VERSION 5.8 ;
BUSBITCHARS "[]" ;
DIVIDERCHAR "/" ;
UNITS
    DATABASE MICRONS 1000 ;
END UNITS

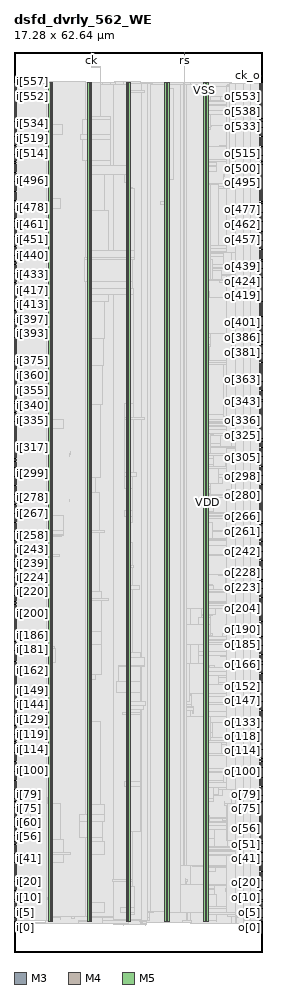
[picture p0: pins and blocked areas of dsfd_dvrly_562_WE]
MACRO dsfd_dvrly_562_WE
  FOREIGN dsfd_dvrly_562_WE 0 0 ;
  CLASS BLOCK ;
  SIZE 17.28 BY 62.64 ;
  PIN ck
    DIRECTION INPUT ;
    USE SIGNAL ;
    PORT
      LAYER M3 ;
        RECT  5.4 62.496 5.418 62.64 ;
    END
  END ck
  PIN ck_o
    DIRECTION OUTPUT ;
    USE SIGNAL ;
    PORT
      LAYER M4 ;
        RECT  17.088 60.432 17.28 60.456 ;
    END
  END ck_o
  PIN i[0]
    DIRECTION INPUT ;
    USE SIGNAL ;
    PORT
      LAYER M4 ;
        RECT  0 2.208 0.192 2.232 ;
    END
  END i[0]
  PIN i[100]
    DIRECTION INPUT ;
    USE SIGNAL ;
    PORT
      LAYER M4 ;
        RECT  0 12.624 0.192 12.648 ;
    END
  END i[100]
  PIN i[101]
    DIRECTION INPUT ;
    USE SIGNAL ;
    PORT
      LAYER M4 ;
        RECT  0 12.72 0.192 12.744 ;
    END
  END i[101]
  PIN i[102]
    DIRECTION INPUT ;
    USE SIGNAL ;
    PORT
      LAYER M4 ;
        RECT  0 12.816 0.192 12.84 ;
    END
  END i[102]
  PIN i[103]
    DIRECTION INPUT ;
    USE SIGNAL ;
    PORT
      LAYER M4 ;
        RECT  0 12.912 0.192 12.936 ;
    END
  END i[103]
  PIN i[104]
    DIRECTION INPUT ;
    USE SIGNAL ;
    PORT
      LAYER M4 ;
        RECT  0 13.008 0.192 13.032 ;
    END
  END i[104]
  PIN i[105]
    DIRECTION INPUT ;
    USE SIGNAL ;
    PORT
      LAYER M4 ;
        RECT  0 13.104 0.192 13.128 ;
    END
  END i[105]
  PIN i[106]
    DIRECTION INPUT ;
    USE SIGNAL ;
    PORT
      LAYER M4 ;
        RECT  0 13.2 0.192 13.224 ;
    END
  END i[106]
  PIN i[107]
    DIRECTION INPUT ;
    USE SIGNAL ;
    PORT
      LAYER M4 ;
        RECT  0 13.344 0.192 13.368 ;
    END
  END i[107]
  PIN i[108]
    DIRECTION INPUT ;
    USE SIGNAL ;
    PORT
      LAYER M4 ;
        RECT  0 13.44 0.192 13.464 ;
    END
  END i[108]
  PIN i[109]
    DIRECTION INPUT ;
    USE SIGNAL ;
    PORT
      LAYER M4 ;
        RECT  0 13.536 0.192 13.56 ;
    END
  END i[109]
  PIN i[10]
    DIRECTION INPUT ;
    USE SIGNAL ;
    PORT
      LAYER M4 ;
        RECT  0 3.264 0.192 3.288 ;
    END
  END i[10]
  PIN i[110]
    DIRECTION INPUT ;
    USE SIGNAL ;
    PORT
      LAYER M4 ;
        RECT  0 13.632 0.192 13.656 ;
    END
  END i[110]
  PIN i[111]
    DIRECTION INPUT ;
    USE SIGNAL ;
    PORT
      LAYER M4 ;
        RECT  0 13.728 0.192 13.752 ;
    END
  END i[111]
  PIN i[112]
    DIRECTION INPUT ;
    USE SIGNAL ;
    PORT
      LAYER M4 ;
        RECT  0 13.824 0.192 13.848 ;
    END
  END i[112]
  PIN i[113]
    DIRECTION INPUT ;
    USE SIGNAL ;
    PORT
      LAYER M4 ;
        RECT  0 13.968 0.192 13.992 ;
    END
  END i[113]
  PIN i[114]
    DIRECTION INPUT ;
    USE SIGNAL ;
    PORT
      LAYER M4 ;
        RECT  0 14.064 0.192 14.088 ;
    END
  END i[114]
  PIN i[115]
    DIRECTION INPUT ;
    USE SIGNAL ;
    PORT
      LAYER M4 ;
        RECT  0 14.16 0.192 14.184 ;
    END
  END i[115]
  PIN i[116]
    DIRECTION INPUT ;
    USE SIGNAL ;
    PORT
      LAYER M4 ;
        RECT  0 14.256 0.192 14.28 ;
    END
  END i[116]
  PIN i[117]
    DIRECTION INPUT ;
    USE SIGNAL ;
    PORT
      LAYER M4 ;
        RECT  0 14.352 0.192 14.376 ;
    END
  END i[117]
  PIN i[118]
    DIRECTION INPUT ;
    USE SIGNAL ;
    PORT
      LAYER M4 ;
        RECT  0 14.448 0.192 14.472 ;
    END
  END i[118]
  PIN i[119]
    DIRECTION INPUT ;
    USE SIGNAL ;
    PORT
      LAYER M4 ;
        RECT  0 14.592 0.192 14.616 ;
    END
  END i[119]
  PIN i[11]
    DIRECTION INPUT ;
    USE SIGNAL ;
    PORT
      LAYER M4 ;
        RECT  0 3.36 0.192 3.384 ;
    END
  END i[11]
  PIN i[120]
    DIRECTION INPUT ;
    USE SIGNAL ;
    PORT
      LAYER M4 ;
        RECT  0 14.688 0.192 14.712 ;
    END
  END i[120]
  PIN i[121]
    DIRECTION INPUT ;
    USE SIGNAL ;
    PORT
      LAYER M4 ;
        RECT  0 14.784 0.192 14.808 ;
    END
  END i[121]
  PIN i[122]
    DIRECTION INPUT ;
    USE SIGNAL ;
    PORT
      LAYER M4 ;
        RECT  0 14.88 0.192 14.904 ;
    END
  END i[122]
  PIN i[123]
    DIRECTION INPUT ;
    USE SIGNAL ;
    PORT
      LAYER M4 ;
        RECT  0 14.976 0.192 15 ;
    END
  END i[123]
  PIN i[124]
    DIRECTION INPUT ;
    USE SIGNAL ;
    PORT
      LAYER M4 ;
        RECT  0 15.072 0.192 15.096 ;
    END
  END i[124]
  PIN i[125]
    DIRECTION INPUT ;
    USE SIGNAL ;
    PORT
      LAYER M4 ;
        RECT  0 15.216 0.192 15.24 ;
    END
  END i[125]
  PIN i[126]
    DIRECTION INPUT ;
    USE SIGNAL ;
    PORT
      LAYER M4 ;
        RECT  0 15.312 0.192 15.336 ;
    END
  END i[126]
  PIN i[127]
    DIRECTION INPUT ;
    USE SIGNAL ;
    PORT
      LAYER M4 ;
        RECT  0 15.408 0.192 15.432 ;
    END
  END i[127]
  PIN i[128]
    DIRECTION INPUT ;
    USE SIGNAL ;
    PORT
      LAYER M4 ;
        RECT  0 15.504 0.192 15.528 ;
    END
  END i[128]
  PIN i[129]
    DIRECTION INPUT ;
    USE SIGNAL ;
    PORT
      LAYER M4 ;
        RECT  0 15.6 0.192 15.624 ;
    END
  END i[129]
  PIN i[12]
    DIRECTION INPUT ;
    USE SIGNAL ;
    PORT
      LAYER M4 ;
        RECT  0 3.456 0.192 3.48 ;
    END
  END i[12]
  PIN i[130]
    DIRECTION INPUT ;
    USE SIGNAL ;
    PORT
      LAYER M4 ;
        RECT  0 15.696 0.192 15.72 ;
    END
  END i[130]
  PIN i[131]
    DIRECTION INPUT ;
    USE SIGNAL ;
    PORT
      LAYER M4 ;
        RECT  0 15.84 0.192 15.864 ;
    END
  END i[131]
  PIN i[132]
    DIRECTION INPUT ;
    USE SIGNAL ;
    PORT
      LAYER M4 ;
        RECT  0 15.936 0.192 15.96 ;
    END
  END i[132]
  PIN i[133]
    DIRECTION INPUT ;
    USE SIGNAL ;
    PORT
      LAYER M4 ;
        RECT  0 16.032 0.192 16.056 ;
    END
  END i[133]
  PIN i[134]
    DIRECTION INPUT ;
    USE SIGNAL ;
    PORT
      LAYER M4 ;
        RECT  0 16.128 0.192 16.152 ;
    END
  END i[134]
  PIN i[135]
    DIRECTION INPUT ;
    USE SIGNAL ;
    PORT
      LAYER M4 ;
        RECT  0 16.224 0.192 16.248 ;
    END
  END i[135]
  PIN i[136]
    DIRECTION INPUT ;
    USE SIGNAL ;
    PORT
      LAYER M4 ;
        RECT  0 16.32 0.192 16.344 ;
    END
  END i[136]
  PIN i[137]
    DIRECTION INPUT ;
    USE SIGNAL ;
    PORT
      LAYER M4 ;
        RECT  0 16.464 0.192 16.488 ;
    END
  END i[137]
  PIN i[138]
    DIRECTION INPUT ;
    USE SIGNAL ;
    PORT
      LAYER M4 ;
        RECT  0 16.56 0.192 16.584 ;
    END
  END i[138]
  PIN i[139]
    DIRECTION INPUT ;
    USE SIGNAL ;
    PORT
      LAYER M4 ;
        RECT  0 16.656 0.192 16.68 ;
    END
  END i[139]
  PIN i[13]
    DIRECTION INPUT ;
    USE SIGNAL ;
    PORT
      LAYER M4 ;
        RECT  0 3.552 0.192 3.576 ;
    END
  END i[13]
  PIN i[140]
    DIRECTION INPUT ;
    USE SIGNAL ;
    PORT
      LAYER M4 ;
        RECT  0 16.752 0.192 16.776 ;
    END
  END i[140]
  PIN i[141]
    DIRECTION INPUT ;
    USE SIGNAL ;
    PORT
      LAYER M4 ;
        RECT  0 16.848 0.192 16.872 ;
    END
  END i[141]
  PIN i[142]
    DIRECTION INPUT ;
    USE SIGNAL ;
    PORT
      LAYER M4 ;
        RECT  0 16.944 0.192 16.968 ;
    END
  END i[142]
  PIN i[143]
    DIRECTION INPUT ;
    USE SIGNAL ;
    PORT
      LAYER M4 ;
        RECT  0 17.04 0.192 17.064 ;
    END
  END i[143]
  PIN i[144]
    DIRECTION INPUT ;
    USE SIGNAL ;
    PORT
      LAYER M4 ;
        RECT  0 17.184 0.192 17.208 ;
    END
  END i[144]
  PIN i[145]
    DIRECTION INPUT ;
    USE SIGNAL ;
    PORT
      LAYER M4 ;
        RECT  0 17.28 0.192 17.304 ;
    END
  END i[145]
  PIN i[146]
    DIRECTION INPUT ;
    USE SIGNAL ;
    PORT
      LAYER M4 ;
        RECT  0 17.376 0.192 17.4 ;
    END
  END i[146]
  PIN i[147]
    DIRECTION INPUT ;
    USE SIGNAL ;
    PORT
      LAYER M4 ;
        RECT  0 17.472 0.192 17.496 ;
    END
  END i[147]
  PIN i[148]
    DIRECTION INPUT ;
    USE SIGNAL ;
    PORT
      LAYER M4 ;
        RECT  0 17.568 0.192 17.592 ;
    END
  END i[148]
  PIN i[149]
    DIRECTION INPUT ;
    USE SIGNAL ;
    PORT
      LAYER M4 ;
        RECT  0 17.664 0.192 17.688 ;
    END
  END i[149]
  PIN i[14]
    DIRECTION INPUT ;
    USE SIGNAL ;
    PORT
      LAYER M4 ;
        RECT  0 3.696 0.192 3.72 ;
    END
  END i[14]
  PIN i[150]
    DIRECTION INPUT ;
    USE SIGNAL ;
    PORT
      LAYER M4 ;
        RECT  0 17.808 0.192 17.832 ;
    END
  END i[150]
  PIN i[151]
    DIRECTION INPUT ;
    USE SIGNAL ;
    PORT
      LAYER M4 ;
        RECT  0 17.904 0.192 17.928 ;
    END
  END i[151]
  PIN i[152]
    DIRECTION INPUT ;
    USE SIGNAL ;
    PORT
      LAYER M4 ;
        RECT  0 18 0.192 18.024 ;
    END
  END i[152]
  PIN i[153]
    DIRECTION INPUT ;
    USE SIGNAL ;
    PORT
      LAYER M4 ;
        RECT  0 18.096 0.192 18.12 ;
    END
  END i[153]
  PIN i[154]
    DIRECTION INPUT ;
    USE SIGNAL ;
    PORT
      LAYER M4 ;
        RECT  0 18.192 0.192 18.216 ;
    END
  END i[154]
  PIN i[155]
    DIRECTION INPUT ;
    USE SIGNAL ;
    PORT
      LAYER M4 ;
        RECT  0 18.288 0.192 18.312 ;
    END
  END i[155]
  PIN i[156]
    DIRECTION INPUT ;
    USE SIGNAL ;
    PORT
      LAYER M4 ;
        RECT  0 18.432 0.192 18.456 ;
    END
  END i[156]
  PIN i[157]
    DIRECTION INPUT ;
    USE SIGNAL ;
    PORT
      LAYER M4 ;
        RECT  0 18.528 0.192 18.552 ;
    END
  END i[157]
  PIN i[158]
    DIRECTION INPUT ;
    USE SIGNAL ;
    PORT
      LAYER M4 ;
        RECT  0 18.624 0.192 18.648 ;
    END
  END i[158]
  PIN i[159]
    DIRECTION INPUT ;
    USE SIGNAL ;
    PORT
      LAYER M4 ;
        RECT  0 18.72 0.192 18.744 ;
    END
  END i[159]
  PIN i[15]
    DIRECTION INPUT ;
    USE SIGNAL ;
    PORT
      LAYER M4 ;
        RECT  0 3.792 0.192 3.816 ;
    END
  END i[15]
  PIN i[160]
    DIRECTION INPUT ;
    USE SIGNAL ;
    PORT
      LAYER M4 ;
        RECT  0 18.816 0.192 18.84 ;
    END
  END i[160]
  PIN i[161]
    DIRECTION INPUT ;
    USE SIGNAL ;
    PORT
      LAYER M4 ;
        RECT  0 18.912 0.192 18.936 ;
    END
  END i[161]
  PIN i[162]
    DIRECTION INPUT ;
    USE SIGNAL ;
    PORT
      LAYER M4 ;
        RECT  0 19.056 0.192 19.08 ;
    END
  END i[162]
  PIN i[163]
    DIRECTION INPUT ;
    USE SIGNAL ;
    PORT
      LAYER M4 ;
        RECT  0 19.152 0.192 19.176 ;
    END
  END i[163]
  PIN i[164]
    DIRECTION INPUT ;
    USE SIGNAL ;
    PORT
      LAYER M4 ;
        RECT  0 19.248 0.192 19.272 ;
    END
  END i[164]
  PIN i[165]
    DIRECTION INPUT ;
    USE SIGNAL ;
    PORT
      LAYER M4 ;
        RECT  0 19.344 0.192 19.368 ;
    END
  END i[165]
  PIN i[166]
    DIRECTION INPUT ;
    USE SIGNAL ;
    PORT
      LAYER M4 ;
        RECT  0 19.44 0.192 19.464 ;
    END
  END i[166]
  PIN i[167]
    DIRECTION INPUT ;
    USE SIGNAL ;
    PORT
      LAYER M4 ;
        RECT  0 19.536 0.192 19.56 ;
    END
  END i[167]
  PIN i[168]
    DIRECTION INPUT ;
    USE SIGNAL ;
    PORT
      LAYER M4 ;
        RECT  0 19.68 0.192 19.704 ;
    END
  END i[168]
  PIN i[169]
    DIRECTION INPUT ;
    USE SIGNAL ;
    PORT
      LAYER M4 ;
        RECT  0 19.776 0.192 19.8 ;
    END
  END i[169]
  PIN i[16]
    DIRECTION INPUT ;
    USE SIGNAL ;
    PORT
      LAYER M4 ;
        RECT  0 3.888 0.192 3.912 ;
    END
  END i[16]
  PIN i[170]
    DIRECTION INPUT ;
    USE SIGNAL ;
    PORT
      LAYER M4 ;
        RECT  0 19.872 0.192 19.896 ;
    END
  END i[170]
  PIN i[171]
    DIRECTION INPUT ;
    USE SIGNAL ;
    PORT
      LAYER M4 ;
        RECT  0 19.968 0.192 19.992 ;
    END
  END i[171]
  PIN i[172]
    DIRECTION INPUT ;
    USE SIGNAL ;
    PORT
      LAYER M4 ;
        RECT  0 20.064 0.192 20.088 ;
    END
  END i[172]
  PIN i[173]
    DIRECTION INPUT ;
    USE SIGNAL ;
    PORT
      LAYER M4 ;
        RECT  0 20.16 0.192 20.184 ;
    END
  END i[173]
  PIN i[174]
    DIRECTION INPUT ;
    USE SIGNAL ;
    PORT
      LAYER M4 ;
        RECT  0 20.304 0.192 20.328 ;
    END
  END i[174]
  PIN i[175]
    DIRECTION INPUT ;
    USE SIGNAL ;
    PORT
      LAYER M4 ;
        RECT  0 20.4 0.192 20.424 ;
    END
  END i[175]
  PIN i[176]
    DIRECTION INPUT ;
    USE SIGNAL ;
    PORT
      LAYER M4 ;
        RECT  0 20.496 0.192 20.52 ;
    END
  END i[176]
  PIN i[177]
    DIRECTION INPUT ;
    USE SIGNAL ;
    PORT
      LAYER M4 ;
        RECT  0 20.592 0.192 20.616 ;
    END
  END i[177]
  PIN i[178]
    DIRECTION INPUT ;
    USE SIGNAL ;
    PORT
      LAYER M4 ;
        RECT  0 20.688 0.192 20.712 ;
    END
  END i[178]
  PIN i[179]
    DIRECTION INPUT ;
    USE SIGNAL ;
    PORT
      LAYER M4 ;
        RECT  0 20.784 0.192 20.808 ;
    END
  END i[179]
  PIN i[17]
    DIRECTION INPUT ;
    USE SIGNAL ;
    PORT
      LAYER M4 ;
        RECT  0 3.984 0.192 4.008 ;
    END
  END i[17]
  PIN i[180]
    DIRECTION INPUT ;
    USE SIGNAL ;
    PORT
      LAYER M4 ;
        RECT  0 20.88 0.192 20.904 ;
    END
  END i[180]
  PIN i[181]
    DIRECTION INPUT ;
    USE SIGNAL ;
    PORT
      LAYER M4 ;
        RECT  0 21.024 0.192 21.048 ;
    END
  END i[181]
  PIN i[182]
    DIRECTION INPUT ;
    USE SIGNAL ;
    PORT
      LAYER M4 ;
        RECT  0 21.12 0.192 21.144 ;
    END
  END i[182]
  PIN i[183]
    DIRECTION INPUT ;
    USE SIGNAL ;
    PORT
      LAYER M4 ;
        RECT  0 21.216 0.192 21.24 ;
    END
  END i[183]
  PIN i[184]
    DIRECTION INPUT ;
    USE SIGNAL ;
    PORT
      LAYER M4 ;
        RECT  0 21.312 0.192 21.336 ;
    END
  END i[184]
  PIN i[185]
    DIRECTION INPUT ;
    USE SIGNAL ;
    PORT
      LAYER M4 ;
        RECT  0 21.408 0.192 21.432 ;
    END
  END i[185]
  PIN i[186]
    DIRECTION INPUT ;
    USE SIGNAL ;
    PORT
      LAYER M4 ;
        RECT  0 21.504 0.192 21.528 ;
    END
  END i[186]
  PIN i[187]
    DIRECTION INPUT ;
    USE SIGNAL ;
    PORT
      LAYER M4 ;
        RECT  0 21.648 0.192 21.672 ;
    END
  END i[187]
  PIN i[188]
    DIRECTION INPUT ;
    USE SIGNAL ;
    PORT
      LAYER M4 ;
        RECT  0 21.744 0.192 21.768 ;
    END
  END i[188]
  PIN i[189]
    DIRECTION INPUT ;
    USE SIGNAL ;
    PORT
      LAYER M4 ;
        RECT  0 21.84 0.192 21.864 ;
    END
  END i[189]
  PIN i[18]
    DIRECTION INPUT ;
    USE SIGNAL ;
    PORT
      LAYER M4 ;
        RECT  0 4.08 0.192 4.104 ;
    END
  END i[18]
  PIN i[190]
    DIRECTION INPUT ;
    USE SIGNAL ;
    PORT
      LAYER M4 ;
        RECT  0 21.936 0.192 21.96 ;
    END
  END i[190]
  PIN i[191]
    DIRECTION INPUT ;
    USE SIGNAL ;
    PORT
      LAYER M4 ;
        RECT  0 22.032 0.192 22.056 ;
    END
  END i[191]
  PIN i[192]
    DIRECTION INPUT ;
    USE SIGNAL ;
    PORT
      LAYER M4 ;
        RECT  0 22.128 0.192 22.152 ;
    END
  END i[192]
  PIN i[193]
    DIRECTION INPUT ;
    USE SIGNAL ;
    PORT
      LAYER M4 ;
        RECT  0 22.272 0.192 22.296 ;
    END
  END i[193]
  PIN i[194]
    DIRECTION INPUT ;
    USE SIGNAL ;
    PORT
      LAYER M4 ;
        RECT  0 22.368 0.192 22.392 ;
    END
  END i[194]
  PIN i[195]
    DIRECTION INPUT ;
    USE SIGNAL ;
    PORT
      LAYER M4 ;
        RECT  0 22.464 0.192 22.488 ;
    END
  END i[195]
  PIN i[196]
    DIRECTION INPUT ;
    USE SIGNAL ;
    PORT
      LAYER M4 ;
        RECT  0 22.56 0.192 22.584 ;
    END
  END i[196]
  PIN i[197]
    DIRECTION INPUT ;
    USE SIGNAL ;
    PORT
      LAYER M4 ;
        RECT  0 22.656 0.192 22.68 ;
    END
  END i[197]
  PIN i[198]
    DIRECTION INPUT ;
    USE SIGNAL ;
    PORT
      LAYER M4 ;
        RECT  0 22.752 0.192 22.776 ;
    END
  END i[198]
  PIN i[199]
    DIRECTION INPUT ;
    USE SIGNAL ;
    PORT
      LAYER M4 ;
        RECT  0 22.896 0.192 22.92 ;
    END
  END i[199]
  PIN i[19]
    DIRECTION INPUT ;
    USE SIGNAL ;
    PORT
      LAYER M4 ;
        RECT  0 4.176 0.192 4.2 ;
    END
  END i[19]
  PIN i[1]
    DIRECTION INPUT ;
    USE SIGNAL ;
    PORT
      LAYER M4 ;
        RECT  0 2.304 0.192 2.328 ;
    END
  END i[1]
  PIN i[200]
    DIRECTION INPUT ;
    USE SIGNAL ;
    PORT
      LAYER M4 ;
        RECT  0 22.992 0.192 23.016 ;
    END
  END i[200]
  PIN i[201]
    DIRECTION INPUT ;
    USE SIGNAL ;
    PORT
      LAYER M4 ;
        RECT  0 23.088 0.192 23.112 ;
    END
  END i[201]
  PIN i[202]
    DIRECTION INPUT ;
    USE SIGNAL ;
    PORT
      LAYER M4 ;
        RECT  0 23.184 0.192 23.208 ;
    END
  END i[202]
  PIN i[203]
    DIRECTION INPUT ;
    USE SIGNAL ;
    PORT
      LAYER M4 ;
        RECT  0 23.28 0.192 23.304 ;
    END
  END i[203]
  PIN i[204]
    DIRECTION INPUT ;
    USE SIGNAL ;
    PORT
      LAYER M4 ;
        RECT  0 23.376 0.192 23.4 ;
    END
  END i[204]
  PIN i[205]
    DIRECTION INPUT ;
    USE SIGNAL ;
    PORT
      LAYER M4 ;
        RECT  0 23.52 0.192 23.544 ;
    END
  END i[205]
  PIN i[206]
    DIRECTION INPUT ;
    USE SIGNAL ;
    PORT
      LAYER M4 ;
        RECT  0 23.616 0.192 23.64 ;
    END
  END i[206]
  PIN i[207]
    DIRECTION INPUT ;
    USE SIGNAL ;
    PORT
      LAYER M4 ;
        RECT  0 23.712 0.192 23.736 ;
    END
  END i[207]
  PIN i[208]
    DIRECTION INPUT ;
    USE SIGNAL ;
    PORT
      LAYER M4 ;
        RECT  0 23.808 0.192 23.832 ;
    END
  END i[208]
  PIN i[209]
    DIRECTION INPUT ;
    USE SIGNAL ;
    PORT
      LAYER M4 ;
        RECT  0 23.904 0.192 23.928 ;
    END
  END i[209]
  PIN i[20]
    DIRECTION INPUT ;
    USE SIGNAL ;
    PORT
      LAYER M4 ;
        RECT  0 4.32 0.192 4.344 ;
    END
  END i[20]
  PIN i[210]
    DIRECTION INPUT ;
    USE SIGNAL ;
    PORT
      LAYER M4 ;
        RECT  0 24 0.192 24.024 ;
    END
  END i[210]
  PIN i[211]
    DIRECTION INPUT ;
    USE SIGNAL ;
    PORT
      LAYER M4 ;
        RECT  0 24.096 0.192 24.12 ;
    END
  END i[211]
  PIN i[212]
    DIRECTION INPUT ;
    USE SIGNAL ;
    PORT
      LAYER M4 ;
        RECT  0 24.24 0.192 24.264 ;
    END
  END i[212]
  PIN i[213]
    DIRECTION INPUT ;
    USE SIGNAL ;
    PORT
      LAYER M4 ;
        RECT  0 24.336 0.192 24.36 ;
    END
  END i[213]
  PIN i[214]
    DIRECTION INPUT ;
    USE SIGNAL ;
    PORT
      LAYER M4 ;
        RECT  0 24.432 0.192 24.456 ;
    END
  END i[214]
  PIN i[215]
    DIRECTION INPUT ;
    USE SIGNAL ;
    PORT
      LAYER M4 ;
        RECT  0 24.528 0.192 24.552 ;
    END
  END i[215]
  PIN i[216]
    DIRECTION INPUT ;
    USE SIGNAL ;
    PORT
      LAYER M4 ;
        RECT  0 24.624 0.192 24.648 ;
    END
  END i[216]
  PIN i[217]
    DIRECTION INPUT ;
    USE SIGNAL ;
    PORT
      LAYER M4 ;
        RECT  0 24.72 0.192 24.744 ;
    END
  END i[217]
  PIN i[218]
    DIRECTION INPUT ;
    USE SIGNAL ;
    PORT
      LAYER M4 ;
        RECT  0 24.864 0.192 24.888 ;
    END
  END i[218]
  PIN i[219]
    DIRECTION INPUT ;
    USE SIGNAL ;
    PORT
      LAYER M4 ;
        RECT  0 24.96 0.192 24.984 ;
    END
  END i[219]
  PIN i[21]
    DIRECTION INPUT ;
    USE SIGNAL ;
    PORT
      LAYER M4 ;
        RECT  0 4.416 0.192 4.44 ;
    END
  END i[21]
  PIN i[220]
    DIRECTION INPUT ;
    USE SIGNAL ;
    PORT
      LAYER M4 ;
        RECT  0 25.056 0.192 25.08 ;
    END
  END i[220]
  PIN i[221]
    DIRECTION INPUT ;
    USE SIGNAL ;
    PORT
      LAYER M4 ;
        RECT  0 25.152 0.192 25.176 ;
    END
  END i[221]
  PIN i[222]
    DIRECTION INPUT ;
    USE SIGNAL ;
    PORT
      LAYER M4 ;
        RECT  0 25.248 0.192 25.272 ;
    END
  END i[222]
  PIN i[223]
    DIRECTION INPUT ;
    USE SIGNAL ;
    PORT
      LAYER M4 ;
        RECT  0 25.344 0.192 25.368 ;
    END
  END i[223]
  PIN i[224]
    DIRECTION INPUT ;
    USE SIGNAL ;
    PORT
      LAYER M4 ;
        RECT  0 25.488 0.192 25.512 ;
    END
  END i[224]
  PIN i[225]
    DIRECTION INPUT ;
    USE SIGNAL ;
    PORT
      LAYER M4 ;
        RECT  0 25.584 0.192 25.608 ;
    END
  END i[225]
  PIN i[226]
    DIRECTION INPUT ;
    USE SIGNAL ;
    PORT
      LAYER M4 ;
        RECT  0 25.68 0.192 25.704 ;
    END
  END i[226]
  PIN i[227]
    DIRECTION INPUT ;
    USE SIGNAL ;
    PORT
      LAYER M4 ;
        RECT  0 25.776 0.192 25.8 ;
    END
  END i[227]
  PIN i[228]
    DIRECTION INPUT ;
    USE SIGNAL ;
    PORT
      LAYER M4 ;
        RECT  0 25.872 0.192 25.896 ;
    END
  END i[228]
  PIN i[229]
    DIRECTION INPUT ;
    USE SIGNAL ;
    PORT
      LAYER M4 ;
        RECT  0 25.968 0.192 25.992 ;
    END
  END i[229]
  PIN i[22]
    DIRECTION INPUT ;
    USE SIGNAL ;
    PORT
      LAYER M4 ;
        RECT  0 4.512 0.192 4.536 ;
    END
  END i[22]
  PIN i[230]
    DIRECTION INPUT ;
    USE SIGNAL ;
    PORT
      LAYER M4 ;
        RECT  0 26.112 0.192 26.136 ;
    END
  END i[230]
  PIN i[231]
    DIRECTION INPUT ;
    USE SIGNAL ;
    PORT
      LAYER M4 ;
        RECT  0 26.208 0.192 26.232 ;
    END
  END i[231]
  PIN i[232]
    DIRECTION INPUT ;
    USE SIGNAL ;
    PORT
      LAYER M4 ;
        RECT  0 26.304 0.192 26.328 ;
    END
  END i[232]
  PIN i[233]
    DIRECTION INPUT ;
    USE SIGNAL ;
    PORT
      LAYER M4 ;
        RECT  0 26.4 0.192 26.424 ;
    END
  END i[233]
  PIN i[234]
    DIRECTION INPUT ;
    USE SIGNAL ;
    PORT
      LAYER M4 ;
        RECT  0 26.496 0.192 26.52 ;
    END
  END i[234]
  PIN i[235]
    DIRECTION INPUT ;
    USE SIGNAL ;
    PORT
      LAYER M4 ;
        RECT  0 26.592 0.192 26.616 ;
    END
  END i[235]
  PIN i[236]
    DIRECTION INPUT ;
    USE SIGNAL ;
    PORT
      LAYER M4 ;
        RECT  0 26.736 0.192 26.76 ;
    END
  END i[236]
  PIN i[237]
    DIRECTION INPUT ;
    USE SIGNAL ;
    PORT
      LAYER M4 ;
        RECT  0 26.832 0.192 26.856 ;
    END
  END i[237]
  PIN i[238]
    DIRECTION INPUT ;
    USE SIGNAL ;
    PORT
      LAYER M4 ;
        RECT  0 26.928 0.192 26.952 ;
    END
  END i[238]
  PIN i[239]
    DIRECTION INPUT ;
    USE SIGNAL ;
    PORT
      LAYER M4 ;
        RECT  0 27.024 0.192 27.048 ;
    END
  END i[239]
  PIN i[23]
    DIRECTION INPUT ;
    USE SIGNAL ;
    PORT
      LAYER M4 ;
        RECT  0 4.608 0.192 4.632 ;
    END
  END i[23]
  PIN i[240]
    DIRECTION INPUT ;
    USE SIGNAL ;
    PORT
      LAYER M4 ;
        RECT  0 27.12 0.192 27.144 ;
    END
  END i[240]
  PIN i[241]
    DIRECTION INPUT ;
    USE SIGNAL ;
    PORT
      LAYER M4 ;
        RECT  0 27.216 0.192 27.24 ;
    END
  END i[241]
  PIN i[242]
    DIRECTION INPUT ;
    USE SIGNAL ;
    PORT
      LAYER M4 ;
        RECT  0 27.36 0.192 27.384 ;
    END
  END i[242]
  PIN i[243]
    DIRECTION INPUT ;
    USE SIGNAL ;
    PORT
      LAYER M4 ;
        RECT  0 27.456 0.192 27.48 ;
    END
  END i[243]
  PIN i[244]
    DIRECTION INPUT ;
    USE SIGNAL ;
    PORT
      LAYER M4 ;
        RECT  0 27.552 0.192 27.576 ;
    END
  END i[244]
  PIN i[245]
    DIRECTION INPUT ;
    USE SIGNAL ;
    PORT
      LAYER M4 ;
        RECT  0 27.648 0.192 27.672 ;
    END
  END i[245]
  PIN i[246]
    DIRECTION INPUT ;
    USE SIGNAL ;
    PORT
      LAYER M4 ;
        RECT  0 27.744 0.192 27.768 ;
    END
  END i[246]
  PIN i[247]
    DIRECTION INPUT ;
    USE SIGNAL ;
    PORT
      LAYER M4 ;
        RECT  0 27.84 0.192 27.864 ;
    END
  END i[247]
  PIN i[248]
    DIRECTION INPUT ;
    USE SIGNAL ;
    PORT
      LAYER M4 ;
        RECT  0 27.936 0.192 27.96 ;
    END
  END i[248]
  PIN i[249]
    DIRECTION INPUT ;
    USE SIGNAL ;
    PORT
      LAYER M4 ;
        RECT  0 28.08 0.192 28.104 ;
    END
  END i[249]
  PIN i[24]
    DIRECTION INPUT ;
    USE SIGNAL ;
    PORT
      LAYER M4 ;
        RECT  0 4.704 0.192 4.728 ;
    END
  END i[24]
  PIN i[250]
    DIRECTION INPUT ;
    USE SIGNAL ;
    PORT
      LAYER M4 ;
        RECT  0 28.176 0.192 28.2 ;
    END
  END i[250]
  PIN i[251]
    DIRECTION INPUT ;
    USE SIGNAL ;
    PORT
      LAYER M4 ;
        RECT  0 28.272 0.192 28.296 ;
    END
  END i[251]
  PIN i[252]
    DIRECTION INPUT ;
    USE SIGNAL ;
    PORT
      LAYER M4 ;
        RECT  0 28.368 0.192 28.392 ;
    END
  END i[252]
  PIN i[253]
    DIRECTION INPUT ;
    USE SIGNAL ;
    PORT
      LAYER M4 ;
        RECT  0 28.464 0.192 28.488 ;
    END
  END i[253]
  PIN i[254]
    DIRECTION INPUT ;
    USE SIGNAL ;
    PORT
      LAYER M4 ;
        RECT  0 28.56 0.192 28.584 ;
    END
  END i[254]
  PIN i[255]
    DIRECTION INPUT ;
    USE SIGNAL ;
    PORT
      LAYER M4 ;
        RECT  0 28.704 0.192 28.728 ;
    END
  END i[255]
  PIN i[256]
    DIRECTION INPUT ;
    USE SIGNAL ;
    PORT
      LAYER M4 ;
        RECT  0 28.8 0.192 28.824 ;
    END
  END i[256]
  PIN i[257]
    DIRECTION INPUT ;
    USE SIGNAL ;
    PORT
      LAYER M4 ;
        RECT  0 28.896 0.192 28.92 ;
    END
  END i[257]
  PIN i[258]
    DIRECTION INPUT ;
    USE SIGNAL ;
    PORT
      LAYER M4 ;
        RECT  0 28.992 0.192 29.016 ;
    END
  END i[258]
  PIN i[259]
    DIRECTION INPUT ;
    USE SIGNAL ;
    PORT
      LAYER M4 ;
        RECT  0 29.088 0.192 29.112 ;
    END
  END i[259]
  PIN i[25]
    DIRECTION INPUT ;
    USE SIGNAL ;
    PORT
      LAYER M4 ;
        RECT  0 4.8 0.192 4.824 ;
    END
  END i[25]
  PIN i[260]
    DIRECTION INPUT ;
    USE SIGNAL ;
    PORT
      LAYER M4 ;
        RECT  0 29.184 0.192 29.208 ;
    END
  END i[260]
  PIN i[261]
    DIRECTION INPUT ;
    USE SIGNAL ;
    PORT
      LAYER M4 ;
        RECT  0 29.328 0.192 29.352 ;
    END
  END i[261]
  PIN i[262]
    DIRECTION INPUT ;
    USE SIGNAL ;
    PORT
      LAYER M4 ;
        RECT  0 29.424 0.192 29.448 ;
    END
  END i[262]
  PIN i[263]
    DIRECTION INPUT ;
    USE SIGNAL ;
    PORT
      LAYER M4 ;
        RECT  0 29.52 0.192 29.544 ;
    END
  END i[263]
  PIN i[264]
    DIRECTION INPUT ;
    USE SIGNAL ;
    PORT
      LAYER M4 ;
        RECT  0 29.616 0.192 29.64 ;
    END
  END i[264]
  PIN i[265]
    DIRECTION INPUT ;
    USE SIGNAL ;
    PORT
      LAYER M4 ;
        RECT  0 29.712 0.192 29.736 ;
    END
  END i[265]
  PIN i[266]
    DIRECTION INPUT ;
    USE SIGNAL ;
    PORT
      LAYER M4 ;
        RECT  0 29.808 0.192 29.832 ;
    END
  END i[266]
  PIN i[267]
    DIRECTION INPUT ;
    USE SIGNAL ;
    PORT
      LAYER M4 ;
        RECT  0 29.952 0.192 29.976 ;
    END
  END i[267]
  PIN i[268]
    DIRECTION INPUT ;
    USE SIGNAL ;
    PORT
      LAYER M4 ;
        RECT  0 30.048 0.192 30.072 ;
    END
  END i[268]
  PIN i[269]
    DIRECTION INPUT ;
    USE SIGNAL ;
    PORT
      LAYER M4 ;
        RECT  0 30.144 0.192 30.168 ;
    END
  END i[269]
  PIN i[26]
    DIRECTION INPUT ;
    USE SIGNAL ;
    PORT
      LAYER M4 ;
        RECT  0 4.944 0.192 4.968 ;
    END
  END i[26]
  PIN i[270]
    DIRECTION INPUT ;
    USE SIGNAL ;
    PORT
      LAYER M4 ;
        RECT  0 30.24 0.192 30.264 ;
    END
  END i[270]
  PIN i[271]
    DIRECTION INPUT ;
    USE SIGNAL ;
    PORT
      LAYER M4 ;
        RECT  0 30.336 0.192 30.36 ;
    END
  END i[271]
  PIN i[272]
    DIRECTION INPUT ;
    USE SIGNAL ;
    PORT
      LAYER M4 ;
        RECT  0 30.432 0.192 30.456 ;
    END
  END i[272]
  PIN i[273]
    DIRECTION INPUT ;
    USE SIGNAL ;
    PORT
      LAYER M4 ;
        RECT  0 30.576 0.192 30.6 ;
    END
  END i[273]
  PIN i[274]
    DIRECTION INPUT ;
    USE SIGNAL ;
    PORT
      LAYER M4 ;
        RECT  0 30.672 0.192 30.696 ;
    END
  END i[274]
  PIN i[275]
    DIRECTION INPUT ;
    USE SIGNAL ;
    PORT
      LAYER M4 ;
        RECT  0 30.768 0.192 30.792 ;
    END
  END i[275]
  PIN i[276]
    DIRECTION INPUT ;
    USE SIGNAL ;
    PORT
      LAYER M4 ;
        RECT  0 30.864 0.192 30.888 ;
    END
  END i[276]
  PIN i[277]
    DIRECTION INPUT ;
    USE SIGNAL ;
    PORT
      LAYER M4 ;
        RECT  0 30.96 0.192 30.984 ;
    END
  END i[277]
  PIN i[278]
    DIRECTION INPUT ;
    USE SIGNAL ;
    PORT
      LAYER M4 ;
        RECT  0 31.056 0.192 31.08 ;
    END
  END i[278]
  PIN i[279]
    DIRECTION INPUT ;
    USE SIGNAL ;
    PORT
      LAYER M4 ;
        RECT  0 31.2 0.192 31.224 ;
    END
  END i[279]
  PIN i[27]
    DIRECTION INPUT ;
    USE SIGNAL ;
    PORT
      LAYER M4 ;
        RECT  0 5.04 0.192 5.064 ;
    END
  END i[27]
  PIN i[280]
    DIRECTION INPUT ;
    USE SIGNAL ;
    PORT
      LAYER M4 ;
        RECT  0 31.296 0.192 31.32 ;
    END
  END i[280]
  PIN i[281]
    DIRECTION INPUT ;
    USE SIGNAL ;
    PORT
      LAYER M4 ;
        RECT  0 31.392 0.192 31.416 ;
    END
  END i[281]
  PIN i[282]
    DIRECTION INPUT ;
    USE SIGNAL ;
    PORT
      LAYER M4 ;
        RECT  0 31.488 0.192 31.512 ;
    END
  END i[282]
  PIN i[283]
    DIRECTION INPUT ;
    USE SIGNAL ;
    PORT
      LAYER M4 ;
        RECT  0 31.584 0.192 31.608 ;
    END
  END i[283]
  PIN i[284]
    DIRECTION INPUT ;
    USE SIGNAL ;
    PORT
      LAYER M4 ;
        RECT  0 31.68 0.192 31.704 ;
    END
  END i[284]
  PIN i[285]
    DIRECTION INPUT ;
    USE SIGNAL ;
    PORT
      LAYER M4 ;
        RECT  0 31.776 0.192 31.8 ;
    END
  END i[285]
  PIN i[286]
    DIRECTION INPUT ;
    USE SIGNAL ;
    PORT
      LAYER M4 ;
        RECT  0 31.92 0.192 31.944 ;
    END
  END i[286]
  PIN i[287]
    DIRECTION INPUT ;
    USE SIGNAL ;
    PORT
      LAYER M4 ;
        RECT  0 32.016 0.192 32.04 ;
    END
  END i[287]
  PIN i[288]
    DIRECTION INPUT ;
    USE SIGNAL ;
    PORT
      LAYER M4 ;
        RECT  0 32.112 0.192 32.136 ;
    END
  END i[288]
  PIN i[289]
    DIRECTION INPUT ;
    USE SIGNAL ;
    PORT
      LAYER M4 ;
        RECT  0 32.208 0.192 32.232 ;
    END
  END i[289]
  PIN i[28]
    DIRECTION INPUT ;
    USE SIGNAL ;
    PORT
      LAYER M4 ;
        RECT  0 5.136 0.192 5.16 ;
    END
  END i[28]
  PIN i[290]
    DIRECTION INPUT ;
    USE SIGNAL ;
    PORT
      LAYER M4 ;
        RECT  0 32.304 0.192 32.328 ;
    END
  END i[290]
  PIN i[291]
    DIRECTION INPUT ;
    USE SIGNAL ;
    PORT
      LAYER M4 ;
        RECT  0 32.4 0.192 32.424 ;
    END
  END i[291]
  PIN i[292]
    DIRECTION INPUT ;
    USE SIGNAL ;
    PORT
      LAYER M4 ;
        RECT  0 32.544 0.192 32.568 ;
    END
  END i[292]
  PIN i[293]
    DIRECTION INPUT ;
    USE SIGNAL ;
    PORT
      LAYER M4 ;
        RECT  0 32.64 0.192 32.664 ;
    END
  END i[293]
  PIN i[294]
    DIRECTION INPUT ;
    USE SIGNAL ;
    PORT
      LAYER M4 ;
        RECT  0 32.736 0.192 32.76 ;
    END
  END i[294]
  PIN i[295]
    DIRECTION INPUT ;
    USE SIGNAL ;
    PORT
      LAYER M4 ;
        RECT  0 32.832 0.192 32.856 ;
    END
  END i[295]
  PIN i[296]
    DIRECTION INPUT ;
    USE SIGNAL ;
    PORT
      LAYER M4 ;
        RECT  0 32.928 0.192 32.952 ;
    END
  END i[296]
  PIN i[297]
    DIRECTION INPUT ;
    USE SIGNAL ;
    PORT
      LAYER M4 ;
        RECT  0 33.024 0.192 33.048 ;
    END
  END i[297]
  PIN i[298]
    DIRECTION INPUT ;
    USE SIGNAL ;
    PORT
      LAYER M4 ;
        RECT  0 33.168 0.192 33.192 ;
    END
  END i[298]
  PIN i[299]
    DIRECTION INPUT ;
    USE SIGNAL ;
    PORT
      LAYER M4 ;
        RECT  0 33.264 0.192 33.288 ;
    END
  END i[299]
  PIN i[29]
    DIRECTION INPUT ;
    USE SIGNAL ;
    PORT
      LAYER M4 ;
        RECT  0 5.232 0.192 5.256 ;
    END
  END i[29]
  PIN i[2]
    DIRECTION INPUT ;
    USE SIGNAL ;
    PORT
      LAYER M4 ;
        RECT  0 2.448 0.192 2.472 ;
    END
  END i[2]
  PIN i[300]
    DIRECTION INPUT ;
    USE SIGNAL ;
    PORT
      LAYER M4 ;
        RECT  0 33.36 0.192 33.384 ;
    END
  END i[300]
  PIN i[301]
    DIRECTION INPUT ;
    USE SIGNAL ;
    PORT
      LAYER M4 ;
        RECT  0 33.456 0.192 33.48 ;
    END
  END i[301]
  PIN i[302]
    DIRECTION INPUT ;
    USE SIGNAL ;
    PORT
      LAYER M4 ;
        RECT  0 33.552 0.192 33.576 ;
    END
  END i[302]
  PIN i[303]
    DIRECTION INPUT ;
    USE SIGNAL ;
    PORT
      LAYER M4 ;
        RECT  0 33.648 0.192 33.672 ;
    END
  END i[303]
  PIN i[304]
    DIRECTION INPUT ;
    USE SIGNAL ;
    PORT
      LAYER M4 ;
        RECT  0 33.792 0.192 33.816 ;
    END
  END i[304]
  PIN i[305]
    DIRECTION INPUT ;
    USE SIGNAL ;
    PORT
      LAYER M4 ;
        RECT  0 33.888 0.192 33.912 ;
    END
  END i[305]
  PIN i[306]
    DIRECTION INPUT ;
    USE SIGNAL ;
    PORT
      LAYER M4 ;
        RECT  0 33.984 0.192 34.008 ;
    END
  END i[306]
  PIN i[307]
    DIRECTION INPUT ;
    USE SIGNAL ;
    PORT
      LAYER M4 ;
        RECT  0 34.08 0.192 34.104 ;
    END
  END i[307]
  PIN i[308]
    DIRECTION INPUT ;
    USE SIGNAL ;
    PORT
      LAYER M4 ;
        RECT  0 34.176 0.192 34.2 ;
    END
  END i[308]
  PIN i[309]
    DIRECTION INPUT ;
    USE SIGNAL ;
    PORT
      LAYER M4 ;
        RECT  0 34.272 0.192 34.296 ;
    END
  END i[309]
  PIN i[30]
    DIRECTION INPUT ;
    USE SIGNAL ;
    PORT
      LAYER M4 ;
        RECT  0 5.328 0.192 5.352 ;
    END
  END i[30]
  PIN i[310]
    DIRECTION INPUT ;
    USE SIGNAL ;
    PORT
      LAYER M4 ;
        RECT  0 34.416 0.192 34.44 ;
    END
  END i[310]
  PIN i[311]
    DIRECTION INPUT ;
    USE SIGNAL ;
    PORT
      LAYER M4 ;
        RECT  0 34.512 0.192 34.536 ;
    END
  END i[311]
  PIN i[312]
    DIRECTION INPUT ;
    USE SIGNAL ;
    PORT
      LAYER M4 ;
        RECT  0 34.608 0.192 34.632 ;
    END
  END i[312]
  PIN i[313]
    DIRECTION INPUT ;
    USE SIGNAL ;
    PORT
      LAYER M4 ;
        RECT  0 34.704 0.192 34.728 ;
    END
  END i[313]
  PIN i[314]
    DIRECTION INPUT ;
    USE SIGNAL ;
    PORT
      LAYER M4 ;
        RECT  0 34.8 0.192 34.824 ;
    END
  END i[314]
  PIN i[315]
    DIRECTION INPUT ;
    USE SIGNAL ;
    PORT
      LAYER M4 ;
        RECT  0 34.896 0.192 34.92 ;
    END
  END i[315]
  PIN i[316]
    DIRECTION INPUT ;
    USE SIGNAL ;
    PORT
      LAYER M4 ;
        RECT  0 34.992 0.192 35.016 ;
    END
  END i[316]
  PIN i[317]
    DIRECTION INPUT ;
    USE SIGNAL ;
    PORT
      LAYER M4 ;
        RECT  0 35.136 0.192 35.16 ;
    END
  END i[317]
  PIN i[318]
    DIRECTION INPUT ;
    USE SIGNAL ;
    PORT
      LAYER M4 ;
        RECT  0 35.232 0.192 35.256 ;
    END
  END i[318]
  PIN i[319]
    DIRECTION INPUT ;
    USE SIGNAL ;
    PORT
      LAYER M4 ;
        RECT  0 35.328 0.192 35.352 ;
    END
  END i[319]
  PIN i[31]
    DIRECTION INPUT ;
    USE SIGNAL ;
    PORT
      LAYER M4 ;
        RECT  0 5.424 0.192 5.448 ;
    END
  END i[31]
  PIN i[320]
    DIRECTION INPUT ;
    USE SIGNAL ;
    PORT
      LAYER M4 ;
        RECT  0 35.424 0.192 35.448 ;
    END
  END i[320]
  PIN i[321]
    DIRECTION INPUT ;
    USE SIGNAL ;
    PORT
      LAYER M4 ;
        RECT  0 35.52 0.192 35.544 ;
    END
  END i[321]
  PIN i[322]
    DIRECTION INPUT ;
    USE SIGNAL ;
    PORT
      LAYER M4 ;
        RECT  0 35.616 0.192 35.64 ;
    END
  END i[322]
  PIN i[323]
    DIRECTION INPUT ;
    USE SIGNAL ;
    PORT
      LAYER M4 ;
        RECT  0 35.76 0.192 35.784 ;
    END
  END i[323]
  PIN i[324]
    DIRECTION INPUT ;
    USE SIGNAL ;
    PORT
      LAYER M4 ;
        RECT  0 35.856 0.192 35.88 ;
    END
  END i[324]
  PIN i[325]
    DIRECTION INPUT ;
    USE SIGNAL ;
    PORT
      LAYER M4 ;
        RECT  0 35.952 0.192 35.976 ;
    END
  END i[325]
  PIN i[326]
    DIRECTION INPUT ;
    USE SIGNAL ;
    PORT
      LAYER M4 ;
        RECT  0 36.048 0.192 36.072 ;
    END
  END i[326]
  PIN i[327]
    DIRECTION INPUT ;
    USE SIGNAL ;
    PORT
      LAYER M4 ;
        RECT  0 36.144 0.192 36.168 ;
    END
  END i[327]
  PIN i[328]
    DIRECTION INPUT ;
    USE SIGNAL ;
    PORT
      LAYER M4 ;
        RECT  0 36.24 0.192 36.264 ;
    END
  END i[328]
  PIN i[329]
    DIRECTION INPUT ;
    USE SIGNAL ;
    PORT
      LAYER M4 ;
        RECT  0 36.384 0.192 36.408 ;
    END
  END i[329]
  PIN i[32]
    DIRECTION INPUT ;
    USE SIGNAL ;
    PORT
      LAYER M4 ;
        RECT  0 5.568 0.192 5.592 ;
    END
  END i[32]
  PIN i[330]
    DIRECTION INPUT ;
    USE SIGNAL ;
    PORT
      LAYER M4 ;
        RECT  0 36.48 0.192 36.504 ;
    END
  END i[330]
  PIN i[331]
    DIRECTION INPUT ;
    USE SIGNAL ;
    PORT
      LAYER M4 ;
        RECT  0 36.576 0.192 36.6 ;
    END
  END i[331]
  PIN i[332]
    DIRECTION INPUT ;
    USE SIGNAL ;
    PORT
      LAYER M4 ;
        RECT  0 36.672 0.192 36.696 ;
    END
  END i[332]
  PIN i[333]
    DIRECTION INPUT ;
    USE SIGNAL ;
    PORT
      LAYER M4 ;
        RECT  0 36.768 0.192 36.792 ;
    END
  END i[333]
  PIN i[334]
    DIRECTION INPUT ;
    USE SIGNAL ;
    PORT
      LAYER M4 ;
        RECT  0 36.864 0.192 36.888 ;
    END
  END i[334]
  PIN i[335]
    DIRECTION INPUT ;
    USE SIGNAL ;
    PORT
      LAYER M4 ;
        RECT  0 37.008 0.192 37.032 ;
    END
  END i[335]
  PIN i[336]
    DIRECTION INPUT ;
    USE SIGNAL ;
    PORT
      LAYER M4 ;
        RECT  0 37.104 0.192 37.128 ;
    END
  END i[336]
  PIN i[337]
    DIRECTION INPUT ;
    USE SIGNAL ;
    PORT
      LAYER M4 ;
        RECT  0 37.2 0.192 37.224 ;
    END
  END i[337]
  PIN i[338]
    DIRECTION INPUT ;
    USE SIGNAL ;
    PORT
      LAYER M4 ;
        RECT  0 37.296 0.192 37.32 ;
    END
  END i[338]
  PIN i[339]
    DIRECTION INPUT ;
    USE SIGNAL ;
    PORT
      LAYER M4 ;
        RECT  0 37.392 0.192 37.416 ;
    END
  END i[339]
  PIN i[33]
    DIRECTION INPUT ;
    USE SIGNAL ;
    PORT
      LAYER M4 ;
        RECT  0 5.664 0.192 5.688 ;
    END
  END i[33]
  PIN i[340]
    DIRECTION INPUT ;
    USE SIGNAL ;
    PORT
      LAYER M4 ;
        RECT  0 37.488 0.192 37.512 ;
    END
  END i[340]
  PIN i[341]
    DIRECTION INPUT ;
    USE SIGNAL ;
    PORT
      LAYER M4 ;
        RECT  0 37.632 0.192 37.656 ;
    END
  END i[341]
  PIN i[342]
    DIRECTION INPUT ;
    USE SIGNAL ;
    PORT
      LAYER M4 ;
        RECT  0 37.728 0.192 37.752 ;
    END
  END i[342]
  PIN i[343]
    DIRECTION INPUT ;
    USE SIGNAL ;
    PORT
      LAYER M4 ;
        RECT  0 37.824 0.192 37.848 ;
    END
  END i[343]
  PIN i[344]
    DIRECTION INPUT ;
    USE SIGNAL ;
    PORT
      LAYER M4 ;
        RECT  0 37.92 0.192 37.944 ;
    END
  END i[344]
  PIN i[345]
    DIRECTION INPUT ;
    USE SIGNAL ;
    PORT
      LAYER M4 ;
        RECT  0 38.016 0.192 38.04 ;
    END
  END i[345]
  PIN i[346]
    DIRECTION INPUT ;
    USE SIGNAL ;
    PORT
      LAYER M4 ;
        RECT  0 38.112 0.192 38.136 ;
    END
  END i[346]
  PIN i[347]
    DIRECTION INPUT ;
    USE SIGNAL ;
    PORT
      LAYER M4 ;
        RECT  0 38.256 0.192 38.28 ;
    END
  END i[347]
  PIN i[348]
    DIRECTION INPUT ;
    USE SIGNAL ;
    PORT
      LAYER M4 ;
        RECT  0 38.352 0.192 38.376 ;
    END
  END i[348]
  PIN i[349]
    DIRECTION INPUT ;
    USE SIGNAL ;
    PORT
      LAYER M4 ;
        RECT  0 38.448 0.192 38.472 ;
    END
  END i[349]
  PIN i[34]
    DIRECTION INPUT ;
    USE SIGNAL ;
    PORT
      LAYER M4 ;
        RECT  0 5.76 0.192 5.784 ;
    END
  END i[34]
  PIN i[350]
    DIRECTION INPUT ;
    USE SIGNAL ;
    PORT
      LAYER M4 ;
        RECT  0 38.544 0.192 38.568 ;
    END
  END i[350]
  PIN i[351]
    DIRECTION INPUT ;
    USE SIGNAL ;
    PORT
      LAYER M4 ;
        RECT  0 38.64 0.192 38.664 ;
    END
  END i[351]
  PIN i[352]
    DIRECTION INPUT ;
    USE SIGNAL ;
    PORT
      LAYER M4 ;
        RECT  0 38.736 0.192 38.76 ;
    END
  END i[352]
  PIN i[353]
    DIRECTION INPUT ;
    USE SIGNAL ;
    PORT
      LAYER M4 ;
        RECT  0 38.832 0.192 38.856 ;
    END
  END i[353]
  PIN i[354]
    DIRECTION INPUT ;
    USE SIGNAL ;
    PORT
      LAYER M4 ;
        RECT  0 38.976 0.192 39 ;
    END
  END i[354]
  PIN i[355]
    DIRECTION INPUT ;
    USE SIGNAL ;
    PORT
      LAYER M4 ;
        RECT  0 39.072 0.192 39.096 ;
    END
  END i[355]
  PIN i[356]
    DIRECTION INPUT ;
    USE SIGNAL ;
    PORT
      LAYER M4 ;
        RECT  0 39.168 0.192 39.192 ;
    END
  END i[356]
  PIN i[357]
    DIRECTION INPUT ;
    USE SIGNAL ;
    PORT
      LAYER M4 ;
        RECT  0 39.264 0.192 39.288 ;
    END
  END i[357]
  PIN i[358]
    DIRECTION INPUT ;
    USE SIGNAL ;
    PORT
      LAYER M4 ;
        RECT  0 39.36 0.192 39.384 ;
    END
  END i[358]
  PIN i[359]
    DIRECTION INPUT ;
    USE SIGNAL ;
    PORT
      LAYER M4 ;
        RECT  0 39.456 0.192 39.48 ;
    END
  END i[359]
  PIN i[35]
    DIRECTION INPUT ;
    USE SIGNAL ;
    PORT
      LAYER M4 ;
        RECT  0 5.856 0.192 5.88 ;
    END
  END i[35]
  PIN i[360]
    DIRECTION INPUT ;
    USE SIGNAL ;
    PORT
      LAYER M4 ;
        RECT  0 39.6 0.192 39.624 ;
    END
  END i[360]
  PIN i[361]
    DIRECTION INPUT ;
    USE SIGNAL ;
    PORT
      LAYER M4 ;
        RECT  0 39.696 0.192 39.72 ;
    END
  END i[361]
  PIN i[362]
    DIRECTION INPUT ;
    USE SIGNAL ;
    PORT
      LAYER M4 ;
        RECT  0 39.792 0.192 39.816 ;
    END
  END i[362]
  PIN i[363]
    DIRECTION INPUT ;
    USE SIGNAL ;
    PORT
      LAYER M4 ;
        RECT  0 39.888 0.192 39.912 ;
    END
  END i[363]
  PIN i[364]
    DIRECTION INPUT ;
    USE SIGNAL ;
    PORT
      LAYER M4 ;
        RECT  0 39.984 0.192 40.008 ;
    END
  END i[364]
  PIN i[365]
    DIRECTION INPUT ;
    USE SIGNAL ;
    PORT
      LAYER M4 ;
        RECT  0 40.08 0.192 40.104 ;
    END
  END i[365]
  PIN i[366]
    DIRECTION INPUT ;
    USE SIGNAL ;
    PORT
      LAYER M4 ;
        RECT  0 40.224 0.192 40.248 ;
    END
  END i[366]
  PIN i[367]
    DIRECTION INPUT ;
    USE SIGNAL ;
    PORT
      LAYER M4 ;
        RECT  0 40.32 0.192 40.344 ;
    END
  END i[367]
  PIN i[368]
    DIRECTION INPUT ;
    USE SIGNAL ;
    PORT
      LAYER M4 ;
        RECT  0 40.416 0.192 40.44 ;
    END
  END i[368]
  PIN i[369]
    DIRECTION INPUT ;
    USE SIGNAL ;
    PORT
      LAYER M4 ;
        RECT  0 40.512 0.192 40.536 ;
    END
  END i[369]
  PIN i[36]
    DIRECTION INPUT ;
    USE SIGNAL ;
    PORT
      LAYER M4 ;
        RECT  0 5.952 0.192 5.976 ;
    END
  END i[36]
  PIN i[370]
    DIRECTION INPUT ;
    USE SIGNAL ;
    PORT
      LAYER M4 ;
        RECT  0 40.608 0.192 40.632 ;
    END
  END i[370]
  PIN i[371]
    DIRECTION INPUT ;
    USE SIGNAL ;
    PORT
      LAYER M4 ;
        RECT  0 40.704 0.192 40.728 ;
    END
  END i[371]
  PIN i[372]
    DIRECTION INPUT ;
    USE SIGNAL ;
    PORT
      LAYER M4 ;
        RECT  0 40.848 0.192 40.872 ;
    END
  END i[372]
  PIN i[373]
    DIRECTION INPUT ;
    USE SIGNAL ;
    PORT
      LAYER M4 ;
        RECT  0 40.944 0.192 40.968 ;
    END
  END i[373]
  PIN i[374]
    DIRECTION INPUT ;
    USE SIGNAL ;
    PORT
      LAYER M4 ;
        RECT  0 41.04 0.192 41.064 ;
    END
  END i[374]
  PIN i[375]
    DIRECTION INPUT ;
    USE SIGNAL ;
    PORT
      LAYER M4 ;
        RECT  0 41.136 0.192 41.16 ;
    END
  END i[375]
  PIN i[376]
    DIRECTION INPUT ;
    USE SIGNAL ;
    PORT
      LAYER M4 ;
        RECT  0 41.232 0.192 41.256 ;
    END
  END i[376]
  PIN i[377]
    DIRECTION INPUT ;
    USE SIGNAL ;
    PORT
      LAYER M4 ;
        RECT  0 41.328 0.192 41.352 ;
    END
  END i[377]
  PIN i[378]
    DIRECTION INPUT ;
    USE SIGNAL ;
    PORT
      LAYER M4 ;
        RECT  0 41.472 0.192 41.496 ;
    END
  END i[378]
  PIN i[379]
    DIRECTION INPUT ;
    USE SIGNAL ;
    PORT
      LAYER M4 ;
        RECT  0 41.568 0.192 41.592 ;
    END
  END i[379]
  PIN i[37]
    DIRECTION INPUT ;
    USE SIGNAL ;
    PORT
      LAYER M4 ;
        RECT  0 6.048 0.192 6.072 ;
    END
  END i[37]
  PIN i[380]
    DIRECTION INPUT ;
    USE SIGNAL ;
    PORT
      LAYER M4 ;
        RECT  0 41.664 0.192 41.688 ;
    END
  END i[380]
  PIN i[381]
    DIRECTION INPUT ;
    USE SIGNAL ;
    PORT
      LAYER M4 ;
        RECT  0 41.76 0.192 41.784 ;
    END
  END i[381]
  PIN i[382]
    DIRECTION INPUT ;
    USE SIGNAL ;
    PORT
      LAYER M4 ;
        RECT  0 41.856 0.192 41.88 ;
    END
  END i[382]
  PIN i[383]
    DIRECTION INPUT ;
    USE SIGNAL ;
    PORT
      LAYER M4 ;
        RECT  0 41.952 0.192 41.976 ;
    END
  END i[383]
  PIN i[384]
    DIRECTION INPUT ;
    USE SIGNAL ;
    PORT
      LAYER M4 ;
        RECT  0 42.096 0.192 42.12 ;
    END
  END i[384]
  PIN i[385]
    DIRECTION INPUT ;
    USE SIGNAL ;
    PORT
      LAYER M4 ;
        RECT  0 42.192 0.192 42.216 ;
    END
  END i[385]
  PIN i[386]
    DIRECTION INPUT ;
    USE SIGNAL ;
    PORT
      LAYER M4 ;
        RECT  0 42.288 0.192 42.312 ;
    END
  END i[386]
  PIN i[387]
    DIRECTION INPUT ;
    USE SIGNAL ;
    PORT
      LAYER M4 ;
        RECT  0 42.384 0.192 42.408 ;
    END
  END i[387]
  PIN i[388]
    DIRECTION INPUT ;
    USE SIGNAL ;
    PORT
      LAYER M4 ;
        RECT  0 42.48 0.192 42.504 ;
    END
  END i[388]
  PIN i[389]
    DIRECTION INPUT ;
    USE SIGNAL ;
    PORT
      LAYER M4 ;
        RECT  0 42.576 0.192 42.6 ;
    END
  END i[389]
  PIN i[38]
    DIRECTION INPUT ;
    USE SIGNAL ;
    PORT
      LAYER M4 ;
        RECT  0 6.144 0.192 6.168 ;
    END
  END i[38]
  PIN i[390]
    DIRECTION INPUT ;
    USE SIGNAL ;
    PORT
      LAYER M4 ;
        RECT  0 42.672 0.192 42.696 ;
    END
  END i[390]
  PIN i[391]
    DIRECTION INPUT ;
    USE SIGNAL ;
    PORT
      LAYER M4 ;
        RECT  0 42.816 0.192 42.84 ;
    END
  END i[391]
  PIN i[392]
    DIRECTION INPUT ;
    USE SIGNAL ;
    PORT
      LAYER M4 ;
        RECT  0 42.912 0.192 42.936 ;
    END
  END i[392]
  PIN i[393]
    DIRECTION INPUT ;
    USE SIGNAL ;
    PORT
      LAYER M4 ;
        RECT  0 43.008 0.192 43.032 ;
    END
  END i[393]
  PIN i[394]
    DIRECTION INPUT ;
    USE SIGNAL ;
    PORT
      LAYER M4 ;
        RECT  0 43.104 0.192 43.128 ;
    END
  END i[394]
  PIN i[395]
    DIRECTION INPUT ;
    USE SIGNAL ;
    PORT
      LAYER M4 ;
        RECT  0 43.2 0.192 43.224 ;
    END
  END i[395]
  PIN i[396]
    DIRECTION INPUT ;
    USE SIGNAL ;
    PORT
      LAYER M4 ;
        RECT  0 43.296 0.192 43.32 ;
    END
  END i[396]
  PIN i[397]
    DIRECTION INPUT ;
    USE SIGNAL ;
    PORT
      LAYER M4 ;
        RECT  0 43.44 0.192 43.464 ;
    END
  END i[397]
  PIN i[398]
    DIRECTION INPUT ;
    USE SIGNAL ;
    PORT
      LAYER M4 ;
        RECT  0 43.536 0.192 43.56 ;
    END
  END i[398]
  PIN i[399]
    DIRECTION INPUT ;
    USE SIGNAL ;
    PORT
      LAYER M4 ;
        RECT  0 43.632 0.192 43.656 ;
    END
  END i[399]
  PIN i[39]
    DIRECTION INPUT ;
    USE SIGNAL ;
    PORT
      LAYER M4 ;
        RECT  0 6.288 0.192 6.312 ;
    END
  END i[39]
  PIN i[3]
    DIRECTION INPUT ;
    USE SIGNAL ;
    PORT
      LAYER M4 ;
        RECT  0 2.544 0.192 2.568 ;
    END
  END i[3]
  PIN i[400]
    DIRECTION INPUT ;
    USE SIGNAL ;
    PORT
      LAYER M4 ;
        RECT  0 43.728 0.192 43.752 ;
    END
  END i[400]
  PIN i[401]
    DIRECTION INPUT ;
    USE SIGNAL ;
    PORT
      LAYER M4 ;
        RECT  0 43.824 0.192 43.848 ;
    END
  END i[401]
  PIN i[402]
    DIRECTION INPUT ;
    USE SIGNAL ;
    PORT
      LAYER M4 ;
        RECT  0 43.92 0.192 43.944 ;
    END
  END i[402]
  PIN i[403]
    DIRECTION INPUT ;
    USE SIGNAL ;
    PORT
      LAYER M4 ;
        RECT  0 44.064 0.192 44.088 ;
    END
  END i[403]
  PIN i[404]
    DIRECTION INPUT ;
    USE SIGNAL ;
    PORT
      LAYER M4 ;
        RECT  0 44.16 0.192 44.184 ;
    END
  END i[404]
  PIN i[405]
    DIRECTION INPUT ;
    USE SIGNAL ;
    PORT
      LAYER M4 ;
        RECT  0 44.256 0.192 44.28 ;
    END
  END i[405]
  PIN i[406]
    DIRECTION INPUT ;
    USE SIGNAL ;
    PORT
      LAYER M4 ;
        RECT  0 44.352 0.192 44.376 ;
    END
  END i[406]
  PIN i[407]
    DIRECTION INPUT ;
    USE SIGNAL ;
    PORT
      LAYER M4 ;
        RECT  0 44.448 0.192 44.472 ;
    END
  END i[407]
  PIN i[408]
    DIRECTION INPUT ;
    USE SIGNAL ;
    PORT
      LAYER M4 ;
        RECT  0 44.544 0.192 44.568 ;
    END
  END i[408]
  PIN i[409]
    DIRECTION INPUT ;
    USE SIGNAL ;
    PORT
      LAYER M4 ;
        RECT  0 44.688 0.192 44.712 ;
    END
  END i[409]
  PIN i[40]
    DIRECTION INPUT ;
    USE SIGNAL ;
    PORT
      LAYER M4 ;
        RECT  0 6.384 0.192 6.408 ;
    END
  END i[40]
  PIN i[410]
    DIRECTION INPUT ;
    USE SIGNAL ;
    PORT
      LAYER M4 ;
        RECT  0 44.784 0.192 44.808 ;
    END
  END i[410]
  PIN i[411]
    DIRECTION INPUT ;
    USE SIGNAL ;
    PORT
      LAYER M4 ;
        RECT  0 44.88 0.192 44.904 ;
    END
  END i[411]
  PIN i[412]
    DIRECTION INPUT ;
    USE SIGNAL ;
    PORT
      LAYER M4 ;
        RECT  0 44.976 0.192 45 ;
    END
  END i[412]
  PIN i[413]
    DIRECTION INPUT ;
    USE SIGNAL ;
    PORT
      LAYER M4 ;
        RECT  0 45.072 0.192 45.096 ;
    END
  END i[413]
  PIN i[414]
    DIRECTION INPUT ;
    USE SIGNAL ;
    PORT
      LAYER M4 ;
        RECT  0 45.168 0.192 45.192 ;
    END
  END i[414]
  PIN i[415]
    DIRECTION INPUT ;
    USE SIGNAL ;
    PORT
      LAYER M4 ;
        RECT  0 45.312 0.192 45.336 ;
    END
  END i[415]
  PIN i[416]
    DIRECTION INPUT ;
    USE SIGNAL ;
    PORT
      LAYER M4 ;
        RECT  0 45.408 0.192 45.432 ;
    END
  END i[416]
  PIN i[417]
    DIRECTION INPUT ;
    USE SIGNAL ;
    PORT
      LAYER M4 ;
        RECT  0 45.504 0.192 45.528 ;
    END
  END i[417]
  PIN i[418]
    DIRECTION INPUT ;
    USE SIGNAL ;
    PORT
      LAYER M4 ;
        RECT  0 45.6 0.192 45.624 ;
    END
  END i[418]
  PIN i[419]
    DIRECTION INPUT ;
    USE SIGNAL ;
    PORT
      LAYER M4 ;
        RECT  0 45.696 0.192 45.72 ;
    END
  END i[419]
  PIN i[41]
    DIRECTION INPUT ;
    USE SIGNAL ;
    PORT
      LAYER M4 ;
        RECT  0 6.48 0.192 6.504 ;
    END
  END i[41]
  PIN i[420]
    DIRECTION INPUT ;
    USE SIGNAL ;
    PORT
      LAYER M4 ;
        RECT  0 45.792 0.192 45.816 ;
    END
  END i[420]
  PIN i[421]
    DIRECTION INPUT ;
    USE SIGNAL ;
    PORT
      LAYER M4 ;
        RECT  0 45.936 0.192 45.96 ;
    END
  END i[421]
  PIN i[422]
    DIRECTION INPUT ;
    USE SIGNAL ;
    PORT
      LAYER M4 ;
        RECT  0 46.032 0.192 46.056 ;
    END
  END i[422]
  PIN i[423]
    DIRECTION INPUT ;
    USE SIGNAL ;
    PORT
      LAYER M4 ;
        RECT  0 46.128 0.192 46.152 ;
    END
  END i[423]
  PIN i[424]
    DIRECTION INPUT ;
    USE SIGNAL ;
    PORT
      LAYER M4 ;
        RECT  0 46.224 0.192 46.248 ;
    END
  END i[424]
  PIN i[425]
    DIRECTION INPUT ;
    USE SIGNAL ;
    PORT
      LAYER M4 ;
        RECT  0 46.32 0.192 46.344 ;
    END
  END i[425]
  PIN i[426]
    DIRECTION INPUT ;
    USE SIGNAL ;
    PORT
      LAYER M4 ;
        RECT  0 46.416 0.192 46.44 ;
    END
  END i[426]
  PIN i[427]
    DIRECTION INPUT ;
    USE SIGNAL ;
    PORT
      LAYER M4 ;
        RECT  0 46.512 0.192 46.536 ;
    END
  END i[427]
  PIN i[428]
    DIRECTION INPUT ;
    USE SIGNAL ;
    PORT
      LAYER M4 ;
        RECT  0 46.656 0.192 46.68 ;
    END
  END i[428]
  PIN i[429]
    DIRECTION INPUT ;
    USE SIGNAL ;
    PORT
      LAYER M4 ;
        RECT  0 46.752 0.192 46.776 ;
    END
  END i[429]
  PIN i[42]
    DIRECTION INPUT ;
    USE SIGNAL ;
    PORT
      LAYER M4 ;
        RECT  0 6.576 0.192 6.6 ;
    END
  END i[42]
  PIN i[430]
    DIRECTION INPUT ;
    USE SIGNAL ;
    PORT
      LAYER M4 ;
        RECT  0 46.848 0.192 46.872 ;
    END
  END i[430]
  PIN i[431]
    DIRECTION INPUT ;
    USE SIGNAL ;
    PORT
      LAYER M4 ;
        RECT  0 46.944 0.192 46.968 ;
    END
  END i[431]
  PIN i[432]
    DIRECTION INPUT ;
    USE SIGNAL ;
    PORT
      LAYER M4 ;
        RECT  0 47.04 0.192 47.064 ;
    END
  END i[432]
  PIN i[433]
    DIRECTION INPUT ;
    USE SIGNAL ;
    PORT
      LAYER M4 ;
        RECT  0 47.136 0.192 47.16 ;
    END
  END i[433]
  PIN i[434]
    DIRECTION INPUT ;
    USE SIGNAL ;
    PORT
      LAYER M4 ;
        RECT  0 47.28 0.192 47.304 ;
    END
  END i[434]
  PIN i[435]
    DIRECTION INPUT ;
    USE SIGNAL ;
    PORT
      LAYER M4 ;
        RECT  0 47.376 0.192 47.4 ;
    END
  END i[435]
  PIN i[436]
    DIRECTION INPUT ;
    USE SIGNAL ;
    PORT
      LAYER M4 ;
        RECT  0 47.472 0.192 47.496 ;
    END
  END i[436]
  PIN i[437]
    DIRECTION INPUT ;
    USE SIGNAL ;
    PORT
      LAYER M4 ;
        RECT  0 47.568 0.192 47.592 ;
    END
  END i[437]
  PIN i[438]
    DIRECTION INPUT ;
    USE SIGNAL ;
    PORT
      LAYER M4 ;
        RECT  0 47.664 0.192 47.688 ;
    END
  END i[438]
  PIN i[439]
    DIRECTION INPUT ;
    USE SIGNAL ;
    PORT
      LAYER M4 ;
        RECT  0 47.76 0.192 47.784 ;
    END
  END i[439]
  PIN i[43]
    DIRECTION INPUT ;
    USE SIGNAL ;
    PORT
      LAYER M4 ;
        RECT  0 6.672 0.192 6.696 ;
    END
  END i[43]
  PIN i[440]
    DIRECTION INPUT ;
    USE SIGNAL ;
    PORT
      LAYER M4 ;
        RECT  0 47.904 0.192 47.928 ;
    END
  END i[440]
  PIN i[441]
    DIRECTION INPUT ;
    USE SIGNAL ;
    PORT
      LAYER M4 ;
        RECT  0 48 0.192 48.024 ;
    END
  END i[441]
  PIN i[442]
    DIRECTION INPUT ;
    USE SIGNAL ;
    PORT
      LAYER M4 ;
        RECT  0 48.096 0.192 48.12 ;
    END
  END i[442]
  PIN i[443]
    DIRECTION INPUT ;
    USE SIGNAL ;
    PORT
      LAYER M4 ;
        RECT  0 48.192 0.192 48.216 ;
    END
  END i[443]
  PIN i[444]
    DIRECTION INPUT ;
    USE SIGNAL ;
    PORT
      LAYER M4 ;
        RECT  0 48.288 0.192 48.312 ;
    END
  END i[444]
  PIN i[445]
    DIRECTION INPUT ;
    USE SIGNAL ;
    PORT
      LAYER M4 ;
        RECT  0 48.384 0.192 48.408 ;
    END
  END i[445]
  PIN i[446]
    DIRECTION INPUT ;
    USE SIGNAL ;
    PORT
      LAYER M4 ;
        RECT  0 48.528 0.192 48.552 ;
    END
  END i[446]
  PIN i[447]
    DIRECTION INPUT ;
    USE SIGNAL ;
    PORT
      LAYER M4 ;
        RECT  0 48.624 0.192 48.648 ;
    END
  END i[447]
  PIN i[448]
    DIRECTION INPUT ;
    USE SIGNAL ;
    PORT
      LAYER M4 ;
        RECT  0 48.72 0.192 48.744 ;
    END
  END i[448]
  PIN i[449]
    DIRECTION INPUT ;
    USE SIGNAL ;
    PORT
      LAYER M4 ;
        RECT  0 48.816 0.192 48.84 ;
    END
  END i[449]
  PIN i[44]
    DIRECTION INPUT ;
    USE SIGNAL ;
    PORT
      LAYER M4 ;
        RECT  0 6.768 0.192 6.792 ;
    END
  END i[44]
  PIN i[450]
    DIRECTION INPUT ;
    USE SIGNAL ;
    PORT
      LAYER M4 ;
        RECT  0 48.912 0.192 48.936 ;
    END
  END i[450]
  PIN i[451]
    DIRECTION INPUT ;
    USE SIGNAL ;
    PORT
      LAYER M4 ;
        RECT  0 49.008 0.192 49.032 ;
    END
  END i[451]
  PIN i[452]
    DIRECTION INPUT ;
    USE SIGNAL ;
    PORT
      LAYER M4 ;
        RECT  0 49.152 0.192 49.176 ;
    END
  END i[452]
  PIN i[453]
    DIRECTION INPUT ;
    USE SIGNAL ;
    PORT
      LAYER M4 ;
        RECT  0 49.248 0.192 49.272 ;
    END
  END i[453]
  PIN i[454]
    DIRECTION INPUT ;
    USE SIGNAL ;
    PORT
      LAYER M4 ;
        RECT  0 49.344 0.192 49.368 ;
    END
  END i[454]
  PIN i[455]
    DIRECTION INPUT ;
    USE SIGNAL ;
    PORT
      LAYER M4 ;
        RECT  0 49.44 0.192 49.464 ;
    END
  END i[455]
  PIN i[456]
    DIRECTION INPUT ;
    USE SIGNAL ;
    PORT
      LAYER M4 ;
        RECT  0 49.536 0.192 49.56 ;
    END
  END i[456]
  PIN i[457]
    DIRECTION INPUT ;
    USE SIGNAL ;
    PORT
      LAYER M4 ;
        RECT  0 49.632 0.192 49.656 ;
    END
  END i[457]
  PIN i[458]
    DIRECTION INPUT ;
    USE SIGNAL ;
    PORT
      LAYER M4 ;
        RECT  0 49.728 0.192 49.752 ;
    END
  END i[458]
  PIN i[459]
    DIRECTION INPUT ;
    USE SIGNAL ;
    PORT
      LAYER M4 ;
        RECT  0 49.872 0.192 49.896 ;
    END
  END i[459]
  PIN i[45]
    DIRECTION INPUT ;
    USE SIGNAL ;
    PORT
      LAYER M4 ;
        RECT  0 6.912 0.192 6.936 ;
    END
  END i[45]
  PIN i[460]
    DIRECTION INPUT ;
    USE SIGNAL ;
    PORT
      LAYER M4 ;
        RECT  0 49.968 0.192 49.992 ;
    END
  END i[460]
  PIN i[461]
    DIRECTION INPUT ;
    USE SIGNAL ;
    PORT
      LAYER M4 ;
        RECT  0 50.064 0.192 50.088 ;
    END
  END i[461]
  PIN i[462]
    DIRECTION INPUT ;
    USE SIGNAL ;
    PORT
      LAYER M4 ;
        RECT  0 50.16 0.192 50.184 ;
    END
  END i[462]
  PIN i[463]
    DIRECTION INPUT ;
    USE SIGNAL ;
    PORT
      LAYER M4 ;
        RECT  0 50.256 0.192 50.28 ;
    END
  END i[463]
  PIN i[464]
    DIRECTION INPUT ;
    USE SIGNAL ;
    PORT
      LAYER M4 ;
        RECT  0 50.352 0.192 50.376 ;
    END
  END i[464]
  PIN i[465]
    DIRECTION INPUT ;
    USE SIGNAL ;
    PORT
      LAYER M4 ;
        RECT  0 50.496 0.192 50.52 ;
    END
  END i[465]
  PIN i[466]
    DIRECTION INPUT ;
    USE SIGNAL ;
    PORT
      LAYER M4 ;
        RECT  0 50.592 0.192 50.616 ;
    END
  END i[466]
  PIN i[467]
    DIRECTION INPUT ;
    USE SIGNAL ;
    PORT
      LAYER M4 ;
        RECT  0 50.688 0.192 50.712 ;
    END
  END i[467]
  PIN i[468]
    DIRECTION INPUT ;
    USE SIGNAL ;
    PORT
      LAYER M4 ;
        RECT  0 50.784 0.192 50.808 ;
    END
  END i[468]
  PIN i[469]
    DIRECTION INPUT ;
    USE SIGNAL ;
    PORT
      LAYER M4 ;
        RECT  0 50.88 0.192 50.904 ;
    END
  END i[469]
  PIN i[46]
    DIRECTION INPUT ;
    USE SIGNAL ;
    PORT
      LAYER M4 ;
        RECT  0 7.008 0.192 7.032 ;
    END
  END i[46]
  PIN i[470]
    DIRECTION INPUT ;
    USE SIGNAL ;
    PORT
      LAYER M4 ;
        RECT  0 50.976 0.192 51 ;
    END
  END i[470]
  PIN i[471]
    DIRECTION INPUT ;
    USE SIGNAL ;
    PORT
      LAYER M4 ;
        RECT  0 51.12 0.192 51.144 ;
    END
  END i[471]
  PIN i[472]
    DIRECTION INPUT ;
    USE SIGNAL ;
    PORT
      LAYER M4 ;
        RECT  0 51.216 0.192 51.24 ;
    END
  END i[472]
  PIN i[473]
    DIRECTION INPUT ;
    USE SIGNAL ;
    PORT
      LAYER M4 ;
        RECT  0 51.312 0.192 51.336 ;
    END
  END i[473]
  PIN i[474]
    DIRECTION INPUT ;
    USE SIGNAL ;
    PORT
      LAYER M4 ;
        RECT  0 51.408 0.192 51.432 ;
    END
  END i[474]
  PIN i[475]
    DIRECTION INPUT ;
    USE SIGNAL ;
    PORT
      LAYER M4 ;
        RECT  0 51.504 0.192 51.528 ;
    END
  END i[475]
  PIN i[476]
    DIRECTION INPUT ;
    USE SIGNAL ;
    PORT
      LAYER M4 ;
        RECT  0 51.6 0.192 51.624 ;
    END
  END i[476]
  PIN i[477]
    DIRECTION INPUT ;
    USE SIGNAL ;
    PORT
      LAYER M4 ;
        RECT  0 51.744 0.192 51.768 ;
    END
  END i[477]
  PIN i[478]
    DIRECTION INPUT ;
    USE SIGNAL ;
    PORT
      LAYER M4 ;
        RECT  0 51.84 0.192 51.864 ;
    END
  END i[478]
  PIN i[479]
    DIRECTION INPUT ;
    USE SIGNAL ;
    PORT
      LAYER M4 ;
        RECT  0 51.936 0.192 51.96 ;
    END
  END i[479]
  PIN i[47]
    DIRECTION INPUT ;
    USE SIGNAL ;
    PORT
      LAYER M4 ;
        RECT  0 7.104 0.192 7.128 ;
    END
  END i[47]
  PIN i[480]
    DIRECTION INPUT ;
    USE SIGNAL ;
    PORT
      LAYER M4 ;
        RECT  0 52.032 0.192 52.056 ;
    END
  END i[480]
  PIN i[481]
    DIRECTION INPUT ;
    USE SIGNAL ;
    PORT
      LAYER M4 ;
        RECT  0 52.128 0.192 52.152 ;
    END
  END i[481]
  PIN i[482]
    DIRECTION INPUT ;
    USE SIGNAL ;
    PORT
      LAYER M4 ;
        RECT  0 52.224 0.192 52.248 ;
    END
  END i[482]
  PIN i[483]
    DIRECTION INPUT ;
    USE SIGNAL ;
    PORT
      LAYER M4 ;
        RECT  0 52.368 0.192 52.392 ;
    END
  END i[483]
  PIN i[484]
    DIRECTION INPUT ;
    USE SIGNAL ;
    PORT
      LAYER M4 ;
        RECT  0 52.464 0.192 52.488 ;
    END
  END i[484]
  PIN i[485]
    DIRECTION INPUT ;
    USE SIGNAL ;
    PORT
      LAYER M4 ;
        RECT  0 52.56 0.192 52.584 ;
    END
  END i[485]
  PIN i[486]
    DIRECTION INPUT ;
    USE SIGNAL ;
    PORT
      LAYER M4 ;
        RECT  0 52.656 0.192 52.68 ;
    END
  END i[486]
  PIN i[487]
    DIRECTION INPUT ;
    USE SIGNAL ;
    PORT
      LAYER M4 ;
        RECT  0 52.752 0.192 52.776 ;
    END
  END i[487]
  PIN i[488]
    DIRECTION INPUT ;
    USE SIGNAL ;
    PORT
      LAYER M4 ;
        RECT  0 52.848 0.192 52.872 ;
    END
  END i[488]
  PIN i[489]
    DIRECTION INPUT ;
    USE SIGNAL ;
    PORT
      LAYER M4 ;
        RECT  0 52.992 0.192 53.016 ;
    END
  END i[489]
  PIN i[48]
    DIRECTION INPUT ;
    USE SIGNAL ;
    PORT
      LAYER M4 ;
        RECT  0 7.2 0.192 7.224 ;
    END
  END i[48]
  PIN i[490]
    DIRECTION INPUT ;
    USE SIGNAL ;
    PORT
      LAYER M4 ;
        RECT  0 53.088 0.192 53.112 ;
    END
  END i[490]
  PIN i[491]
    DIRECTION INPUT ;
    USE SIGNAL ;
    PORT
      LAYER M4 ;
        RECT  0 53.184 0.192 53.208 ;
    END
  END i[491]
  PIN i[492]
    DIRECTION INPUT ;
    USE SIGNAL ;
    PORT
      LAYER M4 ;
        RECT  0 53.28 0.192 53.304 ;
    END
  END i[492]
  PIN i[493]
    DIRECTION INPUT ;
    USE SIGNAL ;
    PORT
      LAYER M4 ;
        RECT  0 53.376 0.192 53.4 ;
    END
  END i[493]
  PIN i[494]
    DIRECTION INPUT ;
    USE SIGNAL ;
    PORT
      LAYER M4 ;
        RECT  0 53.472 0.192 53.496 ;
    END
  END i[494]
  PIN i[495]
    DIRECTION INPUT ;
    USE SIGNAL ;
    PORT
      LAYER M4 ;
        RECT  0 53.568 0.192 53.592 ;
    END
  END i[495]
  PIN i[496]
    DIRECTION INPUT ;
    USE SIGNAL ;
    PORT
      LAYER M4 ;
        RECT  0 53.712 0.192 53.736 ;
    END
  END i[496]
  PIN i[497]
    DIRECTION INPUT ;
    USE SIGNAL ;
    PORT
      LAYER M4 ;
        RECT  0 53.808 0.192 53.832 ;
    END
  END i[497]
  PIN i[498]
    DIRECTION INPUT ;
    USE SIGNAL ;
    PORT
      LAYER M4 ;
        RECT  0 53.904 0.192 53.928 ;
    END
  END i[498]
  PIN i[499]
    DIRECTION INPUT ;
    USE SIGNAL ;
    PORT
      LAYER M4 ;
        RECT  0 54 0.192 54.024 ;
    END
  END i[499]
  PIN i[49]
    DIRECTION INPUT ;
    USE SIGNAL ;
    PORT
      LAYER M4 ;
        RECT  0 7.296 0.192 7.32 ;
    END
  END i[49]
  PIN i[4]
    DIRECTION INPUT ;
    USE SIGNAL ;
    PORT
      LAYER M4 ;
        RECT  0 2.64 0.192 2.664 ;
    END
  END i[4]
  PIN i[500]
    DIRECTION INPUT ;
    USE SIGNAL ;
    PORT
      LAYER M4 ;
        RECT  0 54.096 0.192 54.12 ;
    END
  END i[500]
  PIN i[501]
    DIRECTION INPUT ;
    USE SIGNAL ;
    PORT
      LAYER M4 ;
        RECT  0 54.192 0.192 54.216 ;
    END
  END i[501]
  PIN i[502]
    DIRECTION INPUT ;
    USE SIGNAL ;
    PORT
      LAYER M4 ;
        RECT  0 54.336 0.192 54.36 ;
    END
  END i[502]
  PIN i[503]
    DIRECTION INPUT ;
    USE SIGNAL ;
    PORT
      LAYER M4 ;
        RECT  0 54.432 0.192 54.456 ;
    END
  END i[503]
  PIN i[504]
    DIRECTION INPUT ;
    USE SIGNAL ;
    PORT
      LAYER M4 ;
        RECT  0 54.528 0.192 54.552 ;
    END
  END i[504]
  PIN i[505]
    DIRECTION INPUT ;
    USE SIGNAL ;
    PORT
      LAYER M4 ;
        RECT  0 54.624 0.192 54.648 ;
    END
  END i[505]
  PIN i[506]
    DIRECTION INPUT ;
    USE SIGNAL ;
    PORT
      LAYER M4 ;
        RECT  0 54.72 0.192 54.744 ;
    END
  END i[506]
  PIN i[507]
    DIRECTION INPUT ;
    USE SIGNAL ;
    PORT
      LAYER M4 ;
        RECT  0 54.816 0.192 54.84 ;
    END
  END i[507]
  PIN i[508]
    DIRECTION INPUT ;
    USE SIGNAL ;
    PORT
      LAYER M4 ;
        RECT  0 54.96 0.192 54.984 ;
    END
  END i[508]
  PIN i[509]
    DIRECTION INPUT ;
    USE SIGNAL ;
    PORT
      LAYER M4 ;
        RECT  0 55.056 0.192 55.08 ;
    END
  END i[509]
  PIN i[50]
    DIRECTION INPUT ;
    USE SIGNAL ;
    PORT
      LAYER M4 ;
        RECT  0 7.392 0.192 7.416 ;
    END
  END i[50]
  PIN i[510]
    DIRECTION INPUT ;
    USE SIGNAL ;
    PORT
      LAYER M4 ;
        RECT  0 55.152 0.192 55.176 ;
    END
  END i[510]
  PIN i[511]
    DIRECTION INPUT ;
    USE SIGNAL ;
    PORT
      LAYER M4 ;
        RECT  0 55.248 0.192 55.272 ;
    END
  END i[511]
  PIN i[512]
    DIRECTION INPUT ;
    USE SIGNAL ;
    PORT
      LAYER M4 ;
        RECT  0 55.344 0.192 55.368 ;
    END
  END i[512]
  PIN i[513]
    DIRECTION INPUT ;
    USE SIGNAL ;
    PORT
      LAYER M4 ;
        RECT  0 55.44 0.192 55.464 ;
    END
  END i[513]
  PIN i[514]
    DIRECTION INPUT ;
    USE SIGNAL ;
    PORT
      LAYER M4 ;
        RECT  0 55.584 0.192 55.608 ;
    END
  END i[514]
  PIN i[515]
    DIRECTION INPUT ;
    USE SIGNAL ;
    PORT
      LAYER M4 ;
        RECT  0 55.68 0.192 55.704 ;
    END
  END i[515]
  PIN i[516]
    DIRECTION INPUT ;
    USE SIGNAL ;
    PORT
      LAYER M4 ;
        RECT  0 55.776 0.192 55.8 ;
    END
  END i[516]
  PIN i[517]
    DIRECTION INPUT ;
    USE SIGNAL ;
    PORT
      LAYER M4 ;
        RECT  0 55.872 0.192 55.896 ;
    END
  END i[517]
  PIN i[518]
    DIRECTION INPUT ;
    USE SIGNAL ;
    PORT
      LAYER M4 ;
        RECT  0 55.968 0.192 55.992 ;
    END
  END i[518]
  PIN i[519]
    DIRECTION INPUT ;
    USE SIGNAL ;
    PORT
      LAYER M4 ;
        RECT  0 56.064 0.192 56.088 ;
    END
  END i[519]
  PIN i[51]
    DIRECTION INPUT ;
    USE SIGNAL ;
    PORT
      LAYER M4 ;
        RECT  0 7.536 0.192 7.56 ;
    END
  END i[51]
  PIN i[520]
    DIRECTION INPUT ;
    USE SIGNAL ;
    PORT
      LAYER M4 ;
        RECT  0 56.208 0.192 56.232 ;
    END
  END i[520]
  PIN i[521]
    DIRECTION INPUT ;
    USE SIGNAL ;
    PORT
      LAYER M4 ;
        RECT  0 56.304 0.192 56.328 ;
    END
  END i[521]
  PIN i[522]
    DIRECTION INPUT ;
    USE SIGNAL ;
    PORT
      LAYER M4 ;
        RECT  0 56.4 0.192 56.424 ;
    END
  END i[522]
  PIN i[523]
    DIRECTION INPUT ;
    USE SIGNAL ;
    PORT
      LAYER M4 ;
        RECT  0 56.496 0.192 56.52 ;
    END
  END i[523]
  PIN i[524]
    DIRECTION INPUT ;
    USE SIGNAL ;
    PORT
      LAYER M4 ;
        RECT  0 56.592 0.192 56.616 ;
    END
  END i[524]
  PIN i[525]
    DIRECTION INPUT ;
    USE SIGNAL ;
    PORT
      LAYER M4 ;
        RECT  0 56.688 0.192 56.712 ;
    END
  END i[525]
  PIN i[526]
    DIRECTION INPUT ;
    USE SIGNAL ;
    PORT
      LAYER M4 ;
        RECT  0 56.832 0.192 56.856 ;
    END
  END i[526]
  PIN i[527]
    DIRECTION INPUT ;
    USE SIGNAL ;
    PORT
      LAYER M4 ;
        RECT  0 56.928 0.192 56.952 ;
    END
  END i[527]
  PIN i[528]
    DIRECTION INPUT ;
    USE SIGNAL ;
    PORT
      LAYER M4 ;
        RECT  0 57.024 0.192 57.048 ;
    END
  END i[528]
  PIN i[529]
    DIRECTION INPUT ;
    USE SIGNAL ;
    PORT
      LAYER M4 ;
        RECT  0 57.12 0.192 57.144 ;
    END
  END i[529]
  PIN i[52]
    DIRECTION INPUT ;
    USE SIGNAL ;
    PORT
      LAYER M4 ;
        RECT  0 7.632 0.192 7.656 ;
    END
  END i[52]
  PIN i[530]
    DIRECTION INPUT ;
    USE SIGNAL ;
    PORT
      LAYER M4 ;
        RECT  0 57.216 0.192 57.24 ;
    END
  END i[530]
  PIN i[531]
    DIRECTION INPUT ;
    USE SIGNAL ;
    PORT
      LAYER M4 ;
        RECT  0 57.312 0.192 57.336 ;
    END
  END i[531]
  PIN i[532]
    DIRECTION INPUT ;
    USE SIGNAL ;
    PORT
      LAYER M4 ;
        RECT  0 57.408 0.192 57.432 ;
    END
  END i[532]
  PIN i[533]
    DIRECTION INPUT ;
    USE SIGNAL ;
    PORT
      LAYER M4 ;
        RECT  0 57.552 0.192 57.576 ;
    END
  END i[533]
  PIN i[534]
    DIRECTION INPUT ;
    USE SIGNAL ;
    PORT
      LAYER M4 ;
        RECT  0 57.648 0.192 57.672 ;
    END
  END i[534]
  PIN i[535]
    DIRECTION INPUT ;
    USE SIGNAL ;
    PORT
      LAYER M4 ;
        RECT  0 57.744 0.192 57.768 ;
    END
  END i[535]
  PIN i[536]
    DIRECTION INPUT ;
    USE SIGNAL ;
    PORT
      LAYER M4 ;
        RECT  0 57.84 0.192 57.864 ;
    END
  END i[536]
  PIN i[537]
    DIRECTION INPUT ;
    USE SIGNAL ;
    PORT
      LAYER M4 ;
        RECT  0 57.936 0.192 57.96 ;
    END
  END i[537]
  PIN i[538]
    DIRECTION INPUT ;
    USE SIGNAL ;
    PORT
      LAYER M4 ;
        RECT  0 58.032 0.192 58.056 ;
    END
  END i[538]
  PIN i[539]
    DIRECTION INPUT ;
    USE SIGNAL ;
    PORT
      LAYER M4 ;
        RECT  0 58.176 0.192 58.2 ;
    END
  END i[539]
  PIN i[53]
    DIRECTION INPUT ;
    USE SIGNAL ;
    PORT
      LAYER M4 ;
        RECT  0 7.728 0.192 7.752 ;
    END
  END i[53]
  PIN i[540]
    DIRECTION INPUT ;
    USE SIGNAL ;
    PORT
      LAYER M4 ;
        RECT  0 58.272 0.192 58.296 ;
    END
  END i[540]
  PIN i[541]
    DIRECTION INPUT ;
    USE SIGNAL ;
    PORT
      LAYER M4 ;
        RECT  0 58.368 0.192 58.392 ;
    END
  END i[541]
  PIN i[542]
    DIRECTION INPUT ;
    USE SIGNAL ;
    PORT
      LAYER M4 ;
        RECT  0 58.464 0.192 58.488 ;
    END
  END i[542]
  PIN i[543]
    DIRECTION INPUT ;
    USE SIGNAL ;
    PORT
      LAYER M4 ;
        RECT  0 58.56 0.192 58.584 ;
    END
  END i[543]
  PIN i[544]
    DIRECTION INPUT ;
    USE SIGNAL ;
    PORT
      LAYER M4 ;
        RECT  0 58.656 0.192 58.68 ;
    END
  END i[544]
  PIN i[545]
    DIRECTION INPUT ;
    USE SIGNAL ;
    PORT
      LAYER M4 ;
        RECT  0 58.8 0.192 58.824 ;
    END
  END i[545]
  PIN i[546]
    DIRECTION INPUT ;
    USE SIGNAL ;
    PORT
      LAYER M4 ;
        RECT  0 58.896 0.192 58.92 ;
    END
  END i[546]
  PIN i[547]
    DIRECTION INPUT ;
    USE SIGNAL ;
    PORT
      LAYER M4 ;
        RECT  0 58.992 0.192 59.016 ;
    END
  END i[547]
  PIN i[548]
    DIRECTION INPUT ;
    USE SIGNAL ;
    PORT
      LAYER M4 ;
        RECT  0 59.088 0.192 59.112 ;
    END
  END i[548]
  PIN i[549]
    DIRECTION INPUT ;
    USE SIGNAL ;
    PORT
      LAYER M4 ;
        RECT  0 59.184 0.192 59.208 ;
    END
  END i[549]
  PIN i[54]
    DIRECTION INPUT ;
    USE SIGNAL ;
    PORT
      LAYER M4 ;
        RECT  0 7.824 0.192 7.848 ;
    END
  END i[54]
  PIN i[550]
    DIRECTION INPUT ;
    USE SIGNAL ;
    PORT
      LAYER M4 ;
        RECT  0 59.28 0.192 59.304 ;
    END
  END i[550]
  PIN i[551]
    DIRECTION INPUT ;
    USE SIGNAL ;
    PORT
      LAYER M4 ;
        RECT  0 59.424 0.192 59.448 ;
    END
  END i[551]
  PIN i[552]
    DIRECTION INPUT ;
    USE SIGNAL ;
    PORT
      LAYER M4 ;
        RECT  0 59.52 0.192 59.544 ;
    END
  END i[552]
  PIN i[553]
    DIRECTION INPUT ;
    USE SIGNAL ;
    PORT
      LAYER M4 ;
        RECT  0 59.616 0.192 59.64 ;
    END
  END i[553]
  PIN i[554]
    DIRECTION INPUT ;
    USE SIGNAL ;
    PORT
      LAYER M4 ;
        RECT  0 59.712 0.192 59.736 ;
    END
  END i[554]
  PIN i[555]
    DIRECTION INPUT ;
    USE SIGNAL ;
    PORT
      LAYER M4 ;
        RECT  0 59.808 0.192 59.832 ;
    END
  END i[555]
  PIN i[556]
    DIRECTION INPUT ;
    USE SIGNAL ;
    PORT
      LAYER M4 ;
        RECT  0 59.904 0.192 59.928 ;
    END
  END i[556]
  PIN i[557]
    DIRECTION INPUT ;
    USE SIGNAL ;
    PORT
      LAYER M4 ;
        RECT  0 60.048 0.192 60.072 ;
    END
  END i[557]
  PIN i[558]
    DIRECTION INPUT ;
    USE SIGNAL ;
    PORT
      LAYER M4 ;
        RECT  0 60.144 0.192 60.168 ;
    END
  END i[558]
  PIN i[559]
    DIRECTION INPUT ;
    USE SIGNAL ;
    PORT
      LAYER M4 ;
        RECT  0 60.24 0.192 60.264 ;
    END
  END i[559]
  PIN i[55]
    DIRECTION INPUT ;
    USE SIGNAL ;
    PORT
      LAYER M4 ;
        RECT  0 7.92 0.192 7.944 ;
    END
  END i[55]
  PIN i[560]
    DIRECTION INPUT ;
    USE SIGNAL ;
    PORT
      LAYER M4 ;
        RECT  0 60.336 0.192 60.36 ;
    END
  END i[560]
  PIN i[561]
    DIRECTION INPUT ;
    USE SIGNAL ;
    PORT
      LAYER M4 ;
        RECT  0 60.432 0.192 60.456 ;
    END
  END i[561]
  PIN i[56]
    DIRECTION INPUT ;
    USE SIGNAL ;
    PORT
      LAYER M4 ;
        RECT  0 8.016 0.192 8.04 ;
    END
  END i[56]
  PIN i[57]
    DIRECTION INPUT ;
    USE SIGNAL ;
    PORT
      LAYER M4 ;
        RECT  0 8.16 0.192 8.184 ;
    END
  END i[57]
  PIN i[58]
    DIRECTION INPUT ;
    USE SIGNAL ;
    PORT
      LAYER M4 ;
        RECT  0 8.256 0.192 8.28 ;
    END
  END i[58]
  PIN i[59]
    DIRECTION INPUT ;
    USE SIGNAL ;
    PORT
      LAYER M4 ;
        RECT  0 8.352 0.192 8.376 ;
    END
  END i[59]
  PIN i[5]
    DIRECTION INPUT ;
    USE SIGNAL ;
    PORT
      LAYER M4 ;
        RECT  0 2.736 0.192 2.76 ;
    END
  END i[5]
  PIN i[60]
    DIRECTION INPUT ;
    USE SIGNAL ;
    PORT
      LAYER M4 ;
        RECT  0 8.448 0.192 8.472 ;
    END
  END i[60]
  PIN i[61]
    DIRECTION INPUT ;
    USE SIGNAL ;
    PORT
      LAYER M4 ;
        RECT  0 8.544 0.192 8.568 ;
    END
  END i[61]
  PIN i[62]
    DIRECTION INPUT ;
    USE SIGNAL ;
    PORT
      LAYER M4 ;
        RECT  0 8.64 0.192 8.664 ;
    END
  END i[62]
  PIN i[63]
    DIRECTION INPUT ;
    USE SIGNAL ;
    PORT
      LAYER M4 ;
        RECT  0 8.784 0.192 8.808 ;
    END
  END i[63]
  PIN i[64]
    DIRECTION INPUT ;
    USE SIGNAL ;
    PORT
      LAYER M4 ;
        RECT  0 8.88 0.192 8.904 ;
    END
  END i[64]
  PIN i[65]
    DIRECTION INPUT ;
    USE SIGNAL ;
    PORT
      LAYER M4 ;
        RECT  0 8.976 0.192 9 ;
    END
  END i[65]
  PIN i[66]
    DIRECTION INPUT ;
    USE SIGNAL ;
    PORT
      LAYER M4 ;
        RECT  0 9.072 0.192 9.096 ;
    END
  END i[66]
  PIN i[67]
    DIRECTION INPUT ;
    USE SIGNAL ;
    PORT
      LAYER M4 ;
        RECT  0 9.168 0.192 9.192 ;
    END
  END i[67]
  PIN i[68]
    DIRECTION INPUT ;
    USE SIGNAL ;
    PORT
      LAYER M4 ;
        RECT  0 9.264 0.192 9.288 ;
    END
  END i[68]
  PIN i[69]
    DIRECTION INPUT ;
    USE SIGNAL ;
    PORT
      LAYER M4 ;
        RECT  0 9.408 0.192 9.432 ;
    END
  END i[69]
  PIN i[6]
    DIRECTION INPUT ;
    USE SIGNAL ;
    PORT
      LAYER M4 ;
        RECT  0 2.832 0.192 2.856 ;
    END
  END i[6]
  PIN i[70]
    DIRECTION INPUT ;
    USE SIGNAL ;
    PORT
      LAYER M4 ;
        RECT  0 9.504 0.192 9.528 ;
    END
  END i[70]
  PIN i[71]
    DIRECTION INPUT ;
    USE SIGNAL ;
    PORT
      LAYER M4 ;
        RECT  0 9.6 0.192 9.624 ;
    END
  END i[71]
  PIN i[72]
    DIRECTION INPUT ;
    USE SIGNAL ;
    PORT
      LAYER M4 ;
        RECT  0 9.696 0.192 9.72 ;
    END
  END i[72]
  PIN i[73]
    DIRECTION INPUT ;
    USE SIGNAL ;
    PORT
      LAYER M4 ;
        RECT  0 9.792 0.192 9.816 ;
    END
  END i[73]
  PIN i[74]
    DIRECTION INPUT ;
    USE SIGNAL ;
    PORT
      LAYER M4 ;
        RECT  0 9.888 0.192 9.912 ;
    END
  END i[74]
  PIN i[75]
    DIRECTION INPUT ;
    USE SIGNAL ;
    PORT
      LAYER M4 ;
        RECT  0 9.984 0.192 10.008 ;
    END
  END i[75]
  PIN i[76]
    DIRECTION INPUT ;
    USE SIGNAL ;
    PORT
      LAYER M4 ;
        RECT  0 10.128 0.192 10.152 ;
    END
  END i[76]
  PIN i[77]
    DIRECTION INPUT ;
    USE SIGNAL ;
    PORT
      LAYER M4 ;
        RECT  0 10.224 0.192 10.248 ;
    END
  END i[77]
  PIN i[78]
    DIRECTION INPUT ;
    USE SIGNAL ;
    PORT
      LAYER M4 ;
        RECT  0 10.32 0.192 10.344 ;
    END
  END i[78]
  PIN i[79]
    DIRECTION INPUT ;
    USE SIGNAL ;
    PORT
      LAYER M4 ;
        RECT  0 10.416 0.192 10.44 ;
    END
  END i[79]
  PIN i[7]
    DIRECTION INPUT ;
    USE SIGNAL ;
    PORT
      LAYER M4 ;
        RECT  0 2.928 0.192 2.952 ;
    END
  END i[7]
  PIN i[80]
    DIRECTION INPUT ;
    USE SIGNAL ;
    PORT
      LAYER M4 ;
        RECT  0 10.512 0.192 10.536 ;
    END
  END i[80]
  PIN i[81]
    DIRECTION INPUT ;
    USE SIGNAL ;
    PORT
      LAYER M4 ;
        RECT  0 10.608 0.192 10.632 ;
    END
  END i[81]
  PIN i[82]
    DIRECTION INPUT ;
    USE SIGNAL ;
    PORT
      LAYER M4 ;
        RECT  0 10.752 0.192 10.776 ;
    END
  END i[82]
  PIN i[83]
    DIRECTION INPUT ;
    USE SIGNAL ;
    PORT
      LAYER M4 ;
        RECT  0 10.848 0.192 10.872 ;
    END
  END i[83]
  PIN i[84]
    DIRECTION INPUT ;
    USE SIGNAL ;
    PORT
      LAYER M4 ;
        RECT  0 10.944 0.192 10.968 ;
    END
  END i[84]
  PIN i[85]
    DIRECTION INPUT ;
    USE SIGNAL ;
    PORT
      LAYER M4 ;
        RECT  0 11.04 0.192 11.064 ;
    END
  END i[85]
  PIN i[86]
    DIRECTION INPUT ;
    USE SIGNAL ;
    PORT
      LAYER M4 ;
        RECT  0 11.136 0.192 11.16 ;
    END
  END i[86]
  PIN i[87]
    DIRECTION INPUT ;
    USE SIGNAL ;
    PORT
      LAYER M4 ;
        RECT  0 11.232 0.192 11.256 ;
    END
  END i[87]
  PIN i[88]
    DIRECTION INPUT ;
    USE SIGNAL ;
    PORT
      LAYER M4 ;
        RECT  0 11.376 0.192 11.4 ;
    END
  END i[88]
  PIN i[89]
    DIRECTION INPUT ;
    USE SIGNAL ;
    PORT
      LAYER M4 ;
        RECT  0 11.472 0.192 11.496 ;
    END
  END i[89]
  PIN i[8]
    DIRECTION INPUT ;
    USE SIGNAL ;
    PORT
      LAYER M4 ;
        RECT  0 3.072 0.192 3.096 ;
    END
  END i[8]
  PIN i[90]
    DIRECTION INPUT ;
    USE SIGNAL ;
    PORT
      LAYER M4 ;
        RECT  0 11.568 0.192 11.592 ;
    END
  END i[90]
  PIN i[91]
    DIRECTION INPUT ;
    USE SIGNAL ;
    PORT
      LAYER M4 ;
        RECT  0 11.664 0.192 11.688 ;
    END
  END i[91]
  PIN i[92]
    DIRECTION INPUT ;
    USE SIGNAL ;
    PORT
      LAYER M4 ;
        RECT  0 11.76 0.192 11.784 ;
    END
  END i[92]
  PIN i[93]
    DIRECTION INPUT ;
    USE SIGNAL ;
    PORT
      LAYER M4 ;
        RECT  0 11.856 0.192 11.88 ;
    END
  END i[93]
  PIN i[94]
    DIRECTION INPUT ;
    USE SIGNAL ;
    PORT
      LAYER M4 ;
        RECT  0 12 0.192 12.024 ;
    END
  END i[94]
  PIN i[95]
    DIRECTION INPUT ;
    USE SIGNAL ;
    PORT
      LAYER M4 ;
        RECT  0 12.096 0.192 12.12 ;
    END
  END i[95]
  PIN i[96]
    DIRECTION INPUT ;
    USE SIGNAL ;
    PORT
      LAYER M4 ;
        RECT  0 12.192 0.192 12.216 ;
    END
  END i[96]
  PIN i[97]
    DIRECTION INPUT ;
    USE SIGNAL ;
    PORT
      LAYER M4 ;
        RECT  0 12.288 0.192 12.312 ;
    END
  END i[97]
  PIN i[98]
    DIRECTION INPUT ;
    USE SIGNAL ;
    PORT
      LAYER M4 ;
        RECT  0 12.384 0.192 12.408 ;
    END
  END i[98]
  PIN i[99]
    DIRECTION INPUT ;
    USE SIGNAL ;
    PORT
      LAYER M4 ;
        RECT  0 12.48 0.192 12.504 ;
    END
  END i[99]
  PIN i[9]
    DIRECTION INPUT ;
    USE SIGNAL ;
    PORT
      LAYER M4 ;
        RECT  0 3.168 0.192 3.192 ;
    END
  END i[9]
  PIN o[0]
    DIRECTION OUTPUT ;
    USE SIGNAL ;
    PORT
      LAYER M4 ;
        RECT  17.088 2.208 17.28 2.232 ;
    END
  END o[0]
  PIN o[100]
    DIRECTION OUTPUT ;
    USE SIGNAL ;
    PORT
      LAYER M4 ;
        RECT  17.088 12.576 17.28 12.6 ;
    END
  END o[100]
  PIN o[101]
    DIRECTION OUTPUT ;
    USE SIGNAL ;
    PORT
      LAYER M4 ;
        RECT  17.088 12.672 17.28 12.696 ;
    END
  END o[101]
  PIN o[102]
    DIRECTION OUTPUT ;
    USE SIGNAL ;
    PORT
      LAYER M4 ;
        RECT  17.088 12.768 17.28 12.792 ;
    END
  END o[102]
  PIN o[103]
    DIRECTION OUTPUT ;
    USE SIGNAL ;
    PORT
      LAYER M4 ;
        RECT  17.088 12.912 17.28 12.936 ;
    END
  END o[103]
  PIN o[104]
    DIRECTION OUTPUT ;
    USE SIGNAL ;
    PORT
      LAYER M4 ;
        RECT  17.088 13.008 17.28 13.032 ;
    END
  END o[104]
  PIN o[105]
    DIRECTION OUTPUT ;
    USE SIGNAL ;
    PORT
      LAYER M4 ;
        RECT  17.088 13.104 17.28 13.128 ;
    END
  END o[105]
  PIN o[106]
    DIRECTION OUTPUT ;
    USE SIGNAL ;
    PORT
      LAYER M4 ;
        RECT  17.088 13.2 17.28 13.224 ;
    END
  END o[106]
  PIN o[107]
    DIRECTION OUTPUT ;
    USE SIGNAL ;
    PORT
      LAYER M4 ;
        RECT  17.088 13.296 17.28 13.32 ;
    END
  END o[107]
  PIN o[108]
    DIRECTION OUTPUT ;
    USE SIGNAL ;
    PORT
      LAYER M4 ;
        RECT  17.088 13.392 17.28 13.416 ;
    END
  END o[108]
  PIN o[109]
    DIRECTION OUTPUT ;
    USE SIGNAL ;
    PORT
      LAYER M4 ;
        RECT  17.088 13.536 17.28 13.56 ;
    END
  END o[109]
  PIN o[10]
    DIRECTION OUTPUT ;
    USE SIGNAL ;
    PORT
      LAYER M4 ;
        RECT  17.088 3.264 17.28 3.288 ;
    END
  END o[10]
  PIN o[110]
    DIRECTION OUTPUT ;
    USE SIGNAL ;
    PORT
      LAYER M4 ;
        RECT  17.088 13.632 17.28 13.656 ;
    END
  END o[110]
  PIN o[111]
    DIRECTION OUTPUT ;
    USE SIGNAL ;
    PORT
      LAYER M4 ;
        RECT  17.088 13.728 17.28 13.752 ;
    END
  END o[111]
  PIN o[112]
    DIRECTION OUTPUT ;
    USE SIGNAL ;
    PORT
      LAYER M4 ;
        RECT  17.088 13.824 17.28 13.848 ;
    END
  END o[112]
  PIN o[113]
    DIRECTION OUTPUT ;
    USE SIGNAL ;
    PORT
      LAYER M4 ;
        RECT  17.088 13.92 17.28 13.944 ;
    END
  END o[113]
  PIN o[114]
    DIRECTION OUTPUT ;
    USE SIGNAL ;
    PORT
      LAYER M4 ;
        RECT  17.088 14.016 17.28 14.04 ;
    END
  END o[114]
  PIN o[115]
    DIRECTION OUTPUT ;
    USE SIGNAL ;
    PORT
      LAYER M4 ;
        RECT  17.088 14.16 17.28 14.184 ;
    END
  END o[115]
  PIN o[116]
    DIRECTION OUTPUT ;
    USE SIGNAL ;
    PORT
      LAYER M4 ;
        RECT  17.088 14.256 17.28 14.28 ;
    END
  END o[116]
  PIN o[117]
    DIRECTION OUTPUT ;
    USE SIGNAL ;
    PORT
      LAYER M4 ;
        RECT  17.088 14.352 17.28 14.376 ;
    END
  END o[117]
  PIN o[118]
    DIRECTION OUTPUT ;
    USE SIGNAL ;
    PORT
      LAYER M4 ;
        RECT  17.088 14.448 17.28 14.472 ;
    END
  END o[118]
  PIN o[119]
    DIRECTION OUTPUT ;
    USE SIGNAL ;
    PORT
      LAYER M4 ;
        RECT  17.088 14.544 17.28 14.568 ;
    END
  END o[119]
  PIN o[11]
    DIRECTION OUTPUT ;
    USE SIGNAL ;
    PORT
      LAYER M4 ;
        RECT  17.088 3.36 17.28 3.384 ;
    END
  END o[11]
  PIN o[120]
    DIRECTION OUTPUT ;
    USE SIGNAL ;
    PORT
      LAYER M4 ;
        RECT  17.088 14.64 17.28 14.664 ;
    END
  END o[120]
  PIN o[121]
    DIRECTION OUTPUT ;
    USE SIGNAL ;
    PORT
      LAYER M4 ;
        RECT  17.088 14.736 17.28 14.76 ;
    END
  END o[121]
  PIN o[122]
    DIRECTION OUTPUT ;
    USE SIGNAL ;
    PORT
      LAYER M4 ;
        RECT  17.088 14.88 17.28 14.904 ;
    END
  END o[122]
  PIN o[123]
    DIRECTION OUTPUT ;
    USE SIGNAL ;
    PORT
      LAYER M4 ;
        RECT  17.088 14.976 17.28 15 ;
    END
  END o[123]
  PIN o[124]
    DIRECTION OUTPUT ;
    USE SIGNAL ;
    PORT
      LAYER M4 ;
        RECT  17.088 15.072 17.28 15.096 ;
    END
  END o[124]
  PIN o[125]
    DIRECTION OUTPUT ;
    USE SIGNAL ;
    PORT
      LAYER M4 ;
        RECT  17.088 15.168 17.28 15.192 ;
    END
  END o[125]
  PIN o[126]
    DIRECTION OUTPUT ;
    USE SIGNAL ;
    PORT
      LAYER M4 ;
        RECT  17.088 15.264 17.28 15.288 ;
    END
  END o[126]
  PIN o[127]
    DIRECTION OUTPUT ;
    USE SIGNAL ;
    PORT
      LAYER M4 ;
        RECT  17.088 15.36 17.28 15.384 ;
    END
  END o[127]
  PIN o[128]
    DIRECTION OUTPUT ;
    USE SIGNAL ;
    PORT
      LAYER M4 ;
        RECT  17.088 15.504 17.28 15.528 ;
    END
  END o[128]
  PIN o[129]
    DIRECTION OUTPUT ;
    USE SIGNAL ;
    PORT
      LAYER M4 ;
        RECT  17.088 15.6 17.28 15.624 ;
    END
  END o[129]
  PIN o[12]
    DIRECTION OUTPUT ;
    USE SIGNAL ;
    PORT
      LAYER M4 ;
        RECT  17.088 3.456 17.28 3.48 ;
    END
  END o[12]
  PIN o[130]
    DIRECTION OUTPUT ;
    USE SIGNAL ;
    PORT
      LAYER M4 ;
        RECT  17.088 15.696 17.28 15.72 ;
    END
  END o[130]
  PIN o[131]
    DIRECTION OUTPUT ;
    USE SIGNAL ;
    PORT
      LAYER M4 ;
        RECT  17.088 15.792 17.28 15.816 ;
    END
  END o[131]
  PIN o[132]
    DIRECTION OUTPUT ;
    USE SIGNAL ;
    PORT
      LAYER M4 ;
        RECT  17.088 15.888 17.28 15.912 ;
    END
  END o[132]
  PIN o[133]
    DIRECTION OUTPUT ;
    USE SIGNAL ;
    PORT
      LAYER M4 ;
        RECT  17.088 15.984 17.28 16.008 ;
    END
  END o[133]
  PIN o[134]
    DIRECTION OUTPUT ;
    USE SIGNAL ;
    PORT
      LAYER M4 ;
        RECT  17.088 16.128 17.28 16.152 ;
    END
  END o[134]
  PIN o[135]
    DIRECTION OUTPUT ;
    USE SIGNAL ;
    PORT
      LAYER M4 ;
        RECT  17.088 16.224 17.28 16.248 ;
    END
  END o[135]
  PIN o[136]
    DIRECTION OUTPUT ;
    USE SIGNAL ;
    PORT
      LAYER M4 ;
        RECT  17.088 16.32 17.28 16.344 ;
    END
  END o[136]
  PIN o[137]
    DIRECTION OUTPUT ;
    USE SIGNAL ;
    PORT
      LAYER M4 ;
        RECT  17.088 16.416 17.28 16.44 ;
    END
  END o[137]
  PIN o[138]
    DIRECTION OUTPUT ;
    USE SIGNAL ;
    PORT
      LAYER M4 ;
        RECT  17.088 16.512 17.28 16.536 ;
    END
  END o[138]
  PIN o[139]
    DIRECTION OUTPUT ;
    USE SIGNAL ;
    PORT
      LAYER M4 ;
        RECT  17.088 16.608 17.28 16.632 ;
    END
  END o[139]
  PIN o[13]
    DIRECTION OUTPUT ;
    USE SIGNAL ;
    PORT
      LAYER M4 ;
        RECT  17.088 3.552 17.28 3.576 ;
    END
  END o[13]
  PIN o[140]
    DIRECTION OUTPUT ;
    USE SIGNAL ;
    PORT
      LAYER M4 ;
        RECT  17.088 16.704 17.28 16.728 ;
    END
  END o[140]
  PIN o[141]
    DIRECTION OUTPUT ;
    USE SIGNAL ;
    PORT
      LAYER M4 ;
        RECT  17.088 16.848 17.28 16.872 ;
    END
  END o[141]
  PIN o[142]
    DIRECTION OUTPUT ;
    USE SIGNAL ;
    PORT
      LAYER M4 ;
        RECT  17.088 16.944 17.28 16.968 ;
    END
  END o[142]
  PIN o[143]
    DIRECTION OUTPUT ;
    USE SIGNAL ;
    PORT
      LAYER M4 ;
        RECT  17.088 17.04 17.28 17.064 ;
    END
  END o[143]
  PIN o[144]
    DIRECTION OUTPUT ;
    USE SIGNAL ;
    PORT
      LAYER M4 ;
        RECT  17.088 17.136 17.28 17.16 ;
    END
  END o[144]
  PIN o[145]
    DIRECTION OUTPUT ;
    USE SIGNAL ;
    PORT
      LAYER M4 ;
        RECT  17.088 17.232 17.28 17.256 ;
    END
  END o[145]
  PIN o[146]
    DIRECTION OUTPUT ;
    USE SIGNAL ;
    PORT
      LAYER M4 ;
        RECT  17.088 17.328 17.28 17.352 ;
    END
  END o[146]
  PIN o[147]
    DIRECTION OUTPUT ;
    USE SIGNAL ;
    PORT
      LAYER M4 ;
        RECT  17.088 17.472 17.28 17.496 ;
    END
  END o[147]
  PIN o[148]
    DIRECTION OUTPUT ;
    USE SIGNAL ;
    PORT
      LAYER M4 ;
        RECT  17.088 17.568 17.28 17.592 ;
    END
  END o[148]
  PIN o[149]
    DIRECTION OUTPUT ;
    USE SIGNAL ;
    PORT
      LAYER M4 ;
        RECT  17.088 17.664 17.28 17.688 ;
    END
  END o[149]
  PIN o[14]
    DIRECTION OUTPUT ;
    USE SIGNAL ;
    PORT
      LAYER M4 ;
        RECT  17.088 3.696 17.28 3.72 ;
    END
  END o[14]
  PIN o[150]
    DIRECTION OUTPUT ;
    USE SIGNAL ;
    PORT
      LAYER M4 ;
        RECT  17.088 17.76 17.28 17.784 ;
    END
  END o[150]
  PIN o[151]
    DIRECTION OUTPUT ;
    USE SIGNAL ;
    PORT
      LAYER M4 ;
        RECT  17.088 17.856 17.28 17.88 ;
    END
  END o[151]
  PIN o[152]
    DIRECTION OUTPUT ;
    USE SIGNAL ;
    PORT
      LAYER M4 ;
        RECT  17.088 17.952 17.28 17.976 ;
    END
  END o[152]
  PIN o[153]
    DIRECTION OUTPUT ;
    USE SIGNAL ;
    PORT
      LAYER M4 ;
        RECT  17.088 18.096 17.28 18.12 ;
    END
  END o[153]
  PIN o[154]
    DIRECTION OUTPUT ;
    USE SIGNAL ;
    PORT
      LAYER M4 ;
        RECT  17.088 18.192 17.28 18.216 ;
    END
  END o[154]
  PIN o[155]
    DIRECTION OUTPUT ;
    USE SIGNAL ;
    PORT
      LAYER M4 ;
        RECT  17.088 18.288 17.28 18.312 ;
    END
  END o[155]
  PIN o[156]
    DIRECTION OUTPUT ;
    USE SIGNAL ;
    PORT
      LAYER M4 ;
        RECT  17.088 18.384 17.28 18.408 ;
    END
  END o[156]
  PIN o[157]
    DIRECTION OUTPUT ;
    USE SIGNAL ;
    PORT
      LAYER M4 ;
        RECT  17.088 18.48 17.28 18.504 ;
    END
  END o[157]
  PIN o[158]
    DIRECTION OUTPUT ;
    USE SIGNAL ;
    PORT
      LAYER M4 ;
        RECT  17.088 18.576 17.28 18.6 ;
    END
  END o[158]
  PIN o[159]
    DIRECTION OUTPUT ;
    USE SIGNAL ;
    PORT
      LAYER M4 ;
        RECT  17.088 18.672 17.28 18.696 ;
    END
  END o[159]
  PIN o[15]
    DIRECTION OUTPUT ;
    USE SIGNAL ;
    PORT
      LAYER M4 ;
        RECT  17.088 3.792 17.28 3.816 ;
    END
  END o[15]
  PIN o[160]
    DIRECTION OUTPUT ;
    USE SIGNAL ;
    PORT
      LAYER M4 ;
        RECT  17.088 18.816 17.28 18.84 ;
    END
  END o[160]
  PIN o[161]
    DIRECTION OUTPUT ;
    USE SIGNAL ;
    PORT
      LAYER M4 ;
        RECT  17.088 18.912 17.28 18.936 ;
    END
  END o[161]
  PIN o[162]
    DIRECTION OUTPUT ;
    USE SIGNAL ;
    PORT
      LAYER M4 ;
        RECT  17.088 19.008 17.28 19.032 ;
    END
  END o[162]
  PIN o[163]
    DIRECTION OUTPUT ;
    USE SIGNAL ;
    PORT
      LAYER M4 ;
        RECT  17.088 19.104 17.28 19.128 ;
    END
  END o[163]
  PIN o[164]
    DIRECTION OUTPUT ;
    USE SIGNAL ;
    PORT
      LAYER M4 ;
        RECT  17.088 19.2 17.28 19.224 ;
    END
  END o[164]
  PIN o[165]
    DIRECTION OUTPUT ;
    USE SIGNAL ;
    PORT
      LAYER M4 ;
        RECT  17.088 19.296 17.28 19.32 ;
    END
  END o[165]
  PIN o[166]
    DIRECTION OUTPUT ;
    USE SIGNAL ;
    PORT
      LAYER M4 ;
        RECT  17.088 19.44 17.28 19.464 ;
    END
  END o[166]
  PIN o[167]
    DIRECTION OUTPUT ;
    USE SIGNAL ;
    PORT
      LAYER M4 ;
        RECT  17.088 19.536 17.28 19.56 ;
    END
  END o[167]
  PIN o[168]
    DIRECTION OUTPUT ;
    USE SIGNAL ;
    PORT
      LAYER M4 ;
        RECT  17.088 19.632 17.28 19.656 ;
    END
  END o[168]
  PIN o[169]
    DIRECTION OUTPUT ;
    USE SIGNAL ;
    PORT
      LAYER M4 ;
        RECT  17.088 19.728 17.28 19.752 ;
    END
  END o[169]
  PIN o[16]
    DIRECTION OUTPUT ;
    USE SIGNAL ;
    PORT
      LAYER M4 ;
        RECT  17.088 3.888 17.28 3.912 ;
    END
  END o[16]
  PIN o[170]
    DIRECTION OUTPUT ;
    USE SIGNAL ;
    PORT
      LAYER M4 ;
        RECT  17.088 19.824 17.28 19.848 ;
    END
  END o[170]
  PIN o[171]
    DIRECTION OUTPUT ;
    USE SIGNAL ;
    PORT
      LAYER M4 ;
        RECT  17.088 19.92 17.28 19.944 ;
    END
  END o[171]
  PIN o[172]
    DIRECTION OUTPUT ;
    USE SIGNAL ;
    PORT
      LAYER M4 ;
        RECT  17.088 20.064 17.28 20.088 ;
    END
  END o[172]
  PIN o[173]
    DIRECTION OUTPUT ;
    USE SIGNAL ;
    PORT
      LAYER M4 ;
        RECT  17.088 20.16 17.28 20.184 ;
    END
  END o[173]
  PIN o[174]
    DIRECTION OUTPUT ;
    USE SIGNAL ;
    PORT
      LAYER M4 ;
        RECT  17.088 20.256 17.28 20.28 ;
    END
  END o[174]
  PIN o[175]
    DIRECTION OUTPUT ;
    USE SIGNAL ;
    PORT
      LAYER M4 ;
        RECT  17.088 20.352 17.28 20.376 ;
    END
  END o[175]
  PIN o[176]
    DIRECTION OUTPUT ;
    USE SIGNAL ;
    PORT
      LAYER M4 ;
        RECT  17.088 20.448 17.28 20.472 ;
    END
  END o[176]
  PIN o[177]
    DIRECTION OUTPUT ;
    USE SIGNAL ;
    PORT
      LAYER M4 ;
        RECT  17.088 20.544 17.28 20.568 ;
    END
  END o[177]
  PIN o[178]
    DIRECTION OUTPUT ;
    USE SIGNAL ;
    PORT
      LAYER M4 ;
        RECT  17.088 20.64 17.28 20.664 ;
    END
  END o[178]
  PIN o[179]
    DIRECTION OUTPUT ;
    USE SIGNAL ;
    PORT
      LAYER M4 ;
        RECT  17.088 20.784 17.28 20.808 ;
    END
  END o[179]
  PIN o[17]
    DIRECTION OUTPUT ;
    USE SIGNAL ;
    PORT
      LAYER M4 ;
        RECT  17.088 3.984 17.28 4.008 ;
    END
  END o[17]
  PIN o[180]
    DIRECTION OUTPUT ;
    USE SIGNAL ;
    PORT
      LAYER M4 ;
        RECT  17.088 20.88 17.28 20.904 ;
    END
  END o[180]
  PIN o[181]
    DIRECTION OUTPUT ;
    USE SIGNAL ;
    PORT
      LAYER M4 ;
        RECT  17.088 20.976 17.28 21 ;
    END
  END o[181]
  PIN o[182]
    DIRECTION OUTPUT ;
    USE SIGNAL ;
    PORT
      LAYER M4 ;
        RECT  17.088 21.072 17.28 21.096 ;
    END
  END o[182]
  PIN o[183]
    DIRECTION OUTPUT ;
    USE SIGNAL ;
    PORT
      LAYER M4 ;
        RECT  17.088 21.168 17.28 21.192 ;
    END
  END o[183]
  PIN o[184]
    DIRECTION OUTPUT ;
    USE SIGNAL ;
    PORT
      LAYER M4 ;
        RECT  17.088 21.264 17.28 21.288 ;
    END
  END o[184]
  PIN o[185]
    DIRECTION OUTPUT ;
    USE SIGNAL ;
    PORT
      LAYER M4 ;
        RECT  17.088 21.408 17.28 21.432 ;
    END
  END o[185]
  PIN o[186]
    DIRECTION OUTPUT ;
    USE SIGNAL ;
    PORT
      LAYER M4 ;
        RECT  17.088 21.504 17.28 21.528 ;
    END
  END o[186]
  PIN o[187]
    DIRECTION OUTPUT ;
    USE SIGNAL ;
    PORT
      LAYER M4 ;
        RECT  17.088 21.6 17.28 21.624 ;
    END
  END o[187]
  PIN o[188]
    DIRECTION OUTPUT ;
    USE SIGNAL ;
    PORT
      LAYER M4 ;
        RECT  17.088 21.696 17.28 21.72 ;
    END
  END o[188]
  PIN o[189]
    DIRECTION OUTPUT ;
    USE SIGNAL ;
    PORT
      LAYER M4 ;
        RECT  17.088 21.792 17.28 21.816 ;
    END
  END o[189]
  PIN o[18]
    DIRECTION OUTPUT ;
    USE SIGNAL ;
    PORT
      LAYER M4 ;
        RECT  17.088 4.08 17.28 4.104 ;
    END
  END o[18]
  PIN o[190]
    DIRECTION OUTPUT ;
    USE SIGNAL ;
    PORT
      LAYER M4 ;
        RECT  17.088 21.888 17.28 21.912 ;
    END
  END o[190]
  PIN o[191]
    DIRECTION OUTPUT ;
    USE SIGNAL ;
    PORT
      LAYER M4 ;
        RECT  17.088 22.032 17.28 22.056 ;
    END
  END o[191]
  PIN o[192]
    DIRECTION OUTPUT ;
    USE SIGNAL ;
    PORT
      LAYER M4 ;
        RECT  17.088 22.128 17.28 22.152 ;
    END
  END o[192]
  PIN o[193]
    DIRECTION OUTPUT ;
    USE SIGNAL ;
    PORT
      LAYER M4 ;
        RECT  17.088 22.224 17.28 22.248 ;
    END
  END o[193]
  PIN o[194]
    DIRECTION OUTPUT ;
    USE SIGNAL ;
    PORT
      LAYER M4 ;
        RECT  17.088 22.32 17.28 22.344 ;
    END
  END o[194]
  PIN o[195]
    DIRECTION OUTPUT ;
    USE SIGNAL ;
    PORT
      LAYER M4 ;
        RECT  17.088 22.416 17.28 22.44 ;
    END
  END o[195]
  PIN o[196]
    DIRECTION OUTPUT ;
    USE SIGNAL ;
    PORT
      LAYER M4 ;
        RECT  17.088 22.512 17.28 22.536 ;
    END
  END o[196]
  PIN o[197]
    DIRECTION OUTPUT ;
    USE SIGNAL ;
    PORT
      LAYER M4 ;
        RECT  17.088 22.608 17.28 22.632 ;
    END
  END o[197]
  PIN o[198]
    DIRECTION OUTPUT ;
    USE SIGNAL ;
    PORT
      LAYER M4 ;
        RECT  17.088 22.752 17.28 22.776 ;
    END
  END o[198]
  PIN o[199]
    DIRECTION OUTPUT ;
    USE SIGNAL ;
    PORT
      LAYER M4 ;
        RECT  17.088 22.848 17.28 22.872 ;
    END
  END o[199]
  PIN o[19]
    DIRECTION OUTPUT ;
    USE SIGNAL ;
    PORT
      LAYER M4 ;
        RECT  17.088 4.176 17.28 4.2 ;
    END
  END o[19]
  PIN o[1]
    DIRECTION OUTPUT ;
    USE SIGNAL ;
    PORT
      LAYER M4 ;
        RECT  17.088 2.304 17.28 2.328 ;
    END
  END o[1]
  PIN o[200]
    DIRECTION OUTPUT ;
    USE SIGNAL ;
    PORT
      LAYER M4 ;
        RECT  17.088 22.944 17.28 22.968 ;
    END
  END o[200]
  PIN o[201]
    DIRECTION OUTPUT ;
    USE SIGNAL ;
    PORT
      LAYER M4 ;
        RECT  17.088 23.04 17.28 23.064 ;
    END
  END o[201]
  PIN o[202]
    DIRECTION OUTPUT ;
    USE SIGNAL ;
    PORT
      LAYER M4 ;
        RECT  17.088 23.136 17.28 23.16 ;
    END
  END o[202]
  PIN o[203]
    DIRECTION OUTPUT ;
    USE SIGNAL ;
    PORT
      LAYER M4 ;
        RECT  17.088 23.232 17.28 23.256 ;
    END
  END o[203]
  PIN o[204]
    DIRECTION OUTPUT ;
    USE SIGNAL ;
    PORT
      LAYER M4 ;
        RECT  17.088 23.376 17.28 23.4 ;
    END
  END o[204]
  PIN o[205]
    DIRECTION OUTPUT ;
    USE SIGNAL ;
    PORT
      LAYER M4 ;
        RECT  17.088 23.472 17.28 23.496 ;
    END
  END o[205]
  PIN o[206]
    DIRECTION OUTPUT ;
    USE SIGNAL ;
    PORT
      LAYER M4 ;
        RECT  17.088 23.568 17.28 23.592 ;
    END
  END o[206]
  PIN o[207]
    DIRECTION OUTPUT ;
    USE SIGNAL ;
    PORT
      LAYER M4 ;
        RECT  17.088 23.664 17.28 23.688 ;
    END
  END o[207]
  PIN o[208]
    DIRECTION OUTPUT ;
    USE SIGNAL ;
    PORT
      LAYER M4 ;
        RECT  17.088 23.76 17.28 23.784 ;
    END
  END o[208]
  PIN o[209]
    DIRECTION OUTPUT ;
    USE SIGNAL ;
    PORT
      LAYER M4 ;
        RECT  17.088 23.856 17.28 23.88 ;
    END
  END o[209]
  PIN o[20]
    DIRECTION OUTPUT ;
    USE SIGNAL ;
    PORT
      LAYER M4 ;
        RECT  17.088 4.272 17.28 4.296 ;
    END
  END o[20]
  PIN o[210]
    DIRECTION OUTPUT ;
    USE SIGNAL ;
    PORT
      LAYER M4 ;
        RECT  17.088 24 17.28 24.024 ;
    END
  END o[210]
  PIN o[211]
    DIRECTION OUTPUT ;
    USE SIGNAL ;
    PORT
      LAYER M4 ;
        RECT  17.088 24.096 17.28 24.12 ;
    END
  END o[211]
  PIN o[212]
    DIRECTION OUTPUT ;
    USE SIGNAL ;
    PORT
      LAYER M4 ;
        RECT  17.088 24.192 17.28 24.216 ;
    END
  END o[212]
  PIN o[213]
    DIRECTION OUTPUT ;
    USE SIGNAL ;
    PORT
      LAYER M4 ;
        RECT  17.088 24.288 17.28 24.312 ;
    END
  END o[213]
  PIN o[214]
    DIRECTION OUTPUT ;
    USE SIGNAL ;
    PORT
      LAYER M4 ;
        RECT  17.088 24.384 17.28 24.408 ;
    END
  END o[214]
  PIN o[215]
    DIRECTION OUTPUT ;
    USE SIGNAL ;
    PORT
      LAYER M4 ;
        RECT  17.088 24.48 17.28 24.504 ;
    END
  END o[215]
  PIN o[216]
    DIRECTION OUTPUT ;
    USE SIGNAL ;
    PORT
      LAYER M4 ;
        RECT  17.088 24.576 17.28 24.6 ;
    END
  END o[216]
  PIN o[217]
    DIRECTION OUTPUT ;
    USE SIGNAL ;
    PORT
      LAYER M4 ;
        RECT  17.088 24.72 17.28 24.744 ;
    END
  END o[217]
  PIN o[218]
    DIRECTION OUTPUT ;
    USE SIGNAL ;
    PORT
      LAYER M4 ;
        RECT  17.088 24.816 17.28 24.84 ;
    END
  END o[218]
  PIN o[219]
    DIRECTION OUTPUT ;
    USE SIGNAL ;
    PORT
      LAYER M4 ;
        RECT  17.088 24.912 17.28 24.936 ;
    END
  END o[219]
  PIN o[21]
    DIRECTION OUTPUT ;
    USE SIGNAL ;
    PORT
      LAYER M4 ;
        RECT  17.088 4.416 17.28 4.44 ;
    END
  END o[21]
  PIN o[220]
    DIRECTION OUTPUT ;
    USE SIGNAL ;
    PORT
      LAYER M4 ;
        RECT  17.088 25.008 17.28 25.032 ;
    END
  END o[220]
  PIN o[221]
    DIRECTION OUTPUT ;
    USE SIGNAL ;
    PORT
      LAYER M4 ;
        RECT  17.088 25.104 17.28 25.128 ;
    END
  END o[221]
  PIN o[222]
    DIRECTION OUTPUT ;
    USE SIGNAL ;
    PORT
      LAYER M4 ;
        RECT  17.088 25.2 17.28 25.224 ;
    END
  END o[222]
  PIN o[223]
    DIRECTION OUTPUT ;
    USE SIGNAL ;
    PORT
      LAYER M4 ;
        RECT  17.088 25.344 17.28 25.368 ;
    END
  END o[223]
  PIN o[224]
    DIRECTION OUTPUT ;
    USE SIGNAL ;
    PORT
      LAYER M4 ;
        RECT  17.088 25.44 17.28 25.464 ;
    END
  END o[224]
  PIN o[225]
    DIRECTION OUTPUT ;
    USE SIGNAL ;
    PORT
      LAYER M4 ;
        RECT  17.088 25.536 17.28 25.56 ;
    END
  END o[225]
  PIN o[226]
    DIRECTION OUTPUT ;
    USE SIGNAL ;
    PORT
      LAYER M4 ;
        RECT  17.088 25.632 17.28 25.656 ;
    END
  END o[226]
  PIN o[227]
    DIRECTION OUTPUT ;
    USE SIGNAL ;
    PORT
      LAYER M4 ;
        RECT  17.088 25.728 17.28 25.752 ;
    END
  END o[227]
  PIN o[228]
    DIRECTION OUTPUT ;
    USE SIGNAL ;
    PORT
      LAYER M4 ;
        RECT  17.088 25.824 17.28 25.848 ;
    END
  END o[228]
  PIN o[229]
    DIRECTION OUTPUT ;
    USE SIGNAL ;
    PORT
      LAYER M4 ;
        RECT  17.088 25.968 17.28 25.992 ;
    END
  END o[229]
  PIN o[22]
    DIRECTION OUTPUT ;
    USE SIGNAL ;
    PORT
      LAYER M4 ;
        RECT  17.088 4.512 17.28 4.536 ;
    END
  END o[22]
  PIN o[230]
    DIRECTION OUTPUT ;
    USE SIGNAL ;
    PORT
      LAYER M4 ;
        RECT  17.088 26.064 17.28 26.088 ;
    END
  END o[230]
  PIN o[231]
    DIRECTION OUTPUT ;
    USE SIGNAL ;
    PORT
      LAYER M4 ;
        RECT  17.088 26.16 17.28 26.184 ;
    END
  END o[231]
  PIN o[232]
    DIRECTION OUTPUT ;
    USE SIGNAL ;
    PORT
      LAYER M4 ;
        RECT  17.088 26.256 17.28 26.28 ;
    END
  END o[232]
  PIN o[233]
    DIRECTION OUTPUT ;
    USE SIGNAL ;
    PORT
      LAYER M4 ;
        RECT  17.088 26.352 17.28 26.376 ;
    END
  END o[233]
  PIN o[234]
    DIRECTION OUTPUT ;
    USE SIGNAL ;
    PORT
      LAYER M4 ;
        RECT  17.088 26.448 17.28 26.472 ;
    END
  END o[234]
  PIN o[235]
    DIRECTION OUTPUT ;
    USE SIGNAL ;
    PORT
      LAYER M4 ;
        RECT  17.088 26.544 17.28 26.568 ;
    END
  END o[235]
  PIN o[236]
    DIRECTION OUTPUT ;
    USE SIGNAL ;
    PORT
      LAYER M4 ;
        RECT  17.088 26.688 17.28 26.712 ;
    END
  END o[236]
  PIN o[237]
    DIRECTION OUTPUT ;
    USE SIGNAL ;
    PORT
      LAYER M4 ;
        RECT  17.088 26.784 17.28 26.808 ;
    END
  END o[237]
  PIN o[238]
    DIRECTION OUTPUT ;
    USE SIGNAL ;
    PORT
      LAYER M4 ;
        RECT  17.088 26.88 17.28 26.904 ;
    END
  END o[238]
  PIN o[239]
    DIRECTION OUTPUT ;
    USE SIGNAL ;
    PORT
      LAYER M4 ;
        RECT  17.088 26.976 17.28 27 ;
    END
  END o[239]
  PIN o[23]
    DIRECTION OUTPUT ;
    USE SIGNAL ;
    PORT
      LAYER M4 ;
        RECT  17.088 4.608 17.28 4.632 ;
    END
  END o[23]
  PIN o[240]
    DIRECTION OUTPUT ;
    USE SIGNAL ;
    PORT
      LAYER M4 ;
        RECT  17.088 27.072 17.28 27.096 ;
    END
  END o[240]
  PIN o[241]
    DIRECTION OUTPUT ;
    USE SIGNAL ;
    PORT
      LAYER M4 ;
        RECT  17.088 27.168 17.28 27.192 ;
    END
  END o[241]
  PIN o[242]
    DIRECTION OUTPUT ;
    USE SIGNAL ;
    PORT
      LAYER M4 ;
        RECT  17.088 27.312 17.28 27.336 ;
    END
  END o[242]
  PIN o[243]
    DIRECTION OUTPUT ;
    USE SIGNAL ;
    PORT
      LAYER M4 ;
        RECT  17.088 27.408 17.28 27.432 ;
    END
  END o[243]
  PIN o[244]
    DIRECTION OUTPUT ;
    USE SIGNAL ;
    PORT
      LAYER M4 ;
        RECT  17.088 27.504 17.28 27.528 ;
    END
  END o[244]
  PIN o[245]
    DIRECTION OUTPUT ;
    USE SIGNAL ;
    PORT
      LAYER M4 ;
        RECT  17.088 27.6 17.28 27.624 ;
    END
  END o[245]
  PIN o[246]
    DIRECTION OUTPUT ;
    USE SIGNAL ;
    PORT
      LAYER M4 ;
        RECT  17.088 27.696 17.28 27.72 ;
    END
  END o[246]
  PIN o[247]
    DIRECTION OUTPUT ;
    USE SIGNAL ;
    PORT
      LAYER M4 ;
        RECT  17.088 27.792 17.28 27.816 ;
    END
  END o[247]
  PIN o[248]
    DIRECTION OUTPUT ;
    USE SIGNAL ;
    PORT
      LAYER M4 ;
        RECT  17.088 27.936 17.28 27.96 ;
    END
  END o[248]
  PIN o[249]
    DIRECTION OUTPUT ;
    USE SIGNAL ;
    PORT
      LAYER M4 ;
        RECT  17.088 28.032 17.28 28.056 ;
    END
  END o[249]
  PIN o[24]
    DIRECTION OUTPUT ;
    USE SIGNAL ;
    PORT
      LAYER M4 ;
        RECT  17.088 4.704 17.28 4.728 ;
    END
  END o[24]
  PIN o[250]
    DIRECTION OUTPUT ;
    USE SIGNAL ;
    PORT
      LAYER M4 ;
        RECT  17.088 28.128 17.28 28.152 ;
    END
  END o[250]
  PIN o[251]
    DIRECTION OUTPUT ;
    USE SIGNAL ;
    PORT
      LAYER M4 ;
        RECT  17.088 28.224 17.28 28.248 ;
    END
  END o[251]
  PIN o[252]
    DIRECTION OUTPUT ;
    USE SIGNAL ;
    PORT
      LAYER M4 ;
        RECT  17.088 28.32 17.28 28.344 ;
    END
  END o[252]
  PIN o[253]
    DIRECTION OUTPUT ;
    USE SIGNAL ;
    PORT
      LAYER M4 ;
        RECT  17.088 28.416 17.28 28.44 ;
    END
  END o[253]
  PIN o[254]
    DIRECTION OUTPUT ;
    USE SIGNAL ;
    PORT
      LAYER M4 ;
        RECT  17.088 28.512 17.28 28.536 ;
    END
  END o[254]
  PIN o[255]
    DIRECTION OUTPUT ;
    USE SIGNAL ;
    PORT
      LAYER M4 ;
        RECT  17.088 28.656 17.28 28.68 ;
    END
  END o[255]
  PIN o[256]
    DIRECTION OUTPUT ;
    USE SIGNAL ;
    PORT
      LAYER M4 ;
        RECT  17.088 28.752 17.28 28.776 ;
    END
  END o[256]
  PIN o[257]
    DIRECTION OUTPUT ;
    USE SIGNAL ;
    PORT
      LAYER M4 ;
        RECT  17.088 28.848 17.28 28.872 ;
    END
  END o[257]
  PIN o[258]
    DIRECTION OUTPUT ;
    USE SIGNAL ;
    PORT
      LAYER M4 ;
        RECT  17.088 28.944 17.28 28.968 ;
    END
  END o[258]
  PIN o[259]
    DIRECTION OUTPUT ;
    USE SIGNAL ;
    PORT
      LAYER M4 ;
        RECT  17.088 29.04 17.28 29.064 ;
    END
  END o[259]
  PIN o[25]
    DIRECTION OUTPUT ;
    USE SIGNAL ;
    PORT
      LAYER M4 ;
        RECT  17.088 4.8 17.28 4.824 ;
    END
  END o[25]
  PIN o[260]
    DIRECTION OUTPUT ;
    USE SIGNAL ;
    PORT
      LAYER M4 ;
        RECT  17.088 29.136 17.28 29.16 ;
    END
  END o[260]
  PIN o[261]
    DIRECTION OUTPUT ;
    USE SIGNAL ;
    PORT
      LAYER M4 ;
        RECT  17.088 29.28 17.28 29.304 ;
    END
  END o[261]
  PIN o[262]
    DIRECTION OUTPUT ;
    USE SIGNAL ;
    PORT
      LAYER M4 ;
        RECT  17.088 29.376 17.28 29.4 ;
    END
  END o[262]
  PIN o[263]
    DIRECTION OUTPUT ;
    USE SIGNAL ;
    PORT
      LAYER M4 ;
        RECT  17.088 29.472 17.28 29.496 ;
    END
  END o[263]
  PIN o[264]
    DIRECTION OUTPUT ;
    USE SIGNAL ;
    PORT
      LAYER M4 ;
        RECT  17.088 29.568 17.28 29.592 ;
    END
  END o[264]
  PIN o[265]
    DIRECTION OUTPUT ;
    USE SIGNAL ;
    PORT
      LAYER M4 ;
        RECT  17.088 29.664 17.28 29.688 ;
    END
  END o[265]
  PIN o[266]
    DIRECTION OUTPUT ;
    USE SIGNAL ;
    PORT
      LAYER M4 ;
        RECT  17.088 29.76 17.28 29.784 ;
    END
  END o[266]
  PIN o[267]
    DIRECTION OUTPUT ;
    USE SIGNAL ;
    PORT
      LAYER M4 ;
        RECT  17.088 29.904 17.28 29.928 ;
    END
  END o[267]
  PIN o[268]
    DIRECTION OUTPUT ;
    USE SIGNAL ;
    PORT
      LAYER M4 ;
        RECT  17.088 30 17.28 30.024 ;
    END
  END o[268]
  PIN o[269]
    DIRECTION OUTPUT ;
    USE SIGNAL ;
    PORT
      LAYER M4 ;
        RECT  17.088 30.096 17.28 30.12 ;
    END
  END o[269]
  PIN o[26]
    DIRECTION OUTPUT ;
    USE SIGNAL ;
    PORT
      LAYER M4 ;
        RECT  17.088 4.896 17.28 4.92 ;
    END
  END o[26]
  PIN o[270]
    DIRECTION OUTPUT ;
    USE SIGNAL ;
    PORT
      LAYER M4 ;
        RECT  17.088 30.192 17.28 30.216 ;
    END
  END o[270]
  PIN o[271]
    DIRECTION OUTPUT ;
    USE SIGNAL ;
    PORT
      LAYER M4 ;
        RECT  17.088 30.288 17.28 30.312 ;
    END
  END o[271]
  PIN o[272]
    DIRECTION OUTPUT ;
    USE SIGNAL ;
    PORT
      LAYER M4 ;
        RECT  17.088 30.384 17.28 30.408 ;
    END
  END o[272]
  PIN o[273]
    DIRECTION OUTPUT ;
    USE SIGNAL ;
    PORT
      LAYER M4 ;
        RECT  17.088 30.48 17.28 30.504 ;
    END
  END o[273]
  PIN o[274]
    DIRECTION OUTPUT ;
    USE SIGNAL ;
    PORT
      LAYER M4 ;
        RECT  17.088 30.624 17.28 30.648 ;
    END
  END o[274]
  PIN o[275]
    DIRECTION OUTPUT ;
    USE SIGNAL ;
    PORT
      LAYER M4 ;
        RECT  17.088 30.72 17.28 30.744 ;
    END
  END o[275]
  PIN o[276]
    DIRECTION OUTPUT ;
    USE SIGNAL ;
    PORT
      LAYER M4 ;
        RECT  17.088 30.816 17.28 30.84 ;
    END
  END o[276]
  PIN o[277]
    DIRECTION OUTPUT ;
    USE SIGNAL ;
    PORT
      LAYER M4 ;
        RECT  17.088 30.912 17.28 30.936 ;
    END
  END o[277]
  PIN o[278]
    DIRECTION OUTPUT ;
    USE SIGNAL ;
    PORT
      LAYER M4 ;
        RECT  17.088 31.008 17.28 31.032 ;
    END
  END o[278]
  PIN o[279]
    DIRECTION OUTPUT ;
    USE SIGNAL ;
    PORT
      LAYER M4 ;
        RECT  17.088 31.104 17.28 31.128 ;
    END
  END o[279]
  PIN o[27]
    DIRECTION OUTPUT ;
    USE SIGNAL ;
    PORT
      LAYER M4 ;
        RECT  17.088 5.04 17.28 5.064 ;
    END
  END o[27]
  PIN o[280]
    DIRECTION OUTPUT ;
    USE SIGNAL ;
    PORT
      LAYER M4 ;
        RECT  17.088 31.248 17.28 31.272 ;
    END
  END o[280]
  PIN o[281]
    DIRECTION OUTPUT ;
    USE SIGNAL ;
    PORT
      LAYER M4 ;
        RECT  17.088 31.344 17.28 31.368 ;
    END
  END o[281]
  PIN o[282]
    DIRECTION OUTPUT ;
    USE SIGNAL ;
    PORT
      LAYER M4 ;
        RECT  17.088 31.44 17.28 31.464 ;
    END
  END o[282]
  PIN o[283]
    DIRECTION OUTPUT ;
    USE SIGNAL ;
    PORT
      LAYER M4 ;
        RECT  17.088 31.536 17.28 31.56 ;
    END
  END o[283]
  PIN o[284]
    DIRECTION OUTPUT ;
    USE SIGNAL ;
    PORT
      LAYER M4 ;
        RECT  17.088 31.632 17.28 31.656 ;
    END
  END o[284]
  PIN o[285]
    DIRECTION OUTPUT ;
    USE SIGNAL ;
    PORT
      LAYER M4 ;
        RECT  17.088 31.728 17.28 31.752 ;
    END
  END o[285]
  PIN o[286]
    DIRECTION OUTPUT ;
    USE SIGNAL ;
    PORT
      LAYER M4 ;
        RECT  17.088 31.872 17.28 31.896 ;
    END
  END o[286]
  PIN o[287]
    DIRECTION OUTPUT ;
    USE SIGNAL ;
    PORT
      LAYER M4 ;
        RECT  17.088 31.968 17.28 31.992 ;
    END
  END o[287]
  PIN o[288]
    DIRECTION OUTPUT ;
    USE SIGNAL ;
    PORT
      LAYER M4 ;
        RECT  17.088 32.064 17.28 32.088 ;
    END
  END o[288]
  PIN o[289]
    DIRECTION OUTPUT ;
    USE SIGNAL ;
    PORT
      LAYER M4 ;
        RECT  17.088 32.16 17.28 32.184 ;
    END
  END o[289]
  PIN o[28]
    DIRECTION OUTPUT ;
    USE SIGNAL ;
    PORT
      LAYER M4 ;
        RECT  17.088 5.136 17.28 5.16 ;
    END
  END o[28]
  PIN o[290]
    DIRECTION OUTPUT ;
    USE SIGNAL ;
    PORT
      LAYER M4 ;
        RECT  17.088 32.256 17.28 32.28 ;
    END
  END o[290]
  PIN o[291]
    DIRECTION OUTPUT ;
    USE SIGNAL ;
    PORT
      LAYER M4 ;
        RECT  17.088 32.352 17.28 32.376 ;
    END
  END o[291]
  PIN o[292]
    DIRECTION OUTPUT ;
    USE SIGNAL ;
    PORT
      LAYER M4 ;
        RECT  17.088 32.448 17.28 32.472 ;
    END
  END o[292]
  PIN o[293]
    DIRECTION OUTPUT ;
    USE SIGNAL ;
    PORT
      LAYER M4 ;
        RECT  17.088 32.592 17.28 32.616 ;
    END
  END o[293]
  PIN o[294]
    DIRECTION OUTPUT ;
    USE SIGNAL ;
    PORT
      LAYER M4 ;
        RECT  17.088 32.688 17.28 32.712 ;
    END
  END o[294]
  PIN o[295]
    DIRECTION OUTPUT ;
    USE SIGNAL ;
    PORT
      LAYER M4 ;
        RECT  17.088 32.784 17.28 32.808 ;
    END
  END o[295]
  PIN o[296]
    DIRECTION OUTPUT ;
    USE SIGNAL ;
    PORT
      LAYER M4 ;
        RECT  17.088 32.88 17.28 32.904 ;
    END
  END o[296]
  PIN o[297]
    DIRECTION OUTPUT ;
    USE SIGNAL ;
    PORT
      LAYER M4 ;
        RECT  17.088 32.976 17.28 33 ;
    END
  END o[297]
  PIN o[298]
    DIRECTION OUTPUT ;
    USE SIGNAL ;
    PORT
      LAYER M4 ;
        RECT  17.088 33.072 17.28 33.096 ;
    END
  END o[298]
  PIN o[299]
    DIRECTION OUTPUT ;
    USE SIGNAL ;
    PORT
      LAYER M4 ;
        RECT  17.088 33.216 17.28 33.24 ;
    END
  END o[299]
  PIN o[29]
    DIRECTION OUTPUT ;
    USE SIGNAL ;
    PORT
      LAYER M4 ;
        RECT  17.088 5.232 17.28 5.256 ;
    END
  END o[29]
  PIN o[2]
    DIRECTION OUTPUT ;
    USE SIGNAL ;
    PORT
      LAYER M4 ;
        RECT  17.088 2.448 17.28 2.472 ;
    END
  END o[2]
  PIN o[300]
    DIRECTION OUTPUT ;
    USE SIGNAL ;
    PORT
      LAYER M4 ;
        RECT  17.088 33.312 17.28 33.336 ;
    END
  END o[300]
  PIN o[301]
    DIRECTION OUTPUT ;
    USE SIGNAL ;
    PORT
      LAYER M4 ;
        RECT  17.088 33.408 17.28 33.432 ;
    END
  END o[301]
  PIN o[302]
    DIRECTION OUTPUT ;
    USE SIGNAL ;
    PORT
      LAYER M4 ;
        RECT  17.088 33.504 17.28 33.528 ;
    END
  END o[302]
  PIN o[303]
    DIRECTION OUTPUT ;
    USE SIGNAL ;
    PORT
      LAYER M4 ;
        RECT  17.088 33.6 17.28 33.624 ;
    END
  END o[303]
  PIN o[304]
    DIRECTION OUTPUT ;
    USE SIGNAL ;
    PORT
      LAYER M4 ;
        RECT  17.088 33.696 17.28 33.72 ;
    END
  END o[304]
  PIN o[305]
    DIRECTION OUTPUT ;
    USE SIGNAL ;
    PORT
      LAYER M4 ;
        RECT  17.088 33.84 17.28 33.864 ;
    END
  END o[305]
  PIN o[306]
    DIRECTION OUTPUT ;
    USE SIGNAL ;
    PORT
      LAYER M4 ;
        RECT  17.088 33.936 17.28 33.96 ;
    END
  END o[306]
  PIN o[307]
    DIRECTION OUTPUT ;
    USE SIGNAL ;
    PORT
      LAYER M4 ;
        RECT  17.088 34.032 17.28 34.056 ;
    END
  END o[307]
  PIN o[308]
    DIRECTION OUTPUT ;
    USE SIGNAL ;
    PORT
      LAYER M4 ;
        RECT  17.088 34.128 17.28 34.152 ;
    END
  END o[308]
  PIN o[309]
    DIRECTION OUTPUT ;
    USE SIGNAL ;
    PORT
      LAYER M4 ;
        RECT  17.088 34.224 17.28 34.248 ;
    END
  END o[309]
  PIN o[30]
    DIRECTION OUTPUT ;
    USE SIGNAL ;
    PORT
      LAYER M4 ;
        RECT  17.088 5.328 17.28 5.352 ;
    END
  END o[30]
  PIN o[310]
    DIRECTION OUTPUT ;
    USE SIGNAL ;
    PORT
      LAYER M4 ;
        RECT  17.088 34.32 17.28 34.344 ;
    END
  END o[310]
  PIN o[311]
    DIRECTION OUTPUT ;
    USE SIGNAL ;
    PORT
      LAYER M4 ;
        RECT  17.088 34.416 17.28 34.44 ;
    END
  END o[311]
  PIN o[312]
    DIRECTION OUTPUT ;
    USE SIGNAL ;
    PORT
      LAYER M4 ;
        RECT  17.088 34.56 17.28 34.584 ;
    END
  END o[312]
  PIN o[313]
    DIRECTION OUTPUT ;
    USE SIGNAL ;
    PORT
      LAYER M4 ;
        RECT  17.088 34.656 17.28 34.68 ;
    END
  END o[313]
  PIN o[314]
    DIRECTION OUTPUT ;
    USE SIGNAL ;
    PORT
      LAYER M4 ;
        RECT  17.088 34.752 17.28 34.776 ;
    END
  END o[314]
  PIN o[315]
    DIRECTION OUTPUT ;
    USE SIGNAL ;
    PORT
      LAYER M4 ;
        RECT  17.088 34.848 17.28 34.872 ;
    END
  END o[315]
  PIN o[316]
    DIRECTION OUTPUT ;
    USE SIGNAL ;
    PORT
      LAYER M4 ;
        RECT  17.088 34.944 17.28 34.968 ;
    END
  END o[316]
  PIN o[317]
    DIRECTION OUTPUT ;
    USE SIGNAL ;
    PORT
      LAYER M4 ;
        RECT  17.088 35.04 17.28 35.064 ;
    END
  END o[317]
  PIN o[318]
    DIRECTION OUTPUT ;
    USE SIGNAL ;
    PORT
      LAYER M4 ;
        RECT  17.088 35.184 17.28 35.208 ;
    END
  END o[318]
  PIN o[319]
    DIRECTION OUTPUT ;
    USE SIGNAL ;
    PORT
      LAYER M4 ;
        RECT  17.088 35.28 17.28 35.304 ;
    END
  END o[319]
  PIN o[31]
    DIRECTION OUTPUT ;
    USE SIGNAL ;
    PORT
      LAYER M4 ;
        RECT  17.088 5.424 17.28 5.448 ;
    END
  END o[31]
  PIN o[320]
    DIRECTION OUTPUT ;
    USE SIGNAL ;
    PORT
      LAYER M4 ;
        RECT  17.088 35.376 17.28 35.4 ;
    END
  END o[320]
  PIN o[321]
    DIRECTION OUTPUT ;
    USE SIGNAL ;
    PORT
      LAYER M4 ;
        RECT  17.088 35.472 17.28 35.496 ;
    END
  END o[321]
  PIN o[322]
    DIRECTION OUTPUT ;
    USE SIGNAL ;
    PORT
      LAYER M4 ;
        RECT  17.088 35.568 17.28 35.592 ;
    END
  END o[322]
  PIN o[323]
    DIRECTION OUTPUT ;
    USE SIGNAL ;
    PORT
      LAYER M4 ;
        RECT  17.088 35.664 17.28 35.688 ;
    END
  END o[323]
  PIN o[324]
    DIRECTION OUTPUT ;
    USE SIGNAL ;
    PORT
      LAYER M4 ;
        RECT  17.088 35.808 17.28 35.832 ;
    END
  END o[324]
  PIN o[325]
    DIRECTION OUTPUT ;
    USE SIGNAL ;
    PORT
      LAYER M4 ;
        RECT  17.088 35.904 17.28 35.928 ;
    END
  END o[325]
  PIN o[326]
    DIRECTION OUTPUT ;
    USE SIGNAL ;
    PORT
      LAYER M4 ;
        RECT  17.088 36 17.28 36.024 ;
    END
  END o[326]
  PIN o[327]
    DIRECTION OUTPUT ;
    USE SIGNAL ;
    PORT
      LAYER M4 ;
        RECT  17.088 36.096 17.28 36.12 ;
    END
  END o[327]
  PIN o[328]
    DIRECTION OUTPUT ;
    USE SIGNAL ;
    PORT
      LAYER M4 ;
        RECT  17.088 36.192 17.28 36.216 ;
    END
  END o[328]
  PIN o[329]
    DIRECTION OUTPUT ;
    USE SIGNAL ;
    PORT
      LAYER M4 ;
        RECT  17.088 36.288 17.28 36.312 ;
    END
  END o[329]
  PIN o[32]
    DIRECTION OUTPUT ;
    USE SIGNAL ;
    PORT
      LAYER M4 ;
        RECT  17.088 5.52 17.28 5.544 ;
    END
  END o[32]
  PIN o[330]
    DIRECTION OUTPUT ;
    USE SIGNAL ;
    PORT
      LAYER M4 ;
        RECT  17.088 36.384 17.28 36.408 ;
    END
  END o[330]
  PIN o[331]
    DIRECTION OUTPUT ;
    USE SIGNAL ;
    PORT
      LAYER M4 ;
        RECT  17.088 36.528 17.28 36.552 ;
    END
  END o[331]
  PIN o[332]
    DIRECTION OUTPUT ;
    USE SIGNAL ;
    PORT
      LAYER M4 ;
        RECT  17.088 36.624 17.28 36.648 ;
    END
  END o[332]
  PIN o[333]
    DIRECTION OUTPUT ;
    USE SIGNAL ;
    PORT
      LAYER M4 ;
        RECT  17.088 36.72 17.28 36.744 ;
    END
  END o[333]
  PIN o[334]
    DIRECTION OUTPUT ;
    USE SIGNAL ;
    PORT
      LAYER M4 ;
        RECT  17.088 36.816 17.28 36.84 ;
    END
  END o[334]
  PIN o[335]
    DIRECTION OUTPUT ;
    USE SIGNAL ;
    PORT
      LAYER M4 ;
        RECT  17.088 36.912 17.28 36.936 ;
    END
  END o[335]
  PIN o[336]
    DIRECTION OUTPUT ;
    USE SIGNAL ;
    PORT
      LAYER M4 ;
        RECT  17.088 37.008 17.28 37.032 ;
    END
  END o[336]
  PIN o[337]
    DIRECTION OUTPUT ;
    USE SIGNAL ;
    PORT
      LAYER M4 ;
        RECT  17.088 37.152 17.28 37.176 ;
    END
  END o[337]
  PIN o[338]
    DIRECTION OUTPUT ;
    USE SIGNAL ;
    PORT
      LAYER M4 ;
        RECT  17.088 37.248 17.28 37.272 ;
    END
  END o[338]
  PIN o[339]
    DIRECTION OUTPUT ;
    USE SIGNAL ;
    PORT
      LAYER M4 ;
        RECT  17.088 37.344 17.28 37.368 ;
    END
  END o[339]
  PIN o[33]
    DIRECTION OUTPUT ;
    USE SIGNAL ;
    PORT
      LAYER M4 ;
        RECT  17.088 5.664 17.28 5.688 ;
    END
  END o[33]
  PIN o[340]
    DIRECTION OUTPUT ;
    USE SIGNAL ;
    PORT
      LAYER M4 ;
        RECT  17.088 37.44 17.28 37.464 ;
    END
  END o[340]
  PIN o[341]
    DIRECTION OUTPUT ;
    USE SIGNAL ;
    PORT
      LAYER M4 ;
        RECT  17.088 37.536 17.28 37.56 ;
    END
  END o[341]
  PIN o[342]
    DIRECTION OUTPUT ;
    USE SIGNAL ;
    PORT
      LAYER M4 ;
        RECT  17.088 37.632 17.28 37.656 ;
    END
  END o[342]
  PIN o[343]
    DIRECTION OUTPUT ;
    USE SIGNAL ;
    PORT
      LAYER M4 ;
        RECT  17.088 37.776 17.28 37.8 ;
    END
  END o[343]
  PIN o[344]
    DIRECTION OUTPUT ;
    USE SIGNAL ;
    PORT
      LAYER M4 ;
        RECT  17.088 37.872 17.28 37.896 ;
    END
  END o[344]
  PIN o[345]
    DIRECTION OUTPUT ;
    USE SIGNAL ;
    PORT
      LAYER M4 ;
        RECT  17.088 37.968 17.28 37.992 ;
    END
  END o[345]
  PIN o[346]
    DIRECTION OUTPUT ;
    USE SIGNAL ;
    PORT
      LAYER M4 ;
        RECT  17.088 38.064 17.28 38.088 ;
    END
  END o[346]
  PIN o[347]
    DIRECTION OUTPUT ;
    USE SIGNAL ;
    PORT
      LAYER M4 ;
        RECT  17.088 38.16 17.28 38.184 ;
    END
  END o[347]
  PIN o[348]
    DIRECTION OUTPUT ;
    USE SIGNAL ;
    PORT
      LAYER M4 ;
        RECT  17.088 38.256 17.28 38.28 ;
    END
  END o[348]
  PIN o[349]
    DIRECTION OUTPUT ;
    USE SIGNAL ;
    PORT
      LAYER M4 ;
        RECT  17.088 38.352 17.28 38.376 ;
    END
  END o[349]
  PIN o[34]
    DIRECTION OUTPUT ;
    USE SIGNAL ;
    PORT
      LAYER M4 ;
        RECT  17.088 5.76 17.28 5.784 ;
    END
  END o[34]
  PIN o[350]
    DIRECTION OUTPUT ;
    USE SIGNAL ;
    PORT
      LAYER M4 ;
        RECT  17.088 38.496 17.28 38.52 ;
    END
  END o[350]
  PIN o[351]
    DIRECTION OUTPUT ;
    USE SIGNAL ;
    PORT
      LAYER M4 ;
        RECT  17.088 38.592 17.28 38.616 ;
    END
  END o[351]
  PIN o[352]
    DIRECTION OUTPUT ;
    USE SIGNAL ;
    PORT
      LAYER M4 ;
        RECT  17.088 38.688 17.28 38.712 ;
    END
  END o[352]
  PIN o[353]
    DIRECTION OUTPUT ;
    USE SIGNAL ;
    PORT
      LAYER M4 ;
        RECT  17.088 38.784 17.28 38.808 ;
    END
  END o[353]
  PIN o[354]
    DIRECTION OUTPUT ;
    USE SIGNAL ;
    PORT
      LAYER M4 ;
        RECT  17.088 38.88 17.28 38.904 ;
    END
  END o[354]
  PIN o[355]
    DIRECTION OUTPUT ;
    USE SIGNAL ;
    PORT
      LAYER M4 ;
        RECT  17.088 38.976 17.28 39 ;
    END
  END o[355]
  PIN o[356]
    DIRECTION OUTPUT ;
    USE SIGNAL ;
    PORT
      LAYER M4 ;
        RECT  17.088 39.12 17.28 39.144 ;
    END
  END o[356]
  PIN o[357]
    DIRECTION OUTPUT ;
    USE SIGNAL ;
    PORT
      LAYER M4 ;
        RECT  17.088 39.216 17.28 39.24 ;
    END
  END o[357]
  PIN o[358]
    DIRECTION OUTPUT ;
    USE SIGNAL ;
    PORT
      LAYER M4 ;
        RECT  17.088 39.312 17.28 39.336 ;
    END
  END o[358]
  PIN o[359]
    DIRECTION OUTPUT ;
    USE SIGNAL ;
    PORT
      LAYER M4 ;
        RECT  17.088 39.408 17.28 39.432 ;
    END
  END o[359]
  PIN o[35]
    DIRECTION OUTPUT ;
    USE SIGNAL ;
    PORT
      LAYER M4 ;
        RECT  17.088 5.856 17.28 5.88 ;
    END
  END o[35]
  PIN o[360]
    DIRECTION OUTPUT ;
    USE SIGNAL ;
    PORT
      LAYER M4 ;
        RECT  17.088 39.504 17.28 39.528 ;
    END
  END o[360]
  PIN o[361]
    DIRECTION OUTPUT ;
    USE SIGNAL ;
    PORT
      LAYER M4 ;
        RECT  17.088 39.6 17.28 39.624 ;
    END
  END o[361]
  PIN o[362]
    DIRECTION OUTPUT ;
    USE SIGNAL ;
    PORT
      LAYER M4 ;
        RECT  17.088 39.744 17.28 39.768 ;
    END
  END o[362]
  PIN o[363]
    DIRECTION OUTPUT ;
    USE SIGNAL ;
    PORT
      LAYER M4 ;
        RECT  17.088 39.84 17.28 39.864 ;
    END
  END o[363]
  PIN o[364]
    DIRECTION OUTPUT ;
    USE SIGNAL ;
    PORT
      LAYER M4 ;
        RECT  17.088 39.936 17.28 39.96 ;
    END
  END o[364]
  PIN o[365]
    DIRECTION OUTPUT ;
    USE SIGNAL ;
    PORT
      LAYER M4 ;
        RECT  17.088 40.032 17.28 40.056 ;
    END
  END o[365]
  PIN o[366]
    DIRECTION OUTPUT ;
    USE SIGNAL ;
    PORT
      LAYER M4 ;
        RECT  17.088 40.128 17.28 40.152 ;
    END
  END o[366]
  PIN o[367]
    DIRECTION OUTPUT ;
    USE SIGNAL ;
    PORT
      LAYER M4 ;
        RECT  17.088 40.224 17.28 40.248 ;
    END
  END o[367]
  PIN o[368]
    DIRECTION OUTPUT ;
    USE SIGNAL ;
    PORT
      LAYER M4 ;
        RECT  17.088 40.368 17.28 40.392 ;
    END
  END o[368]
  PIN o[369]
    DIRECTION OUTPUT ;
    USE SIGNAL ;
    PORT
      LAYER M4 ;
        RECT  17.088 40.464 17.28 40.488 ;
    END
  END o[369]
  PIN o[36]
    DIRECTION OUTPUT ;
    USE SIGNAL ;
    PORT
      LAYER M4 ;
        RECT  17.088 5.952 17.28 5.976 ;
    END
  END o[36]
  PIN o[370]
    DIRECTION OUTPUT ;
    USE SIGNAL ;
    PORT
      LAYER M4 ;
        RECT  17.088 40.56 17.28 40.584 ;
    END
  END o[370]
  PIN o[371]
    DIRECTION OUTPUT ;
    USE SIGNAL ;
    PORT
      LAYER M4 ;
        RECT  17.088 40.656 17.28 40.68 ;
    END
  END o[371]
  PIN o[372]
    DIRECTION OUTPUT ;
    USE SIGNAL ;
    PORT
      LAYER M4 ;
        RECT  17.088 40.752 17.28 40.776 ;
    END
  END o[372]
  PIN o[373]
    DIRECTION OUTPUT ;
    USE SIGNAL ;
    PORT
      LAYER M4 ;
        RECT  17.088 40.848 17.28 40.872 ;
    END
  END o[373]
  PIN o[374]
    DIRECTION OUTPUT ;
    USE SIGNAL ;
    PORT
      LAYER M4 ;
        RECT  17.088 40.944 17.28 40.968 ;
    END
  END o[374]
  PIN o[375]
    DIRECTION OUTPUT ;
    USE SIGNAL ;
    PORT
      LAYER M4 ;
        RECT  17.088 41.088 17.28 41.112 ;
    END
  END o[375]
  PIN o[376]
    DIRECTION OUTPUT ;
    USE SIGNAL ;
    PORT
      LAYER M4 ;
        RECT  17.088 41.184 17.28 41.208 ;
    END
  END o[376]
  PIN o[377]
    DIRECTION OUTPUT ;
    USE SIGNAL ;
    PORT
      LAYER M4 ;
        RECT  17.088 41.28 17.28 41.304 ;
    END
  END o[377]
  PIN o[378]
    DIRECTION OUTPUT ;
    USE SIGNAL ;
    PORT
      LAYER M4 ;
        RECT  17.088 41.376 17.28 41.4 ;
    END
  END o[378]
  PIN o[379]
    DIRECTION OUTPUT ;
    USE SIGNAL ;
    PORT
      LAYER M4 ;
        RECT  17.088 41.472 17.28 41.496 ;
    END
  END o[379]
  PIN o[37]
    DIRECTION OUTPUT ;
    USE SIGNAL ;
    PORT
      LAYER M4 ;
        RECT  17.088 6.048 17.28 6.072 ;
    END
  END o[37]
  PIN o[380]
    DIRECTION OUTPUT ;
    USE SIGNAL ;
    PORT
      LAYER M4 ;
        RECT  17.088 41.568 17.28 41.592 ;
    END
  END o[380]
  PIN o[381]
    DIRECTION OUTPUT ;
    USE SIGNAL ;
    PORT
      LAYER M4 ;
        RECT  17.088 41.712 17.28 41.736 ;
    END
  END o[381]
  PIN o[382]
    DIRECTION OUTPUT ;
    USE SIGNAL ;
    PORT
      LAYER M4 ;
        RECT  17.088 41.808 17.28 41.832 ;
    END
  END o[382]
  PIN o[383]
    DIRECTION OUTPUT ;
    USE SIGNAL ;
    PORT
      LAYER M4 ;
        RECT  17.088 41.904 17.28 41.928 ;
    END
  END o[383]
  PIN o[384]
    DIRECTION OUTPUT ;
    USE SIGNAL ;
    PORT
      LAYER M4 ;
        RECT  17.088 42 17.28 42.024 ;
    END
  END o[384]
  PIN o[385]
    DIRECTION OUTPUT ;
    USE SIGNAL ;
    PORT
      LAYER M4 ;
        RECT  17.088 42.096 17.28 42.12 ;
    END
  END o[385]
  PIN o[386]
    DIRECTION OUTPUT ;
    USE SIGNAL ;
    PORT
      LAYER M4 ;
        RECT  17.088 42.192 17.28 42.216 ;
    END
  END o[386]
  PIN o[387]
    DIRECTION OUTPUT ;
    USE SIGNAL ;
    PORT
      LAYER M4 ;
        RECT  17.088 42.336 17.28 42.36 ;
    END
  END o[387]
  PIN o[388]
    DIRECTION OUTPUT ;
    USE SIGNAL ;
    PORT
      LAYER M4 ;
        RECT  17.088 42.432 17.28 42.456 ;
    END
  END o[388]
  PIN o[389]
    DIRECTION OUTPUT ;
    USE SIGNAL ;
    PORT
      LAYER M4 ;
        RECT  17.088 42.528 17.28 42.552 ;
    END
  END o[389]
  PIN o[38]
    DIRECTION OUTPUT ;
    USE SIGNAL ;
    PORT
      LAYER M4 ;
        RECT  17.088 6.144 17.28 6.168 ;
    END
  END o[38]
  PIN o[390]
    DIRECTION OUTPUT ;
    USE SIGNAL ;
    PORT
      LAYER M4 ;
        RECT  17.088 42.624 17.28 42.648 ;
    END
  END o[390]
  PIN o[391]
    DIRECTION OUTPUT ;
    USE SIGNAL ;
    PORT
      LAYER M4 ;
        RECT  17.088 42.72 17.28 42.744 ;
    END
  END o[391]
  PIN o[392]
    DIRECTION OUTPUT ;
    USE SIGNAL ;
    PORT
      LAYER M4 ;
        RECT  17.088 42.816 17.28 42.84 ;
    END
  END o[392]
  PIN o[393]
    DIRECTION OUTPUT ;
    USE SIGNAL ;
    PORT
      LAYER M4 ;
        RECT  17.088 42.912 17.28 42.936 ;
    END
  END o[393]
  PIN o[394]
    DIRECTION OUTPUT ;
    USE SIGNAL ;
    PORT
      LAYER M4 ;
        RECT  17.088 43.056 17.28 43.08 ;
    END
  END o[394]
  PIN o[395]
    DIRECTION OUTPUT ;
    USE SIGNAL ;
    PORT
      LAYER M4 ;
        RECT  17.088 43.152 17.28 43.176 ;
    END
  END o[395]
  PIN o[396]
    DIRECTION OUTPUT ;
    USE SIGNAL ;
    PORT
      LAYER M4 ;
        RECT  17.088 43.248 17.28 43.272 ;
    END
  END o[396]
  PIN o[397]
    DIRECTION OUTPUT ;
    USE SIGNAL ;
    PORT
      LAYER M4 ;
        RECT  17.088 43.344 17.28 43.368 ;
    END
  END o[397]
  PIN o[398]
    DIRECTION OUTPUT ;
    USE SIGNAL ;
    PORT
      LAYER M4 ;
        RECT  17.088 43.44 17.28 43.464 ;
    END
  END o[398]
  PIN o[399]
    DIRECTION OUTPUT ;
    USE SIGNAL ;
    PORT
      LAYER M4 ;
        RECT  17.088 43.536 17.28 43.56 ;
    END
  END o[399]
  PIN o[39]
    DIRECTION OUTPUT ;
    USE SIGNAL ;
    PORT
      LAYER M4 ;
        RECT  17.088 6.24 17.28 6.264 ;
    END
  END o[39]
  PIN o[3]
    DIRECTION OUTPUT ;
    USE SIGNAL ;
    PORT
      LAYER M4 ;
        RECT  17.088 2.544 17.28 2.568 ;
    END
  END o[3]
  PIN o[400]
    DIRECTION OUTPUT ;
    USE SIGNAL ;
    PORT
      LAYER M4 ;
        RECT  17.088 43.68 17.28 43.704 ;
    END
  END o[400]
  PIN o[401]
    DIRECTION OUTPUT ;
    USE SIGNAL ;
    PORT
      LAYER M4 ;
        RECT  17.088 43.776 17.28 43.8 ;
    END
  END o[401]
  PIN o[402]
    DIRECTION OUTPUT ;
    USE SIGNAL ;
    PORT
      LAYER M4 ;
        RECT  17.088 43.872 17.28 43.896 ;
    END
  END o[402]
  PIN o[403]
    DIRECTION OUTPUT ;
    USE SIGNAL ;
    PORT
      LAYER M4 ;
        RECT  17.088 43.968 17.28 43.992 ;
    END
  END o[403]
  PIN o[404]
    DIRECTION OUTPUT ;
    USE SIGNAL ;
    PORT
      LAYER M4 ;
        RECT  17.088 44.064 17.28 44.088 ;
    END
  END o[404]
  PIN o[405]
    DIRECTION OUTPUT ;
    USE SIGNAL ;
    PORT
      LAYER M4 ;
        RECT  17.088 44.16 17.28 44.184 ;
    END
  END o[405]
  PIN o[406]
    DIRECTION OUTPUT ;
    USE SIGNAL ;
    PORT
      LAYER M4 ;
        RECT  17.088 44.304 17.28 44.328 ;
    END
  END o[406]
  PIN o[407]
    DIRECTION OUTPUT ;
    USE SIGNAL ;
    PORT
      LAYER M4 ;
        RECT  17.088 44.4 17.28 44.424 ;
    END
  END o[407]
  PIN o[408]
    DIRECTION OUTPUT ;
    USE SIGNAL ;
    PORT
      LAYER M4 ;
        RECT  17.088 44.496 17.28 44.52 ;
    END
  END o[408]
  PIN o[409]
    DIRECTION OUTPUT ;
    USE SIGNAL ;
    PORT
      LAYER M4 ;
        RECT  17.088 44.592 17.28 44.616 ;
    END
  END o[409]
  PIN o[40]
    DIRECTION OUTPUT ;
    USE SIGNAL ;
    PORT
      LAYER M4 ;
        RECT  17.088 6.384 17.28 6.408 ;
    END
  END o[40]
  PIN o[410]
    DIRECTION OUTPUT ;
    USE SIGNAL ;
    PORT
      LAYER M4 ;
        RECT  17.088 44.688 17.28 44.712 ;
    END
  END o[410]
  PIN o[411]
    DIRECTION OUTPUT ;
    USE SIGNAL ;
    PORT
      LAYER M4 ;
        RECT  17.088 44.784 17.28 44.808 ;
    END
  END o[411]
  PIN o[412]
    DIRECTION OUTPUT ;
    USE SIGNAL ;
    PORT
      LAYER M4 ;
        RECT  17.088 44.88 17.28 44.904 ;
    END
  END o[412]
  PIN o[413]
    DIRECTION OUTPUT ;
    USE SIGNAL ;
    PORT
      LAYER M4 ;
        RECT  17.088 45.024 17.28 45.048 ;
    END
  END o[413]
  PIN o[414]
    DIRECTION OUTPUT ;
    USE SIGNAL ;
    PORT
      LAYER M4 ;
        RECT  17.088 45.12 17.28 45.144 ;
    END
  END o[414]
  PIN o[415]
    DIRECTION OUTPUT ;
    USE SIGNAL ;
    PORT
      LAYER M4 ;
        RECT  17.088 45.216 17.28 45.24 ;
    END
  END o[415]
  PIN o[416]
    DIRECTION OUTPUT ;
    USE SIGNAL ;
    PORT
      LAYER M4 ;
        RECT  17.088 45.312 17.28 45.336 ;
    END
  END o[416]
  PIN o[417]
    DIRECTION OUTPUT ;
    USE SIGNAL ;
    PORT
      LAYER M4 ;
        RECT  17.088 45.408 17.28 45.432 ;
    END
  END o[417]
  PIN o[418]
    DIRECTION OUTPUT ;
    USE SIGNAL ;
    PORT
      LAYER M4 ;
        RECT  17.088 45.504 17.28 45.528 ;
    END
  END o[418]
  PIN o[419]
    DIRECTION OUTPUT ;
    USE SIGNAL ;
    PORT
      LAYER M4 ;
        RECT  17.088 45.648 17.28 45.672 ;
    END
  END o[419]
  PIN o[41]
    DIRECTION OUTPUT ;
    USE SIGNAL ;
    PORT
      LAYER M4 ;
        RECT  17.088 6.48 17.28 6.504 ;
    END
  END o[41]
  PIN o[420]
    DIRECTION OUTPUT ;
    USE SIGNAL ;
    PORT
      LAYER M4 ;
        RECT  17.088 45.744 17.28 45.768 ;
    END
  END o[420]
  PIN o[421]
    DIRECTION OUTPUT ;
    USE SIGNAL ;
    PORT
      LAYER M4 ;
        RECT  17.088 45.84 17.28 45.864 ;
    END
  END o[421]
  PIN o[422]
    DIRECTION OUTPUT ;
    USE SIGNAL ;
    PORT
      LAYER M4 ;
        RECT  17.088 45.936 17.28 45.96 ;
    END
  END o[422]
  PIN o[423]
    DIRECTION OUTPUT ;
    USE SIGNAL ;
    PORT
      LAYER M4 ;
        RECT  17.088 46.032 17.28 46.056 ;
    END
  END o[423]
  PIN o[424]
    DIRECTION OUTPUT ;
    USE SIGNAL ;
    PORT
      LAYER M4 ;
        RECT  17.088 46.128 17.28 46.152 ;
    END
  END o[424]
  PIN o[425]
    DIRECTION OUTPUT ;
    USE SIGNAL ;
    PORT
      LAYER M4 ;
        RECT  17.088 46.272 17.28 46.296 ;
    END
  END o[425]
  PIN o[426]
    DIRECTION OUTPUT ;
    USE SIGNAL ;
    PORT
      LAYER M4 ;
        RECT  17.088 46.368 17.28 46.392 ;
    END
  END o[426]
  PIN o[427]
    DIRECTION OUTPUT ;
    USE SIGNAL ;
    PORT
      LAYER M4 ;
        RECT  17.088 46.464 17.28 46.488 ;
    END
  END o[427]
  PIN o[428]
    DIRECTION OUTPUT ;
    USE SIGNAL ;
    PORT
      LAYER M4 ;
        RECT  17.088 46.56 17.28 46.584 ;
    END
  END o[428]
  PIN o[429]
    DIRECTION OUTPUT ;
    USE SIGNAL ;
    PORT
      LAYER M4 ;
        RECT  17.088 46.656 17.28 46.68 ;
    END
  END o[429]
  PIN o[42]
    DIRECTION OUTPUT ;
    USE SIGNAL ;
    PORT
      LAYER M4 ;
        RECT  17.088 6.576 17.28 6.6 ;
    END
  END o[42]
  PIN o[430]
    DIRECTION OUTPUT ;
    USE SIGNAL ;
    PORT
      LAYER M4 ;
        RECT  17.088 46.752 17.28 46.776 ;
    END
  END o[430]
  PIN o[431]
    DIRECTION OUTPUT ;
    USE SIGNAL ;
    PORT
      LAYER M4 ;
        RECT  17.088 46.848 17.28 46.872 ;
    END
  END o[431]
  PIN o[432]
    DIRECTION OUTPUT ;
    USE SIGNAL ;
    PORT
      LAYER M4 ;
        RECT  17.088 46.992 17.28 47.016 ;
    END
  END o[432]
  PIN o[433]
    DIRECTION OUTPUT ;
    USE SIGNAL ;
    PORT
      LAYER M4 ;
        RECT  17.088 47.088 17.28 47.112 ;
    END
  END o[433]
  PIN o[434]
    DIRECTION OUTPUT ;
    USE SIGNAL ;
    PORT
      LAYER M4 ;
        RECT  17.088 47.184 17.28 47.208 ;
    END
  END o[434]
  PIN o[435]
    DIRECTION OUTPUT ;
    USE SIGNAL ;
    PORT
      LAYER M4 ;
        RECT  17.088 47.28 17.28 47.304 ;
    END
  END o[435]
  PIN o[436]
    DIRECTION OUTPUT ;
    USE SIGNAL ;
    PORT
      LAYER M4 ;
        RECT  17.088 47.376 17.28 47.4 ;
    END
  END o[436]
  PIN o[437]
    DIRECTION OUTPUT ;
    USE SIGNAL ;
    PORT
      LAYER M4 ;
        RECT  17.088 47.472 17.28 47.496 ;
    END
  END o[437]
  PIN o[438]
    DIRECTION OUTPUT ;
    USE SIGNAL ;
    PORT
      LAYER M4 ;
        RECT  17.088 47.616 17.28 47.64 ;
    END
  END o[438]
  PIN o[439]
    DIRECTION OUTPUT ;
    USE SIGNAL ;
    PORT
      LAYER M4 ;
        RECT  17.088 47.712 17.28 47.736 ;
    END
  END o[439]
  PIN o[43]
    DIRECTION OUTPUT ;
    USE SIGNAL ;
    PORT
      LAYER M4 ;
        RECT  17.088 6.672 17.28 6.696 ;
    END
  END o[43]
  PIN o[440]
    DIRECTION OUTPUT ;
    USE SIGNAL ;
    PORT
      LAYER M4 ;
        RECT  17.088 47.808 17.28 47.832 ;
    END
  END o[440]
  PIN o[441]
    DIRECTION OUTPUT ;
    USE SIGNAL ;
    PORT
      LAYER M4 ;
        RECT  17.088 47.904 17.28 47.928 ;
    END
  END o[441]
  PIN o[442]
    DIRECTION OUTPUT ;
    USE SIGNAL ;
    PORT
      LAYER M4 ;
        RECT  17.088 48 17.28 48.024 ;
    END
  END o[442]
  PIN o[443]
    DIRECTION OUTPUT ;
    USE SIGNAL ;
    PORT
      LAYER M4 ;
        RECT  17.088 48.096 17.28 48.12 ;
    END
  END o[443]
  PIN o[444]
    DIRECTION OUTPUT ;
    USE SIGNAL ;
    PORT
      LAYER M4 ;
        RECT  17.088 48.24 17.28 48.264 ;
    END
  END o[444]
  PIN o[445]
    DIRECTION OUTPUT ;
    USE SIGNAL ;
    PORT
      LAYER M4 ;
        RECT  17.088 48.336 17.28 48.36 ;
    END
  END o[445]
  PIN o[446]
    DIRECTION OUTPUT ;
    USE SIGNAL ;
    PORT
      LAYER M4 ;
        RECT  17.088 48.432 17.28 48.456 ;
    END
  END o[446]
  PIN o[447]
    DIRECTION OUTPUT ;
    USE SIGNAL ;
    PORT
      LAYER M4 ;
        RECT  17.088 48.528 17.28 48.552 ;
    END
  END o[447]
  PIN o[448]
    DIRECTION OUTPUT ;
    USE SIGNAL ;
    PORT
      LAYER M4 ;
        RECT  17.088 48.624 17.28 48.648 ;
    END
  END o[448]
  PIN o[449]
    DIRECTION OUTPUT ;
    USE SIGNAL ;
    PORT
      LAYER M4 ;
        RECT  17.088 48.72 17.28 48.744 ;
    END
  END o[449]
  PIN o[44]
    DIRECTION OUTPUT ;
    USE SIGNAL ;
    PORT
      LAYER M4 ;
        RECT  17.088 6.768 17.28 6.792 ;
    END
  END o[44]
  PIN o[450]
    DIRECTION OUTPUT ;
    USE SIGNAL ;
    PORT
      LAYER M4 ;
        RECT  17.088 48.816 17.28 48.84 ;
    END
  END o[450]
  PIN o[451]
    DIRECTION OUTPUT ;
    USE SIGNAL ;
    PORT
      LAYER M4 ;
        RECT  17.088 48.96 17.28 48.984 ;
    END
  END o[451]
  PIN o[452]
    DIRECTION OUTPUT ;
    USE SIGNAL ;
    PORT
      LAYER M4 ;
        RECT  17.088 49.056 17.28 49.08 ;
    END
  END o[452]
  PIN o[453]
    DIRECTION OUTPUT ;
    USE SIGNAL ;
    PORT
      LAYER M4 ;
        RECT  17.088 49.152 17.28 49.176 ;
    END
  END o[453]
  PIN o[454]
    DIRECTION OUTPUT ;
    USE SIGNAL ;
    PORT
      LAYER M4 ;
        RECT  17.088 49.248 17.28 49.272 ;
    END
  END o[454]
  PIN o[455]
    DIRECTION OUTPUT ;
    USE SIGNAL ;
    PORT
      LAYER M4 ;
        RECT  17.088 49.344 17.28 49.368 ;
    END
  END o[455]
  PIN o[456]
    DIRECTION OUTPUT ;
    USE SIGNAL ;
    PORT
      LAYER M4 ;
        RECT  17.088 49.44 17.28 49.464 ;
    END
  END o[456]
  PIN o[457]
    DIRECTION OUTPUT ;
    USE SIGNAL ;
    PORT
      LAYER M4 ;
        RECT  17.088 49.584 17.28 49.608 ;
    END
  END o[457]
  PIN o[458]
    DIRECTION OUTPUT ;
    USE SIGNAL ;
    PORT
      LAYER M4 ;
        RECT  17.088 49.68 17.28 49.704 ;
    END
  END o[458]
  PIN o[459]
    DIRECTION OUTPUT ;
    USE SIGNAL ;
    PORT
      LAYER M4 ;
        RECT  17.088 49.776 17.28 49.8 ;
    END
  END o[459]
  PIN o[45]
    DIRECTION OUTPUT ;
    USE SIGNAL ;
    PORT
      LAYER M4 ;
        RECT  17.088 6.864 17.28 6.888 ;
    END
  END o[45]
  PIN o[460]
    DIRECTION OUTPUT ;
    USE SIGNAL ;
    PORT
      LAYER M4 ;
        RECT  17.088 49.872 17.28 49.896 ;
    END
  END o[460]
  PIN o[461]
    DIRECTION OUTPUT ;
    USE SIGNAL ;
    PORT
      LAYER M4 ;
        RECT  17.088 49.968 17.28 49.992 ;
    END
  END o[461]
  PIN o[462]
    DIRECTION OUTPUT ;
    USE SIGNAL ;
    PORT
      LAYER M4 ;
        RECT  17.088 50.064 17.28 50.088 ;
    END
  END o[462]
  PIN o[463]
    DIRECTION OUTPUT ;
    USE SIGNAL ;
    PORT
      LAYER M4 ;
        RECT  17.088 50.208 17.28 50.232 ;
    END
  END o[463]
  PIN o[464]
    DIRECTION OUTPUT ;
    USE SIGNAL ;
    PORT
      LAYER M4 ;
        RECT  17.088 50.304 17.28 50.328 ;
    END
  END o[464]
  PIN o[465]
    DIRECTION OUTPUT ;
    USE SIGNAL ;
    PORT
      LAYER M4 ;
        RECT  17.088 50.4 17.28 50.424 ;
    END
  END o[465]
  PIN o[466]
    DIRECTION OUTPUT ;
    USE SIGNAL ;
    PORT
      LAYER M4 ;
        RECT  17.088 50.496 17.28 50.52 ;
    END
  END o[466]
  PIN o[467]
    DIRECTION OUTPUT ;
    USE SIGNAL ;
    PORT
      LAYER M4 ;
        RECT  17.088 50.592 17.28 50.616 ;
    END
  END o[467]
  PIN o[468]
    DIRECTION OUTPUT ;
    USE SIGNAL ;
    PORT
      LAYER M4 ;
        RECT  17.088 50.688 17.28 50.712 ;
    END
  END o[468]
  PIN o[469]
    DIRECTION OUTPUT ;
    USE SIGNAL ;
    PORT
      LAYER M4 ;
        RECT  17.088 50.784 17.28 50.808 ;
    END
  END o[469]
  PIN o[46]
    DIRECTION OUTPUT ;
    USE SIGNAL ;
    PORT
      LAYER M4 ;
        RECT  17.088 7.008 17.28 7.032 ;
    END
  END o[46]
  PIN o[470]
    DIRECTION OUTPUT ;
    USE SIGNAL ;
    PORT
      LAYER M4 ;
        RECT  17.088 50.928 17.28 50.952 ;
    END
  END o[470]
  PIN o[471]
    DIRECTION OUTPUT ;
    USE SIGNAL ;
    PORT
      LAYER M4 ;
        RECT  17.088 51.024 17.28 51.048 ;
    END
  END o[471]
  PIN o[472]
    DIRECTION OUTPUT ;
    USE SIGNAL ;
    PORT
      LAYER M4 ;
        RECT  17.088 51.12 17.28 51.144 ;
    END
  END o[472]
  PIN o[473]
    DIRECTION OUTPUT ;
    USE SIGNAL ;
    PORT
      LAYER M4 ;
        RECT  17.088 51.216 17.28 51.24 ;
    END
  END o[473]
  PIN o[474]
    DIRECTION OUTPUT ;
    USE SIGNAL ;
    PORT
      LAYER M4 ;
        RECT  17.088 51.312 17.28 51.336 ;
    END
  END o[474]
  PIN o[475]
    DIRECTION OUTPUT ;
    USE SIGNAL ;
    PORT
      LAYER M4 ;
        RECT  17.088 51.408 17.28 51.432 ;
    END
  END o[475]
  PIN o[476]
    DIRECTION OUTPUT ;
    USE SIGNAL ;
    PORT
      LAYER M4 ;
        RECT  17.088 51.552 17.28 51.576 ;
    END
  END o[476]
  PIN o[477]
    DIRECTION OUTPUT ;
    USE SIGNAL ;
    PORT
      LAYER M4 ;
        RECT  17.088 51.648 17.28 51.672 ;
    END
  END o[477]
  PIN o[478]
    DIRECTION OUTPUT ;
    USE SIGNAL ;
    PORT
      LAYER M4 ;
        RECT  17.088 51.744 17.28 51.768 ;
    END
  END o[478]
  PIN o[479]
    DIRECTION OUTPUT ;
    USE SIGNAL ;
    PORT
      LAYER M4 ;
        RECT  17.088 51.84 17.28 51.864 ;
    END
  END o[479]
  PIN o[47]
    DIRECTION OUTPUT ;
    USE SIGNAL ;
    PORT
      LAYER M4 ;
        RECT  17.088 7.104 17.28 7.128 ;
    END
  END o[47]
  PIN o[480]
    DIRECTION OUTPUT ;
    USE SIGNAL ;
    PORT
      LAYER M4 ;
        RECT  17.088 51.936 17.28 51.96 ;
    END
  END o[480]
  PIN o[481]
    DIRECTION OUTPUT ;
    USE SIGNAL ;
    PORT
      LAYER M4 ;
        RECT  17.088 52.032 17.28 52.056 ;
    END
  END o[481]
  PIN o[482]
    DIRECTION OUTPUT ;
    USE SIGNAL ;
    PORT
      LAYER M4 ;
        RECT  17.088 52.176 17.28 52.2 ;
    END
  END o[482]
  PIN o[483]
    DIRECTION OUTPUT ;
    USE SIGNAL ;
    PORT
      LAYER M4 ;
        RECT  17.088 52.272 17.28 52.296 ;
    END
  END o[483]
  PIN o[484]
    DIRECTION OUTPUT ;
    USE SIGNAL ;
    PORT
      LAYER M4 ;
        RECT  17.088 52.368 17.28 52.392 ;
    END
  END o[484]
  PIN o[485]
    DIRECTION OUTPUT ;
    USE SIGNAL ;
    PORT
      LAYER M4 ;
        RECT  17.088 52.464 17.28 52.488 ;
    END
  END o[485]
  PIN o[486]
    DIRECTION OUTPUT ;
    USE SIGNAL ;
    PORT
      LAYER M4 ;
        RECT  17.088 52.56 17.28 52.584 ;
    END
  END o[486]
  PIN o[487]
    DIRECTION OUTPUT ;
    USE SIGNAL ;
    PORT
      LAYER M4 ;
        RECT  17.088 52.656 17.28 52.68 ;
    END
  END o[487]
  PIN o[488]
    DIRECTION OUTPUT ;
    USE SIGNAL ;
    PORT
      LAYER M4 ;
        RECT  17.088 52.752 17.28 52.776 ;
    END
  END o[488]
  PIN o[489]
    DIRECTION OUTPUT ;
    USE SIGNAL ;
    PORT
      LAYER M4 ;
        RECT  17.088 52.896 17.28 52.92 ;
    END
  END o[489]
  PIN o[48]
    DIRECTION OUTPUT ;
    USE SIGNAL ;
    PORT
      LAYER M4 ;
        RECT  17.088 7.2 17.28 7.224 ;
    END
  END o[48]
  PIN o[490]
    DIRECTION OUTPUT ;
    USE SIGNAL ;
    PORT
      LAYER M4 ;
        RECT  17.088 52.992 17.28 53.016 ;
    END
  END o[490]
  PIN o[491]
    DIRECTION OUTPUT ;
    USE SIGNAL ;
    PORT
      LAYER M4 ;
        RECT  17.088 53.088 17.28 53.112 ;
    END
  END o[491]
  PIN o[492]
    DIRECTION OUTPUT ;
    USE SIGNAL ;
    PORT
      LAYER M4 ;
        RECT  17.088 53.184 17.28 53.208 ;
    END
  END o[492]
  PIN o[493]
    DIRECTION OUTPUT ;
    USE SIGNAL ;
    PORT
      LAYER M4 ;
        RECT  17.088 53.28 17.28 53.304 ;
    END
  END o[493]
  PIN o[494]
    DIRECTION OUTPUT ;
    USE SIGNAL ;
    PORT
      LAYER M4 ;
        RECT  17.088 53.376 17.28 53.4 ;
    END
  END o[494]
  PIN o[495]
    DIRECTION OUTPUT ;
    USE SIGNAL ;
    PORT
      LAYER M4 ;
        RECT  17.088 53.52 17.28 53.544 ;
    END
  END o[495]
  PIN o[496]
    DIRECTION OUTPUT ;
    USE SIGNAL ;
    PORT
      LAYER M4 ;
        RECT  17.088 53.616 17.28 53.64 ;
    END
  END o[496]
  PIN o[497]
    DIRECTION OUTPUT ;
    USE SIGNAL ;
    PORT
      LAYER M4 ;
        RECT  17.088 53.712 17.28 53.736 ;
    END
  END o[497]
  PIN o[498]
    DIRECTION OUTPUT ;
    USE SIGNAL ;
    PORT
      LAYER M4 ;
        RECT  17.088 53.808 17.28 53.832 ;
    END
  END o[498]
  PIN o[499]
    DIRECTION OUTPUT ;
    USE SIGNAL ;
    PORT
      LAYER M4 ;
        RECT  17.088 53.904 17.28 53.928 ;
    END
  END o[499]
  PIN o[49]
    DIRECTION OUTPUT ;
    USE SIGNAL ;
    PORT
      LAYER M4 ;
        RECT  17.088 7.296 17.28 7.32 ;
    END
  END o[49]
  PIN o[4]
    DIRECTION OUTPUT ;
    USE SIGNAL ;
    PORT
      LAYER M4 ;
        RECT  17.088 2.64 17.28 2.664 ;
    END
  END o[4]
  PIN o[500]
    DIRECTION OUTPUT ;
    USE SIGNAL ;
    PORT
      LAYER M4 ;
        RECT  17.088 54 17.28 54.024 ;
    END
  END o[500]
  PIN o[501]
    DIRECTION OUTPUT ;
    USE SIGNAL ;
    PORT
      LAYER M4 ;
        RECT  17.088 54.144 17.28 54.168 ;
    END
  END o[501]
  PIN o[502]
    DIRECTION OUTPUT ;
    USE SIGNAL ;
    PORT
      LAYER M4 ;
        RECT  17.088 54.24 17.28 54.264 ;
    END
  END o[502]
  PIN o[503]
    DIRECTION OUTPUT ;
    USE SIGNAL ;
    PORT
      LAYER M4 ;
        RECT  17.088 54.336 17.28 54.36 ;
    END
  END o[503]
  PIN o[504]
    DIRECTION OUTPUT ;
    USE SIGNAL ;
    PORT
      LAYER M4 ;
        RECT  17.088 54.432 17.28 54.456 ;
    END
  END o[504]
  PIN o[505]
    DIRECTION OUTPUT ;
    USE SIGNAL ;
    PORT
      LAYER M4 ;
        RECT  17.088 54.528 17.28 54.552 ;
    END
  END o[505]
  PIN o[506]
    DIRECTION OUTPUT ;
    USE SIGNAL ;
    PORT
      LAYER M4 ;
        RECT  17.088 54.624 17.28 54.648 ;
    END
  END o[506]
  PIN o[507]
    DIRECTION OUTPUT ;
    USE SIGNAL ;
    PORT
      LAYER M4 ;
        RECT  17.088 54.72 17.28 54.744 ;
    END
  END o[507]
  PIN o[508]
    DIRECTION OUTPUT ;
    USE SIGNAL ;
    PORT
      LAYER M4 ;
        RECT  17.088 54.864 17.28 54.888 ;
    END
  END o[508]
  PIN o[509]
    DIRECTION OUTPUT ;
    USE SIGNAL ;
    PORT
      LAYER M4 ;
        RECT  17.088 54.96 17.28 54.984 ;
    END
  END o[509]
  PIN o[50]
    DIRECTION OUTPUT ;
    USE SIGNAL ;
    PORT
      LAYER M4 ;
        RECT  17.088 7.392 17.28 7.416 ;
    END
  END o[50]
  PIN o[510]
    DIRECTION OUTPUT ;
    USE SIGNAL ;
    PORT
      LAYER M4 ;
        RECT  17.088 55.056 17.28 55.08 ;
    END
  END o[510]
  PIN o[511]
    DIRECTION OUTPUT ;
    USE SIGNAL ;
    PORT
      LAYER M4 ;
        RECT  17.088 55.152 17.28 55.176 ;
    END
  END o[511]
  PIN o[512]
    DIRECTION OUTPUT ;
    USE SIGNAL ;
    PORT
      LAYER M4 ;
        RECT  17.088 55.248 17.28 55.272 ;
    END
  END o[512]
  PIN o[513]
    DIRECTION OUTPUT ;
    USE SIGNAL ;
    PORT
      LAYER M4 ;
        RECT  17.088 55.344 17.28 55.368 ;
    END
  END o[513]
  PIN o[514]
    DIRECTION OUTPUT ;
    USE SIGNAL ;
    PORT
      LAYER M4 ;
        RECT  17.088 55.488 17.28 55.512 ;
    END
  END o[514]
  PIN o[515]
    DIRECTION OUTPUT ;
    USE SIGNAL ;
    PORT
      LAYER M4 ;
        RECT  17.088 55.584 17.28 55.608 ;
    END
  END o[515]
  PIN o[516]
    DIRECTION OUTPUT ;
    USE SIGNAL ;
    PORT
      LAYER M4 ;
        RECT  17.088 55.68 17.28 55.704 ;
    END
  END o[516]
  PIN o[517]
    DIRECTION OUTPUT ;
    USE SIGNAL ;
    PORT
      LAYER M4 ;
        RECT  17.088 55.776 17.28 55.8 ;
    END
  END o[517]
  PIN o[518]
    DIRECTION OUTPUT ;
    USE SIGNAL ;
    PORT
      LAYER M4 ;
        RECT  17.088 55.872 17.28 55.896 ;
    END
  END o[518]
  PIN o[519]
    DIRECTION OUTPUT ;
    USE SIGNAL ;
    PORT
      LAYER M4 ;
        RECT  17.088 55.968 17.28 55.992 ;
    END
  END o[519]
  PIN o[51]
    DIRECTION OUTPUT ;
    USE SIGNAL ;
    PORT
      LAYER M4 ;
        RECT  17.088 7.488 17.28 7.512 ;
    END
  END o[51]
  PIN o[520]
    DIRECTION OUTPUT ;
    USE SIGNAL ;
    PORT
      LAYER M4 ;
        RECT  17.088 56.112 17.28 56.136 ;
    END
  END o[520]
  PIN o[521]
    DIRECTION OUTPUT ;
    USE SIGNAL ;
    PORT
      LAYER M4 ;
        RECT  17.088 56.208 17.28 56.232 ;
    END
  END o[521]
  PIN o[522]
    DIRECTION OUTPUT ;
    USE SIGNAL ;
    PORT
      LAYER M4 ;
        RECT  17.088 56.304 17.28 56.328 ;
    END
  END o[522]
  PIN o[523]
    DIRECTION OUTPUT ;
    USE SIGNAL ;
    PORT
      LAYER M4 ;
        RECT  17.088 56.4 17.28 56.424 ;
    END
  END o[523]
  PIN o[524]
    DIRECTION OUTPUT ;
    USE SIGNAL ;
    PORT
      LAYER M4 ;
        RECT  17.088 56.496 17.28 56.52 ;
    END
  END o[524]
  PIN o[525]
    DIRECTION OUTPUT ;
    USE SIGNAL ;
    PORT
      LAYER M4 ;
        RECT  17.088 56.592 17.28 56.616 ;
    END
  END o[525]
  PIN o[526]
    DIRECTION OUTPUT ;
    USE SIGNAL ;
    PORT
      LAYER M4 ;
        RECT  17.088 56.688 17.28 56.712 ;
    END
  END o[526]
  PIN o[527]
    DIRECTION OUTPUT ;
    USE SIGNAL ;
    PORT
      LAYER M4 ;
        RECT  17.088 56.832 17.28 56.856 ;
    END
  END o[527]
  PIN o[528]
    DIRECTION OUTPUT ;
    USE SIGNAL ;
    PORT
      LAYER M4 ;
        RECT  17.088 56.928 17.28 56.952 ;
    END
  END o[528]
  PIN o[529]
    DIRECTION OUTPUT ;
    USE SIGNAL ;
    PORT
      LAYER M4 ;
        RECT  17.088 57.024 17.28 57.048 ;
    END
  END o[529]
  PIN o[52]
    DIRECTION OUTPUT ;
    USE SIGNAL ;
    PORT
      LAYER M4 ;
        RECT  17.088 7.632 17.28 7.656 ;
    END
  END o[52]
  PIN o[530]
    DIRECTION OUTPUT ;
    USE SIGNAL ;
    PORT
      LAYER M4 ;
        RECT  17.088 57.12 17.28 57.144 ;
    END
  END o[530]
  PIN o[531]
    DIRECTION OUTPUT ;
    USE SIGNAL ;
    PORT
      LAYER M4 ;
        RECT  17.088 57.216 17.28 57.24 ;
    END
  END o[531]
  PIN o[532]
    DIRECTION OUTPUT ;
    USE SIGNAL ;
    PORT
      LAYER M4 ;
        RECT  17.088 57.312 17.28 57.336 ;
    END
  END o[532]
  PIN o[533]
    DIRECTION OUTPUT ;
    USE SIGNAL ;
    PORT
      LAYER M4 ;
        RECT  17.088 57.456 17.28 57.48 ;
    END
  END o[533]
  PIN o[534]
    DIRECTION OUTPUT ;
    USE SIGNAL ;
    PORT
      LAYER M4 ;
        RECT  17.088 57.552 17.28 57.576 ;
    END
  END o[534]
  PIN o[535]
    DIRECTION OUTPUT ;
    USE SIGNAL ;
    PORT
      LAYER M4 ;
        RECT  17.088 57.648 17.28 57.672 ;
    END
  END o[535]
  PIN o[536]
    DIRECTION OUTPUT ;
    USE SIGNAL ;
    PORT
      LAYER M4 ;
        RECT  17.088 57.744 17.28 57.768 ;
    END
  END o[536]
  PIN o[537]
    DIRECTION OUTPUT ;
    USE SIGNAL ;
    PORT
      LAYER M4 ;
        RECT  17.088 57.84 17.28 57.864 ;
    END
  END o[537]
  PIN o[538]
    DIRECTION OUTPUT ;
    USE SIGNAL ;
    PORT
      LAYER M4 ;
        RECT  17.088 57.936 17.28 57.96 ;
    END
  END o[538]
  PIN o[539]
    DIRECTION OUTPUT ;
    USE SIGNAL ;
    PORT
      LAYER M4 ;
        RECT  17.088 58.08 17.28 58.104 ;
    END
  END o[539]
  PIN o[53]
    DIRECTION OUTPUT ;
    USE SIGNAL ;
    PORT
      LAYER M4 ;
        RECT  17.088 7.728 17.28 7.752 ;
    END
  END o[53]
  PIN o[540]
    DIRECTION OUTPUT ;
    USE SIGNAL ;
    PORT
      LAYER M4 ;
        RECT  17.088 58.176 17.28 58.2 ;
    END
  END o[540]
  PIN o[541]
    DIRECTION OUTPUT ;
    USE SIGNAL ;
    PORT
      LAYER M4 ;
        RECT  17.088 58.272 17.28 58.296 ;
    END
  END o[541]
  PIN o[542]
    DIRECTION OUTPUT ;
    USE SIGNAL ;
    PORT
      LAYER M4 ;
        RECT  17.088 58.368 17.28 58.392 ;
    END
  END o[542]
  PIN o[543]
    DIRECTION OUTPUT ;
    USE SIGNAL ;
    PORT
      LAYER M4 ;
        RECT  17.088 58.464 17.28 58.488 ;
    END
  END o[543]
  PIN o[544]
    DIRECTION OUTPUT ;
    USE SIGNAL ;
    PORT
      LAYER M4 ;
        RECT  17.088 58.56 17.28 58.584 ;
    END
  END o[544]
  PIN o[545]
    DIRECTION OUTPUT ;
    USE SIGNAL ;
    PORT
      LAYER M4 ;
        RECT  17.088 58.656 17.28 58.68 ;
    END
  END o[545]
  PIN o[546]
    DIRECTION OUTPUT ;
    USE SIGNAL ;
    PORT
      LAYER M4 ;
        RECT  17.088 58.8 17.28 58.824 ;
    END
  END o[546]
  PIN o[547]
    DIRECTION OUTPUT ;
    USE SIGNAL ;
    PORT
      LAYER M4 ;
        RECT  17.088 58.896 17.28 58.92 ;
    END
  END o[547]
  PIN o[548]
    DIRECTION OUTPUT ;
    USE SIGNAL ;
    PORT
      LAYER M4 ;
        RECT  17.088 58.992 17.28 59.016 ;
    END
  END o[548]
  PIN o[549]
    DIRECTION OUTPUT ;
    USE SIGNAL ;
    PORT
      LAYER M4 ;
        RECT  17.088 59.088 17.28 59.112 ;
    END
  END o[549]
  PIN o[54]
    DIRECTION OUTPUT ;
    USE SIGNAL ;
    PORT
      LAYER M4 ;
        RECT  17.088 7.824 17.28 7.848 ;
    END
  END o[54]
  PIN o[550]
    DIRECTION OUTPUT ;
    USE SIGNAL ;
    PORT
      LAYER M4 ;
        RECT  17.088 59.184 17.28 59.208 ;
    END
  END o[550]
  PIN o[551]
    DIRECTION OUTPUT ;
    USE SIGNAL ;
    PORT
      LAYER M4 ;
        RECT  17.088 59.28 17.28 59.304 ;
    END
  END o[551]
  PIN o[552]
    DIRECTION OUTPUT ;
    USE SIGNAL ;
    PORT
      LAYER M4 ;
        RECT  17.088 59.424 17.28 59.448 ;
    END
  END o[552]
  PIN o[553]
    DIRECTION OUTPUT ;
    USE SIGNAL ;
    PORT
      LAYER M4 ;
        RECT  17.088 59.52 17.28 59.544 ;
    END
  END o[553]
  PIN o[554]
    DIRECTION OUTPUT ;
    USE SIGNAL ;
    PORT
      LAYER M4 ;
        RECT  17.088 59.616 17.28 59.64 ;
    END
  END o[554]
  PIN o[555]
    DIRECTION OUTPUT ;
    USE SIGNAL ;
    PORT
      LAYER M4 ;
        RECT  17.088 59.712 17.28 59.736 ;
    END
  END o[555]
  PIN o[556]
    DIRECTION OUTPUT ;
    USE SIGNAL ;
    PORT
      LAYER M4 ;
        RECT  17.088 59.808 17.28 59.832 ;
    END
  END o[556]
  PIN o[557]
    DIRECTION OUTPUT ;
    USE SIGNAL ;
    PORT
      LAYER M4 ;
        RECT  17.088 59.904 17.28 59.928 ;
    END
  END o[557]
  PIN o[558]
    DIRECTION OUTPUT ;
    USE SIGNAL ;
    PORT
      LAYER M4 ;
        RECT  17.088 60.048 17.28 60.072 ;
    END
  END o[558]
  PIN o[559]
    DIRECTION OUTPUT ;
    USE SIGNAL ;
    PORT
      LAYER M4 ;
        RECT  17.088 60.144 17.28 60.168 ;
    END
  END o[559]
  PIN o[55]
    DIRECTION OUTPUT ;
    USE SIGNAL ;
    PORT
      LAYER M4 ;
        RECT  17.088 7.92 17.28 7.944 ;
    END
  END o[55]
  PIN o[560]
    DIRECTION OUTPUT ;
    USE SIGNAL ;
    PORT
      LAYER M4 ;
        RECT  17.088 60.24 17.28 60.264 ;
    END
  END o[560]
  PIN o[561]
    DIRECTION OUTPUT ;
    USE SIGNAL ;
    PORT
      LAYER M4 ;
        RECT  17.088 60.336 17.28 60.36 ;
    END
  END o[561]
  PIN o[56]
    DIRECTION OUTPUT ;
    USE SIGNAL ;
    PORT
      LAYER M4 ;
        RECT  17.088 8.016 17.28 8.04 ;
    END
  END o[56]
  PIN o[57]
    DIRECTION OUTPUT ;
    USE SIGNAL ;
    PORT
      LAYER M4 ;
        RECT  17.088 8.112 17.28 8.136 ;
    END
  END o[57]
  PIN o[58]
    DIRECTION OUTPUT ;
    USE SIGNAL ;
    PORT
      LAYER M4 ;
        RECT  17.088 8.208 17.28 8.232 ;
    END
  END o[58]
  PIN o[59]
    DIRECTION OUTPUT ;
    USE SIGNAL ;
    PORT
      LAYER M4 ;
        RECT  17.088 8.352 17.28 8.376 ;
    END
  END o[59]
  PIN o[5]
    DIRECTION OUTPUT ;
    USE SIGNAL ;
    PORT
      LAYER M4 ;
        RECT  17.088 2.736 17.28 2.76 ;
    END
  END o[5]
  PIN o[60]
    DIRECTION OUTPUT ;
    USE SIGNAL ;
    PORT
      LAYER M4 ;
        RECT  17.088 8.448 17.28 8.472 ;
    END
  END o[60]
  PIN o[61]
    DIRECTION OUTPUT ;
    USE SIGNAL ;
    PORT
      LAYER M4 ;
        RECT  17.088 8.544 17.28 8.568 ;
    END
  END o[61]
  PIN o[62]
    DIRECTION OUTPUT ;
    USE SIGNAL ;
    PORT
      LAYER M4 ;
        RECT  17.088 8.64 17.28 8.664 ;
    END
  END o[62]
  PIN o[63]
    DIRECTION OUTPUT ;
    USE SIGNAL ;
    PORT
      LAYER M4 ;
        RECT  17.088 8.736 17.28 8.76 ;
    END
  END o[63]
  PIN o[64]
    DIRECTION OUTPUT ;
    USE SIGNAL ;
    PORT
      LAYER M4 ;
        RECT  17.088 8.832 17.28 8.856 ;
    END
  END o[64]
  PIN o[65]
    DIRECTION OUTPUT ;
    USE SIGNAL ;
    PORT
      LAYER M4 ;
        RECT  17.088 8.976 17.28 9 ;
    END
  END o[65]
  PIN o[66]
    DIRECTION OUTPUT ;
    USE SIGNAL ;
    PORT
      LAYER M4 ;
        RECT  17.088 9.072 17.28 9.096 ;
    END
  END o[66]
  PIN o[67]
    DIRECTION OUTPUT ;
    USE SIGNAL ;
    PORT
      LAYER M4 ;
        RECT  17.088 9.168 17.28 9.192 ;
    END
  END o[67]
  PIN o[68]
    DIRECTION OUTPUT ;
    USE SIGNAL ;
    PORT
      LAYER M4 ;
        RECT  17.088 9.264 17.28 9.288 ;
    END
  END o[68]
  PIN o[69]
    DIRECTION OUTPUT ;
    USE SIGNAL ;
    PORT
      LAYER M4 ;
        RECT  17.088 9.36 17.28 9.384 ;
    END
  END o[69]
  PIN o[6]
    DIRECTION OUTPUT ;
    USE SIGNAL ;
    PORT
      LAYER M4 ;
        RECT  17.088 2.832 17.28 2.856 ;
    END
  END o[6]
  PIN o[70]
    DIRECTION OUTPUT ;
    USE SIGNAL ;
    PORT
      LAYER M4 ;
        RECT  17.088 9.456 17.28 9.48 ;
    END
  END o[70]
  PIN o[71]
    DIRECTION OUTPUT ;
    USE SIGNAL ;
    PORT
      LAYER M4 ;
        RECT  17.088 9.6 17.28 9.624 ;
    END
  END o[71]
  PIN o[72]
    DIRECTION OUTPUT ;
    USE SIGNAL ;
    PORT
      LAYER M4 ;
        RECT  17.088 9.696 17.28 9.72 ;
    END
  END o[72]
  PIN o[73]
    DIRECTION OUTPUT ;
    USE SIGNAL ;
    PORT
      LAYER M4 ;
        RECT  17.088 9.792 17.28 9.816 ;
    END
  END o[73]
  PIN o[74]
    DIRECTION OUTPUT ;
    USE SIGNAL ;
    PORT
      LAYER M4 ;
        RECT  17.088 9.888 17.28 9.912 ;
    END
  END o[74]
  PIN o[75]
    DIRECTION OUTPUT ;
    USE SIGNAL ;
    PORT
      LAYER M4 ;
        RECT  17.088 9.984 17.28 10.008 ;
    END
  END o[75]
  PIN o[76]
    DIRECTION OUTPUT ;
    USE SIGNAL ;
    PORT
      LAYER M4 ;
        RECT  17.088 10.08 17.28 10.104 ;
    END
  END o[76]
  PIN o[77]
    DIRECTION OUTPUT ;
    USE SIGNAL ;
    PORT
      LAYER M4 ;
        RECT  17.088 10.224 17.28 10.248 ;
    END
  END o[77]
  PIN o[78]
    DIRECTION OUTPUT ;
    USE SIGNAL ;
    PORT
      LAYER M4 ;
        RECT  17.088 10.32 17.28 10.344 ;
    END
  END o[78]
  PIN o[79]
    DIRECTION OUTPUT ;
    USE SIGNAL ;
    PORT
      LAYER M4 ;
        RECT  17.088 10.416 17.28 10.44 ;
    END
  END o[79]
  PIN o[7]
    DIRECTION OUTPUT ;
    USE SIGNAL ;
    PORT
      LAYER M4 ;
        RECT  17.088 2.928 17.28 2.952 ;
    END
  END o[7]
  PIN o[80]
    DIRECTION OUTPUT ;
    USE SIGNAL ;
    PORT
      LAYER M4 ;
        RECT  17.088 10.512 17.28 10.536 ;
    END
  END o[80]
  PIN o[81]
    DIRECTION OUTPUT ;
    USE SIGNAL ;
    PORT
      LAYER M4 ;
        RECT  17.088 10.608 17.28 10.632 ;
    END
  END o[81]
  PIN o[82]
    DIRECTION OUTPUT ;
    USE SIGNAL ;
    PORT
      LAYER M4 ;
        RECT  17.088 10.704 17.28 10.728 ;
    END
  END o[82]
  PIN o[83]
    DIRECTION OUTPUT ;
    USE SIGNAL ;
    PORT
      LAYER M4 ;
        RECT  17.088 10.8 17.28 10.824 ;
    END
  END o[83]
  PIN o[84]
    DIRECTION OUTPUT ;
    USE SIGNAL ;
    PORT
      LAYER M4 ;
        RECT  17.088 10.944 17.28 10.968 ;
    END
  END o[84]
  PIN o[85]
    DIRECTION OUTPUT ;
    USE SIGNAL ;
    PORT
      LAYER M4 ;
        RECT  17.088 11.04 17.28 11.064 ;
    END
  END o[85]
  PIN o[86]
    DIRECTION OUTPUT ;
    USE SIGNAL ;
    PORT
      LAYER M4 ;
        RECT  17.088 11.136 17.28 11.16 ;
    END
  END o[86]
  PIN o[87]
    DIRECTION OUTPUT ;
    USE SIGNAL ;
    PORT
      LAYER M4 ;
        RECT  17.088 11.232 17.28 11.256 ;
    END
  END o[87]
  PIN o[88]
    DIRECTION OUTPUT ;
    USE SIGNAL ;
    PORT
      LAYER M4 ;
        RECT  17.088 11.328 17.28 11.352 ;
    END
  END o[88]
  PIN o[89]
    DIRECTION OUTPUT ;
    USE SIGNAL ;
    PORT
      LAYER M4 ;
        RECT  17.088 11.424 17.28 11.448 ;
    END
  END o[89]
  PIN o[8]
    DIRECTION OUTPUT ;
    USE SIGNAL ;
    PORT
      LAYER M4 ;
        RECT  17.088 3.072 17.28 3.096 ;
    END
  END o[8]
  PIN o[90]
    DIRECTION OUTPUT ;
    USE SIGNAL ;
    PORT
      LAYER M4 ;
        RECT  17.088 11.568 17.28 11.592 ;
    END
  END o[90]
  PIN o[91]
    DIRECTION OUTPUT ;
    USE SIGNAL ;
    PORT
      LAYER M4 ;
        RECT  17.088 11.664 17.28 11.688 ;
    END
  END o[91]
  PIN o[92]
    DIRECTION OUTPUT ;
    USE SIGNAL ;
    PORT
      LAYER M4 ;
        RECT  17.088 11.76 17.28 11.784 ;
    END
  END o[92]
  PIN o[93]
    DIRECTION OUTPUT ;
    USE SIGNAL ;
    PORT
      LAYER M4 ;
        RECT  17.088 11.856 17.28 11.88 ;
    END
  END o[93]
  PIN o[94]
    DIRECTION OUTPUT ;
    USE SIGNAL ;
    PORT
      LAYER M4 ;
        RECT  17.088 11.952 17.28 11.976 ;
    END
  END o[94]
  PIN o[95]
    DIRECTION OUTPUT ;
    USE SIGNAL ;
    PORT
      LAYER M4 ;
        RECT  17.088 12.048 17.28 12.072 ;
    END
  END o[95]
  PIN o[96]
    DIRECTION OUTPUT ;
    USE SIGNAL ;
    PORT
      LAYER M4 ;
        RECT  17.088 12.192 17.28 12.216 ;
    END
  END o[96]
  PIN o[97]
    DIRECTION OUTPUT ;
    USE SIGNAL ;
    PORT
      LAYER M4 ;
        RECT  17.088 12.288 17.28 12.312 ;
    END
  END o[97]
  PIN o[98]
    DIRECTION OUTPUT ;
    USE SIGNAL ;
    PORT
      LAYER M4 ;
        RECT  17.088 12.384 17.28 12.408 ;
    END
  END o[98]
  PIN o[99]
    DIRECTION OUTPUT ;
    USE SIGNAL ;
    PORT
      LAYER M4 ;
        RECT  17.088 12.48 17.28 12.504 ;
    END
  END o[99]
  PIN o[9]
    DIRECTION OUTPUT ;
    USE SIGNAL ;
    PORT
      LAYER M4 ;
        RECT  17.088 3.168 17.28 3.192 ;
    END
  END o[9]
  PIN rs
    DIRECTION INPUT ;
    USE SIGNAL ;
    PORT
      LAYER M5 ;
        RECT  11.856 62.448 11.88 62.64 ;
    END
  END rs
  PIN VDD
    DIRECTION INOUT ;
    USE POWER ;
    PORT
      LAYER M5 ;
        RECT  13.392 2.151 13.512 60.489 ;
        RECT  10.692 2.151 10.812 60.489 ;
        RECT  7.992 2.151 8.112 60.489 ;
        RECT  5.292 2.151 5.412 60.489 ;
        RECT  2.592 2.151 2.712 60.489 ;
    END
  END VDD
  PIN VSS
    DIRECTION INOUT ;
    USE GROUND ;
    PORT
      LAYER M5 ;
        RECT  13.2 2.137 13.32 60.503 ;
        RECT  10.5 2.137 10.62 60.503 ;
        RECT  7.8 2.137 7.92 60.503 ;
        RECT  5.1 2.137 5.22 60.503 ;
        RECT  2.4 2.137 2.52 60.503 ;
    END
  END VSS
  OBS
    LAYER RVTN ;
     RECT  2.16 2.16 15.12 2.295 ;
     RECT  2.16 2.565 15.12 2.835 ;
     RECT  2.16 3.105 15.12 3.375 ;
     RECT  2.16 3.645 15.12 3.915 ;
     RECT  2.16 4.185 15.12 4.455 ;
     RECT  2.16 4.725 15.12 4.995 ;
     RECT  2.16 5.265 15.12 5.535 ;
     RECT  2.16 5.805 15.12 6.075 ;
     RECT  2.16 6.345 15.12 6.615 ;
     RECT  2.16 6.885 15.12 7.155 ;
     RECT  2.16 7.425 15.12 7.695 ;
     RECT  2.16 7.965 15.12 8.235 ;
     RECT  2.16 8.505 15.12 8.775 ;
     RECT  2.16 9.045 15.12 9.315 ;
     RECT  2.16 9.585 15.12 9.855 ;
     RECT  2.16 10.125 15.12 10.395 ;
     RECT  2.16 10.665 15.12 10.935 ;
     RECT  2.16 11.205 15.12 11.475 ;
     RECT  2.16 11.745 15.12 12.015 ;
     RECT  2.16 12.285 15.12 12.555 ;
     RECT  2.16 12.825 15.12 13.095 ;
     RECT  2.16 13.365 15.12 13.635 ;
     RECT  2.16 13.905 15.12 14.175 ;
     RECT  2.16 14.445 15.12 14.715 ;
     RECT  2.16 14.985 15.12 15.255 ;
     RECT  2.16 15.525 15.12 15.795 ;
     RECT  2.16 16.065 15.12 16.335 ;
     RECT  2.16 16.605 15.12 16.875 ;
     RECT  2.16 17.145 15.12 17.415 ;
     RECT  2.16 17.685 15.12 17.955 ;
     RECT  2.16 18.225 15.12 18.495 ;
     RECT  2.16 18.765 15.12 19.035 ;
     RECT  2.16 19.305 15.12 19.575 ;
     RECT  2.16 19.845 15.12 20.115 ;
     RECT  2.16 20.385 15.12 20.655 ;
     RECT  2.16 20.925 15.12 21.195 ;
     RECT  2.16 21.465 15.12 21.735 ;
     RECT  2.16 22.005 15.12 22.275 ;
     RECT  2.16 22.545 15.12 22.815 ;
     RECT  2.16 23.085 15.12 23.355 ;
     RECT  2.16 23.625 15.12 23.895 ;
     RECT  2.16 24.165 15.12 24.435 ;
     RECT  2.16 24.705 15.12 24.975 ;
     RECT  2.16 25.245 15.12 25.515 ;
     RECT  2.16 25.785 15.12 26.055 ;
     RECT  2.16 26.325 15.12 26.595 ;
     RECT  2.16 26.865 15.12 27.135 ;
     RECT  2.16 27.405 15.12 27.675 ;
     RECT  2.16 27.945 15.12 28.215 ;
     RECT  2.16 28.485 15.12 28.755 ;
     RECT  2.16 29.025 15.12 29.295 ;
     RECT  2.16 29.565 15.12 29.835 ;
     RECT  2.16 30.105 15.12 30.375 ;
     RECT  2.16 30.645 15.12 30.915 ;
     RECT  2.16 31.185 15.12 31.455 ;
     RECT  2.16 31.725 15.12 31.995 ;
     RECT  2.16 32.265 15.12 32.535 ;
     RECT  2.16 32.805 15.12 33.075 ;
     RECT  2.16 33.345 15.12 33.615 ;
     RECT  2.16 33.885 15.12 34.155 ;
     RECT  2.16 34.425 15.12 34.695 ;
     RECT  2.16 34.965 15.12 35.235 ;
     RECT  2.16 35.505 15.12 35.775 ;
     RECT  2.16 36.045 15.12 36.315 ;
     RECT  2.16 36.585 15.12 36.855 ;
     RECT  2.16 37.125 15.12 37.395 ;
     RECT  2.16 37.665 15.12 37.935 ;
     RECT  2.16 38.205 15.12 38.475 ;
     RECT  2.16 38.745 15.12 39.015 ;
     RECT  2.16 39.285 15.12 39.555 ;
     RECT  2.16 39.825 15.12 40.095 ;
     RECT  2.16 40.365 15.12 40.635 ;
     RECT  2.16 40.905 15.12 41.175 ;
     RECT  2.16 41.445 15.12 41.715 ;
     RECT  2.16 41.985 15.12 42.255 ;
     RECT  2.16 42.525 15.12 42.795 ;
     RECT  2.16 43.065 15.12 43.335 ;
     RECT  2.16 43.605 15.12 43.875 ;
     RECT  2.16 44.145 15.12 44.415 ;
     RECT  2.16 44.685 15.12 44.955 ;
     RECT  2.16 45.225 15.12 45.495 ;
     RECT  2.16 45.765 15.12 46.035 ;
     RECT  2.16 46.305 15.12 46.575 ;
     RECT  2.16 46.845 15.12 47.115 ;
     RECT  2.16 47.385 15.12 47.655 ;
     RECT  2.16 47.925 15.12 48.195 ;
     RECT  2.16 48.465 15.12 48.735 ;
     RECT  2.16 49.005 15.12 49.275 ;
     RECT  2.16 49.545 15.12 49.815 ;
     RECT  2.16 50.085 15.12 50.355 ;
     RECT  2.16 50.625 15.12 50.895 ;
     RECT  2.16 51.165 15.12 51.435 ;
     RECT  2.16 51.705 15.12 51.975 ;
     RECT  2.16 52.245 15.12 52.515 ;
     RECT  2.16 52.785 15.12 53.055 ;
     RECT  2.16 53.325 15.12 53.595 ;
     RECT  2.16 53.865 15.12 54.135 ;
     RECT  2.16 54.405 15.12 54.675 ;
     RECT  2.16 54.945 15.12 55.215 ;
     RECT  2.16 55.485 15.12 55.755 ;
     RECT  2.16 56.025 15.12 56.295 ;
     RECT  2.16 56.565 15.12 56.835 ;
     RECT  2.16 57.105 15.12 57.375 ;
     RECT  2.16 57.645 15.12 57.915 ;
     RECT  2.16 58.185 15.12 58.455 ;
     RECT  2.16 58.725 15.12 58.995 ;
     RECT  2.16 59.265 15.12 59.535 ;
     RECT  2.16 59.805 15.12 60.075 ;
     RECT  2.16 60.345 15.12 60.48 ;
    LAYER RVTP ;
     RECT  2.16 2.295 15.12 2.565 ;
     RECT  2.16 2.835 15.12 3.105 ;
     RECT  2.16 3.375 15.12 3.645 ;
     RECT  2.16 3.915 15.12 4.185 ;
     RECT  2.16 4.455 15.12 4.725 ;
     RECT  2.16 4.995 15.12 5.265 ;
     RECT  2.16 5.535 15.12 5.805 ;
     RECT  2.16 6.075 15.12 6.345 ;
     RECT  2.16 6.615 15.12 6.885 ;
     RECT  2.16 7.155 15.12 7.425 ;
     RECT  2.16 7.695 15.12 7.965 ;
     RECT  2.16 8.235 15.12 8.505 ;
     RECT  2.16 8.775 15.12 9.045 ;
     RECT  2.16 9.315 15.12 9.585 ;
     RECT  2.16 9.855 15.12 10.125 ;
     RECT  2.16 10.395 15.12 10.665 ;
     RECT  2.16 10.935 15.12 11.205 ;
     RECT  2.16 11.475 15.12 11.745 ;
     RECT  2.16 12.015 15.12 12.285 ;
     RECT  2.16 12.555 15.12 12.825 ;
     RECT  2.16 13.095 15.12 13.365 ;
     RECT  2.16 13.635 15.12 13.905 ;
     RECT  2.16 14.175 15.12 14.445 ;
     RECT  2.16 14.715 15.12 14.985 ;
     RECT  2.16 15.255 15.12 15.525 ;
     RECT  2.16 15.795 15.12 16.065 ;
     RECT  2.16 16.335 15.12 16.605 ;
     RECT  2.16 16.875 15.12 17.145 ;
     RECT  2.16 17.415 15.12 17.685 ;
     RECT  2.16 17.955 15.12 18.225 ;
     RECT  2.16 18.495 15.12 18.765 ;
     RECT  2.16 19.035 15.12 19.305 ;
     RECT  2.16 19.575 15.12 19.845 ;
     RECT  2.16 20.115 15.12 20.385 ;
     RECT  2.16 20.655 15.12 20.925 ;
     RECT  2.16 21.195 15.12 21.465 ;
     RECT  2.16 21.735 15.12 22.005 ;
     RECT  2.16 22.275 15.12 22.545 ;
     RECT  2.16 22.815 15.12 23.085 ;
     RECT  2.16 23.355 15.12 23.625 ;
     RECT  2.16 23.895 15.12 24.165 ;
     RECT  2.16 24.435 15.12 24.705 ;
     RECT  2.16 24.975 15.12 25.245 ;
     RECT  2.16 25.515 15.12 25.785 ;
     RECT  2.16 26.055 15.12 26.325 ;
     RECT  2.16 26.595 15.12 26.865 ;
     RECT  2.16 27.135 15.12 27.405 ;
     RECT  2.16 27.675 15.12 27.945 ;
     RECT  2.16 28.215 15.12 28.485 ;
     RECT  2.16 28.755 15.12 29.025 ;
     RECT  2.16 29.295 15.12 29.565 ;
     RECT  2.16 29.835 15.12 30.105 ;
     RECT  2.16 30.375 15.12 30.645 ;
     RECT  2.16 30.915 15.12 31.185 ;
     RECT  2.16 31.455 15.12 31.725 ;
     RECT  2.16 31.995 15.12 32.265 ;
     RECT  2.16 32.535 15.12 32.805 ;
     RECT  2.16 33.075 15.12 33.345 ;
     RECT  2.16 33.615 15.12 33.885 ;
     RECT  2.16 34.155 15.12 34.425 ;
     RECT  2.16 34.695 15.12 34.965 ;
     RECT  2.16 35.235 15.12 35.505 ;
     RECT  2.16 35.775 15.12 36.045 ;
     RECT  2.16 36.315 15.12 36.585 ;
     RECT  2.16 36.855 15.12 37.125 ;
     RECT  2.16 37.395 15.12 37.665 ;
     RECT  2.16 37.935 15.12 38.205 ;
     RECT  2.16 38.475 15.12 38.745 ;
     RECT  2.16 39.015 15.12 39.285 ;
     RECT  2.16 39.555 15.12 39.825 ;
     RECT  2.16 40.095 15.12 40.365 ;
     RECT  2.16 40.635 15.12 40.905 ;
     RECT  2.16 41.175 15.12 41.445 ;
     RECT  2.16 41.715 15.12 41.985 ;
     RECT  2.16 42.255 15.12 42.525 ;
     RECT  2.16 42.795 15.12 43.065 ;
     RECT  2.16 43.335 15.12 43.605 ;
     RECT  2.16 43.875 15.12 44.145 ;
     RECT  2.16 44.415 15.12 44.685 ;
     RECT  2.16 44.955 15.12 45.225 ;
     RECT  2.16 45.495 15.12 45.765 ;
     RECT  2.16 46.035 15.12 46.305 ;
     RECT  2.16 46.575 15.12 46.845 ;
     RECT  2.16 47.115 15.12 47.385 ;
     RECT  2.16 47.655 15.12 47.925 ;
     RECT  2.16 48.195 15.12 48.465 ;
     RECT  2.16 48.735 15.12 49.005 ;
     RECT  2.16 49.275 15.12 49.545 ;
     RECT  2.16 49.815 15.12 50.085 ;
     RECT  2.16 50.355 15.12 50.625 ;
     RECT  2.16 50.895 15.12 51.165 ;
     RECT  2.16 51.435 15.12 51.705 ;
     RECT  2.16 51.975 15.12 52.245 ;
     RECT  2.16 52.515 15.12 52.785 ;
     RECT  2.16 53.055 15.12 53.325 ;
     RECT  2.16 53.595 15.12 53.865 ;
     RECT  2.16 54.135 15.12 54.405 ;
     RECT  2.16 54.675 15.12 54.945 ;
     RECT  2.16 55.215 15.12 55.485 ;
     RECT  2.16 55.755 15.12 56.025 ;
     RECT  2.16 56.295 15.12 56.565 ;
     RECT  2.16 56.835 15.12 57.105 ;
     RECT  2.16 57.375 15.12 57.645 ;
     RECT  2.16 57.915 15.12 58.185 ;
     RECT  2.16 58.455 15.12 58.725 ;
     RECT  2.16 58.995 15.12 59.265 ;
     RECT  2.16 59.535 15.12 59.805 ;
     RECT  2.16 60.075 15.12 60.345 ;
    LAYER M1 ;
     RECT  2.16 2.151 15.12 60.489 ;
    LAYER M2 ;
     RECT  0.211 3.888 0.311 3.906 ;
     RECT  0.211 5.58 0.311 5.598 ;
     RECT  0.211 12.528 0.311 12.546 ;
     RECT  0.211 15.381 0.311 15.399 ;
     RECT  0.211 22.941 0.311 22.959 ;
     RECT  0.211 23.751 0.311 23.769 ;
     RECT  0.211 25.641 0.311 25.659 ;
     RECT  0.211 33.786 0.311 33.804 ;
     RECT  0.211 34.551 0.311 34.992 ;
     RECT  0.211 35.748 0.311 35.766 ;
     RECT  0.211 37.872 0.311 37.89 ;
     RECT  0.211 40.104 0.311 40.428 ;
     RECT  0.211 45.774 0.311 45.792 ;
     RECT  0.211 46.854 0.311 46.872 ;
     RECT  0.211 50.526 0.311 50.544 ;
     RECT  0.211 57.186 0.311 57.87 ;
     RECT  0.211 59.31 0.311 59.328 ;
     RECT  0.211 8.82 0.347 8.838 ;
     RECT  0.211 51.444 0.347 51.462 ;
     RECT  0.311 57.186 0.347 57.204 ;
     RECT  0.355 3.276 0.491 3.294 ;
     RECT  0.355 56.34 0.491 56.358 ;
     RECT  0.463 2.034 0.535 2.052 ;
     RECT  0.211 26.604 0.535 27.36 ;
     RECT  0.211 52.992 0.535 53.01 ;
     RECT  0.535 13.032 0.635 13.194 ;
     RECT  0.571 12.096 0.671 12.114 ;
     RECT  0.535 32.076 1.147 32.094 ;
     RECT  1.147 32.004 1.175 32.094 ;
     RECT  0.535 52.992 1.219 53.586 ;
     RECT  1.219 52.992 1.255 54.09 ;
     RECT  0.535 1.998 2.16 2.052 ;
     RECT  0.211 6.822 2.16 6.84 ;
     RECT  0.211 7.902 2.16 7.92 ;
     RECT  0.535 9.63 2.16 9.648 ;
     RECT  0.635 13.032 2.16 13.05 ;
     RECT  0.319 14.22 2.16 14.238 ;
     RECT  0.319 15.264 2.16 15.282 ;
     RECT  0.535 16.884 2.16 16.902 ;
     RECT  0.211 18.702 2.16 18.72 ;
     RECT  0.535 26.604 2.16 27.9 ;
     RECT  1.175 32.004 2.16 32.022 ;
     RECT  0.535 37.476 2.16 37.494 ;
     RECT  0.211 38.646 2.16 38.664 ;
     RECT  0.311 40.104 2.16 40.122 ;
     RECT  0.211 43.65 2.16 43.668 ;
     RECT  2.155 45.432 2.16 45.45 ;
     RECT  0.535 47.862 2.16 47.88 ;
     RECT  1.255 52.992 2.16 54.702 ;
     RECT  0.535 55.8 2.16 55.818 ;
     RECT  2.16 1.998 6.187 60.489 ;
     RECT  6.187 1.962 6.727 60.489 ;
     RECT  6.727 1.962 6.907 60.534 ;
     RECT  6.907 1.926 7.015 60.534 ;
     RECT  7.015 1.926 7.591 60.57 ;
     RECT  7.591 1.881 8.807 60.57 ;
     RECT  8.807 1.881 8.879 60.534 ;
     RECT  8.879 1.881 9.167 60.489 ;
     RECT  9.167 1.926 9.239 60.489 ;
     RECT  9.239 2.034 12.271 60.489 ;
     RECT  12.271 1.998 15.12 60.489 ;
     RECT  15.12 1.998 15.431 60.3 ;
     RECT  15.431 1.998 15.467 59.904 ;
     RECT  15.467 1.998 15.503 19.53 ;
     RECT  15.503 1.998 16.007 19.062 ;
     RECT  15.467 20.286 16.007 59.904 ;
     RECT  16.007 20.286 16.043 27.63 ;
     RECT  16.007 1.998 16.511 2.214 ;
     RECT  16.007 3.546 16.511 8.154 ;
     RECT  16.007 9.126 16.511 16.326 ;
     RECT  16.007 17.316 16.511 17.334 ;
     RECT  16.043 21.906 16.511 27.63 ;
     RECT  16.007 28.656 16.511 47.844 ;
     RECT  16.007 48.978 16.511 56.214 ;
     RECT  16.007 59.166 16.511 59.904 ;
     RECT  16.511 1.998 16.547 2.016 ;
     RECT  16.511 3.852 16.547 6.174 ;
     RECT  16.511 7.056 16.547 8.154 ;
     RECT  16.511 9.126 16.547 9.144 ;
     RECT  16.511 9.936 16.547 12.654 ;
     RECT  16.511 15.066 16.547 16.164 ;
     RECT  16.007 18.162 16.547 18.486 ;
     RECT  16.043 20.286 16.547 20.754 ;
     RECT  16.511 22.086 16.547 23.31 ;
     RECT  16.511 24.21 16.547 26.964 ;
     RECT  16.511 28.656 16.547 33.444 ;
     RECT  16.511 34.236 16.547 36.504 ;
     RECT  16.511 37.368 16.547 45.054 ;
     RECT  16.511 46.386 16.547 47.574 ;
     RECT  16.511 48.978 16.547 52.074 ;
     RECT  16.511 52.992 16.547 55.746 ;
     RECT  16.007 57.15 16.547 58.41 ;
     RECT  16.511 59.616 16.547 59.904 ;
     RECT  16.547 5.202 16.583 5.22 ;
     RECT  16.547 6.048 16.583 6.066 ;
     RECT  16.547 7.128 16.583 7.146 ;
     RECT  16.547 15.498 16.583 16.128 ;
     RECT  16.547 26.37 16.583 26.694 ;
     RECT  16.547 29.916 16.583 30.06 ;
     RECT  16.547 31.734 16.583 31.752 ;
     RECT  16.547 32.616 16.583 33.066 ;
     RECT  16.547 38.286 16.583 38.304 ;
     RECT  16.547 41.796 16.583 41.814 ;
     RECT  16.547 42.876 16.583 43.434 ;
     RECT  16.547 49.626 16.583 49.644 ;
     RECT  16.547 50.706 16.583 51.228 ;
     RECT  16.547 52.992 16.583 53.01 ;
     RECT  16.547 57.726 16.583 58.14 ;
     RECT  16.547 3.888 16.619 3.906 ;
     RECT  16.583 16.11 16.619 16.128 ;
     RECT  16.583 26.37 16.619 26.388 ;
     RECT  16.583 50.706 16.619 50.724 ;
     RECT  16.547 11.376 17.087 11.394 ;
     RECT  16.547 22.212 17.087 22.23 ;
     RECT  16.583 33.048 17.087 33.066 ;
     RECT  16.583 58.122 17.087 58.14 ;
    LAYER M3 ;
     RECT  7.596 1.876 7.614 1.921 ;
     RECT  9.144 1.876 9.162 1.921 ;
     RECT  6.912 1.921 7.614 1.957 ;
     RECT  9.144 1.921 9.234 1.993 ;
     RECT  0.54 1.993 0.558 2.029 ;
     RECT  12.276 1.993 12.294 2.029 ;
     RECT  11.7 2.029 12.294 2.065 ;
     RECT  8.928 1.993 9.234 2.101 ;
     RECT  4.5 2.065 4.518 2.143 ;
     RECT  8.712 2.101 9.234 2.191 ;
     RECT  13.215 2.143 13.305 2.191 ;
     RECT  14.076 2.101 14.094 2.191 ;
     RECT  16.524 1.993 16.542 2.191 ;
     RECT  2.415 2.143 2.505 2.203 ;
     RECT  4.5 2.143 5.205 2.219 ;
     RECT  11.7 2.065 12.366 2.219 ;
     RECT  6.192 1.957 7.974 2.227 ;
     RECT  8.712 2.191 9.306 2.227 ;
     RECT  16.488 2.191 16.542 2.263 ;
     RECT  0.468 2.029 0.558 2.299 ;
     RECT  15.984 2.263 16.542 2.333 ;
     RECT  5.115 2.219 5.205 2.371 ;
     RECT  6.192 2.227 9.414 2.371 ;
     RECT  15.984 2.333 16.002 2.371 ;
     RECT  2.304 2.203 2.505 2.413 ;
     RECT  3.24 2.263 3.258 2.413 ;
     RECT  10.515 2.143 10.605 2.413 ;
     RECT  15.408 2.371 16.002 2.461 ;
     RECT  11.988 2.219 12.042 2.489 ;
     RECT  0.252 2.299 0.558 2.539 ;
     RECT  2.304 2.413 3.258 2.605 ;
     RECT  3.996 2.299 4.194 2.605 ;
     RECT  13.215 2.191 14.094 2.641 ;
     RECT  14.832 2.461 16.002 2.641 ;
     RECT  13.215 2.641 16.002 2.731 ;
     RECT  0.252 2.539 0.594 2.765 ;
     RECT  5.115 2.371 9.414 2.767 ;
     RECT  5.115 2.767 9.702 2.803 ;
     RECT  10.515 2.413 10.797 2.803 ;
     RECT  0.252 2.765 0.486 2.861 ;
     RECT  5.115 2.803 10.797 2.909 ;
     RECT  5.115 2.909 9.702 2.957 ;
     RECT  12.024 2.489 12.042 3.001 ;
     RECT  13.104 2.731 16.002 3.001 ;
     RECT  2.304 2.605 4.194 3.019 ;
     RECT  5.115 2.957 9.378 3.019 ;
     RECT  12.024 3.001 16.002 3.137 ;
     RECT  0.324 2.861 0.486 3.341 ;
     RECT  0.324 3.341 0.342 3.389 ;
     RECT  14.832 3.137 16.002 3.407 ;
     RECT  10.515 2.909 10.797 3.577 ;
     RECT  16.488 3.541 16.506 3.581 ;
     RECT  12.024 3.137 12.366 3.721 ;
     RECT  2.304 3.019 9.378 3.787 ;
     RECT  16.524 3.691 16.542 3.787 ;
     RECT  11.592 3.721 12.366 3.839 ;
     RECT  2.304 3.787 9.45 3.847 ;
     RECT  16.524 3.787 16.614 3.911 ;
     RECT  11.988 3.839 12.294 3.947 ;
     RECT  13.215 3.137 14.094 4.019 ;
     RECT  0.216 3.868 0.306 4.109 ;
     RECT  0.252 4.109 0.306 4.157 ;
     RECT  14.832 3.407 15.426 4.189 ;
     RECT  2.304 3.847 9.594 4.289 ;
     RECT  6.156 4.289 9.594 4.315 ;
     RECT  13.215 4.019 13.986 4.351 ;
     RECT  13.104 4.351 13.986 4.397 ;
     RECT  14.724 4.189 15.426 4.415 ;
     RECT  2.304 4.289 5.397 4.523 ;
     RECT  3.96 4.523 5.397 4.685 ;
     RECT  13.215 4.397 13.986 4.685 ;
     RECT  10.515 3.577 10.818 4.693 ;
     RECT  14.832 4.415 15.426 4.699 ;
     RECT  16.524 3.911 16.542 4.699 ;
     RECT  14.832 4.699 16.542 4.793 ;
     RECT  11.988 3.947 12.006 4.801 ;
     RECT  11.952 4.801 12.006 4.891 ;
     RECT  6.156 4.315 9.666 4.927 ;
     RECT  10.515 4.693 10.854 4.927 ;
     RECT  11.952 4.891 12.042 5.063 ;
     RECT  11.952 5.063 11.97 5.099 ;
     RECT  10.515 4.927 10.926 5.161 ;
     RECT  16.524 4.793 16.542 5.197 ;
     RECT  5.004 4.685 5.397 5.227 ;
     RECT  6.156 4.927 9.774 5.227 ;
     RECT  16.524 5.197 16.578 5.261 ;
     RECT  5.004 5.227 9.774 5.269 ;
     RECT  10.515 5.161 11.61 5.269 ;
     RECT  5.004 5.269 11.61 5.309 ;
     RECT  5.004 5.309 11.034 5.459 ;
     RECT  7.128 5.459 11.034 5.501 ;
     RECT  3.96 4.685 4.086 5.563 ;
     RECT  0.252 4.157 0.27 5.575 ;
     RECT  13.215 4.685 13.497 5.575 ;
     RECT  5.004 5.459 6.354 5.603 ;
     RECT  2.304 4.523 3.222 5.611 ;
     RECT  3.96 5.563 4.122 5.611 ;
     RECT  0.216 5.575 0.306 5.789 ;
     RECT  0.252 5.789 0.306 5.837 ;
     RECT  2.304 5.611 4.122 5.845 ;
     RECT  2.304 5.845 4.266 5.881 ;
     RECT  5.004 5.603 5.397 5.881 ;
     RECT  13.215 5.575 14.058 5.881 ;
     RECT  14.832 4.793 15.426 5.881 ;
     RECT  6.12 5.603 6.354 5.909 ;
     RECT  13.215 5.881 15.426 5.971 ;
     RECT  10.515 5.501 11.034 6.043 ;
     RECT  12.42 5.971 15.426 6.043 ;
     RECT  16.524 5.261 16.542 6.043 ;
     RECT  6.228 5.909 6.354 6.232 ;
     RECT  7.128 5.501 9.774 6.232 ;
     RECT  12.42 6.043 16.578 6.269 ;
     RECT  6.228 6.232 9.774 6.385 ;
     RECT  10.515 6.043 11.43 6.385 ;
     RECT  6.228 6.385 11.43 6.605 ;
     RECT  0.252 5.837 0.27 6.653 ;
     RECT  2.304 5.881 5.397 6.655 ;
     RECT  12.42 6.269 16.506 6.781 ;
     RECT  6.228 6.605 10.854 6.809 ;
     RECT  2.304 6.655 5.454 6.817 ;
     RECT  6.228 6.809 9.738 6.817 ;
     RECT  2.268 6.817 9.738 6.917 ;
     RECT  0.216 6.817 0.234 6.941 ;
     RECT  12.384 6.781 16.506 6.961 ;
     RECT  11.988 6.961 16.506 7.051 ;
     RECT  11.988 7.051 16.542 7.115 ;
     RECT  16.488 7.115 16.542 7.123 ;
     RECT  16.488 7.123 16.578 7.229 ;
     RECT  11.988 7.115 15.426 7.259 ;
     RECT  12.456 7.259 15.426 7.349 ;
     RECT  16.488 7.229 16.542 7.349 ;
     RECT  2.304 6.917 9.738 7.385 ;
     RECT  10.515 6.809 10.854 7.393 ;
     RECT  0.252 7.531 0.27 7.709 ;
     RECT  10.515 7.393 10.926 7.799 ;
     RECT  12.456 7.349 13.986 7.889 ;
     RECT  2.34 7.385 9.738 7.897 ;
     RECT  10.515 7.799 10.797 7.897 ;
     RECT  0.216 7.819 0.234 7.925 ;
     RECT  2.34 7.897 10.797 7.925 ;
     RECT  16.524 7.349 16.542 8.159 ;
     RECT  14.832 7.349 15.426 8.443 ;
     RECT  13.14 7.889 13.986 8.509 ;
     RECT  14.832 8.443 16.002 8.509 ;
     RECT  2.34 7.925 5.598 8.539 ;
     RECT  6.372 7.925 10.797 8.707 ;
     RECT  2.304 8.539 5.598 8.735 ;
     RECT  0.396 8.635 0.414 8.779 ;
     RECT  6.372 8.707 10.854 8.779 ;
     RECT  12.024 8.041 12.294 8.779 ;
     RECT  13.14 8.509 16.002 8.779 ;
     RECT  0.216 8.779 0.414 8.813 ;
     RECT  6.372 8.779 16.002 8.816 ;
     RECT  0.216 8.813 0.342 8.843 ;
     RECT  0.252 8.843 0.342 8.861 ;
     RECT  6.372 8.816 11.97 8.969 ;
     RECT  12.816 8.816 16.002 9.005 ;
     RECT  3.996 8.735 5.598 9.067 ;
     RECT  6.372 8.969 10.854 9.067 ;
     RECT  13.215 9.005 16.002 9.077 ;
     RECT  14.544 9.077 16.002 9.121 ;
     RECT  11.916 8.969 11.97 9.293 ;
     RECT  14.544 9.121 16.542 9.347 ;
     RECT  1.368 9.307 1.386 9.355 ;
     RECT  13.215 9.077 13.59 9.509 ;
     RECT  11.952 9.293 11.97 9.545 ;
     RECT  1.152 9.355 1.386 9.581 ;
     RECT  3.996 9.067 10.854 9.581 ;
     RECT  0.252 8.861 0.27 9.625 ;
     RECT  1.296 9.581 1.314 9.629 ;
     RECT  14.796 9.347 16.542 9.689 ;
     RECT  0.252 9.625 0.558 9.725 ;
     RECT  13.215 9.509 13.497 9.739 ;
     RECT  3.996 9.581 9.702 9.821 ;
     RECT  2.304 8.735 3.258 9.859 ;
     RECT  3.996 9.821 9.666 9.859 ;
     RECT  10.515 9.581 10.854 9.869 ;
     RECT  0.252 9.725 0.306 10.109 ;
     RECT  2.304 9.859 9.666 10.109 ;
     RECT  2.304 10.109 5.397 10.157 ;
     RECT  12.564 9.739 13.497 10.157 ;
     RECT  2.304 10.157 3.222 10.165 ;
     RECT  14.796 9.689 15.426 10.165 ;
     RECT  0.288 10.109 0.306 10.205 ;
     RECT  2.268 10.165 3.222 10.253 ;
     RECT  14.652 10.165 15.426 10.349 ;
     RECT  13.215 10.157 13.497 10.471 ;
     RECT  11.988 10.363 12.006 10.499 ;
     RECT  14.652 10.349 14.67 10.499 ;
     RECT  10.515 9.869 10.797 10.633 ;
     RECT  15.408 10.349 15.426 10.669 ;
     RECT  16.488 9.689 16.542 10.669 ;
     RECT  10.404 10.633 10.797 10.733 ;
     RECT  10.515 10.733 10.797 10.741 ;
     RECT  13.215 10.471 13.878 10.867 ;
     RECT  3.96 10.157 5.397 10.891 ;
     RECT  13.215 10.867 14.526 10.891 ;
     RECT  2.304 10.253 3.222 10.939 ;
     RECT  3.96 10.891 5.454 10.939 ;
     RECT  2.304 10.939 5.454 10.975 ;
     RECT  6.228 10.109 9.666 10.975 ;
     RECT  2.304 10.975 9.666 11.129 ;
     RECT  1.152 10.987 1.17 11.131 ;
     RECT  3.996 11.129 9.666 11.213 ;
     RECT  1.152 11.131 1.278 11.261 ;
     RECT  12.888 10.891 14.526 11.281 ;
     RECT  15.408 10.669 16.542 11.281 ;
     RECT  12.888 11.281 16.542 11.371 ;
     RECT  11.736 11.227 11.754 11.399 ;
     RECT  12.852 11.371 17.082 11.453 ;
     RECT  10.515 10.741 10.854 11.641 ;
     RECT  4.032 11.213 9.666 11.669 ;
     RECT  12.852 11.453 16.542 11.789 ;
     RECT  12.852 11.789 14.562 11.911 ;
     RECT  0.252 11.035 0.27 12.043 ;
     RECT  4.068 11.669 9.666 12.055 ;
     RECT  0.252 12.043 0.666 12.119 ;
     RECT  0.252 12.119 0.594 12.128 ;
     RECT  10.515 11.641 11.43 12.317 ;
     RECT  15.408 11.789 16.542 12.323 ;
     RECT  0.252 12.128 0.306 12.379 ;
     RECT  12.456 11.911 14.562 12.479 ;
     RECT  4.068 12.055 9.774 12.487 ;
     RECT  10.515 12.317 10.797 12.487 ;
     RECT  0.216 12.379 0.306 12.551 ;
     RECT  2.304 11.129 3.222 12.559 ;
     RECT  3.96 12.487 10.797 12.559 ;
     RECT  13.215 12.479 14.562 12.571 ;
     RECT  12.24 12.631 12.258 12.721 ;
     RECT  12.168 12.721 12.258 12.749 ;
     RECT  2.304 12.559 10.797 12.797 ;
     RECT  12.168 12.749 12.186 12.829 ;
     RECT  11.52 12.829 12.186 12.893 ;
     RECT  2.304 12.797 5.397 13.019 ;
     RECT  6.264 12.797 10.797 13.019 ;
     RECT  11.52 12.893 12.042 13.019 ;
     RECT  0.252 12.551 0.306 13.027 ;
     RECT  15.984 12.323 16.542 13.133 ;
     RECT  0.252 13.027 0.558 13.147 ;
     RECT  13.215 12.571 14.85 13.195 ;
     RECT  15.984 13.133 16.506 13.195 ;
     RECT  0.252 13.147 0.63 13.199 ;
     RECT  0.252 13.199 0.558 13.229 ;
     RECT  6.372 13.019 10.797 13.387 ;
     RECT  13.215 13.195 16.506 13.667 ;
     RECT  4.032 13.019 5.397 13.675 ;
     RECT  13.215 13.667 15.462 13.711 ;
     RECT  4.032 13.675 5.562 13.819 ;
     RECT  6.372 13.387 11.394 13.819 ;
     RECT  13.14 13.711 15.462 13.829 ;
     RECT  4.032 13.819 11.43 13.865 ;
     RECT  13.14 13.829 13.497 13.915 ;
     RECT  4.032 13.865 4.194 13.963 ;
     RECT  5.115 13.865 10.797 14.135 ;
     RECT  0.252 13.229 0.27 14.215 ;
     RECT  2.304 13.019 3.222 14.215 ;
     RECT  3.996 13.963 4.194 14.215 ;
     RECT  13.104 13.915 13.497 14.251 ;
     RECT  0.252 14.215 0.342 14.285 ;
     RECT  12.816 14.251 13.497 14.369 ;
     RECT  14.472 13.829 15.462 14.443 ;
     RECT  16.488 13.667 16.506 14.443 ;
     RECT  13.104 14.369 13.497 14.611 ;
     RECT  14.472 14.443 16.506 14.611 ;
     RECT  13.104 14.611 16.506 14.731 ;
     RECT  2.304 14.215 4.194 14.791 ;
     RECT  5.115 14.135 9.666 14.791 ;
     RECT  2.304 14.791 9.666 14.875 ;
     RECT  13.104 14.731 16.542 14.945 ;
     RECT  12.168 15.025 12.186 15.179 ;
     RECT  0.252 14.285 0.27 15.259 ;
     RECT  14.832 14.945 16.542 15.259 ;
     RECT  13.104 14.945 13.842 15.295 ;
     RECT  0.252 15.259 0.342 15.307 ;
     RECT  0.216 15.307 0.342 15.404 ;
     RECT  2.304 14.875 9.738 15.421 ;
     RECT  10.515 14.135 10.797 15.421 ;
     RECT  0.252 15.404 0.342 15.533 ;
     RECT  14.832 15.259 16.578 15.533 ;
     RECT  2.304 15.421 10.797 15.581 ;
     RECT  0.252 15.533 0.27 15.821 ;
     RECT  12.888 15.295 13.842 15.979 ;
     RECT  12.888 15.979 14.022 16.027 ;
     RECT  12.6 16.027 14.022 16.033 ;
     RECT  14.832 15.533 15.426 16.033 ;
     RECT  16.488 15.533 16.578 16.105 ;
     RECT  16.488 16.105 16.614 16.253 ;
     RECT  12.6 16.033 15.426 16.259 ;
     RECT  11.52 16.267 11.538 16.304 ;
     RECT  2.304 15.581 2.862 16.315 ;
     RECT  3.744 15.581 10.797 16.315 ;
     RECT  16.488 16.253 16.506 16.349 ;
     RECT  2.304 16.315 10.797 16.363 ;
     RECT  13.215 16.259 15.426 16.411 ;
     RECT  2.304 16.363 10.89 16.541 ;
     RECT  13.215 16.411 15.462 16.771 ;
     RECT  12.456 16.609 12.474 16.795 ;
     RECT  0.252 16.555 0.27 16.879 ;
     RECT  2.304 16.541 10.854 16.979 ;
     RECT  11.952 16.795 12.474 17.041 ;
     RECT  0.252 16.879 0.558 17.069 ;
     RECT  11.592 17.041 12.474 17.069 ;
     RECT  11.592 17.069 12.366 17.213 ;
     RECT  13.215 16.771 16.002 17.227 ;
     RECT  13.215 17.227 16.506 17.339 ;
     RECT  13.215 17.339 16.002 17.789 ;
     RECT  0.252 17.069 0.27 17.837 ;
     RECT  11.736 17.213 12.366 17.879 ;
     RECT  12.348 17.879 12.366 18.149 ;
     RECT  13.215 17.789 15.498 18.301 ;
     RECT  2.304 16.979 10.797 18.329 ;
     RECT  12.528 18.301 15.498 18.419 ;
     RECT  12.78 18.419 15.498 18.491 ;
     RECT  16.524 18.091 16.542 18.491 ;
     RECT  2.415 18.329 10.797 18.523 ;
     RECT  2.415 18.523 11.106 18.563 ;
     RECT  0.252 18.619 0.27 18.697 ;
     RECT  4.068 18.563 11.106 18.761 ;
     RECT  14.256 18.491 15.498 18.769 ;
     RECT  0.216 18.697 0.27 18.941 ;
     RECT  14.256 18.769 16.002 19.133 ;
     RECT  2.415 18.563 3.33 19.139 ;
     RECT  0.288 18.955 0.306 19.181 ;
     RECT  12.78 18.491 13.497 19.237 ;
     RECT  14.256 19.133 15.498 19.237 ;
     RECT  2.415 19.139 3.222 19.435 ;
     RECT  12.78 19.237 15.498 19.507 ;
     RECT  12.312 19.507 15.498 19.769 ;
     RECT  12.384 19.769 13.95 19.913 ;
     RECT  2.304 19.435 3.222 19.963 ;
     RECT  12.384 19.913 13.497 20.093 ;
     RECT  2.268 19.963 3.222 20.119 ;
     RECT  4.068 18.761 10.797 20.119 ;
     RECT  2.268 20.119 10.797 20.309 ;
     RECT  14.832 19.769 15.498 20.347 ;
     RECT  16.524 20.251 16.542 20.347 ;
     RECT  0.324 20.155 0.342 20.381 ;
     RECT  2.268 20.309 3.078 20.492 ;
     RECT  14.832 20.347 16.542 20.551 ;
     RECT  12.816 20.093 13.497 20.659 ;
     RECT  14.4 20.551 16.542 20.659 ;
     RECT  0.252 20.635 0.27 20.813 ;
     RECT  12.816 20.659 16.542 20.909 ;
     RECT  3.816 20.309 10.797 20.971 ;
     RECT  11.952 20.659 11.97 20.971 ;
     RECT  2.304 20.492 3.078 21.199 ;
     RECT  3.816 20.971 11.97 21.199 ;
     RECT  2.304 21.199 11.97 21.299 ;
     RECT  3.888 21.299 11.97 21.403 ;
     RECT  12.816 20.909 16.038 21.403 ;
     RECT  3.888 21.403 16.038 21.533 ;
     RECT  1.152 21.403 1.17 21.581 ;
     RECT  3.888 21.533 15.426 21.659 ;
     RECT  12.744 21.659 15.426 21.731 ;
     RECT  1.296 21.691 1.314 21.821 ;
     RECT  0.288 21.691 0.306 21.835 ;
     RECT  13.215 21.731 15.426 21.929 ;
     RECT  0.288 21.835 0.414 21.965 ;
     RECT  16.488 21.883 16.506 22.027 ;
     RECT  3.888 21.659 12.006 22.109 ;
     RECT  3.888 22.109 11.826 22.199 ;
     RECT  13.215 21.929 13.806 22.199 ;
     RECT  14.544 21.929 15.426 22.199 ;
     RECT  16.488 22.027 16.542 22.207 ;
     RECT  16.488 22.207 17.082 22.253 ;
     RECT  2.304 21.299 3.078 22.279 ;
     RECT  3.888 22.199 11.466 22.279 ;
     RECT  13.215 22.199 13.698 22.507 ;
     RECT  0.288 21.965 0.342 22.541 ;
     RECT  2.304 22.279 11.466 22.621 ;
     RECT  2.268 22.621 11.466 22.685 ;
     RECT  14.688 22.199 15.426 22.738 ;
     RECT  12.564 22.507 13.698 22.739 ;
     RECT  14.688 22.738 15.462 22.811 ;
     RECT  14.796 22.811 15.462 22.843 ;
     RECT  16.488 22.253 16.542 22.843 ;
     RECT  0.288 22.541 0.306 22.924 ;
     RECT  2.304 22.685 11.466 23.009 ;
     RECT  5.115 23.009 11.466 23.035 ;
     RECT  14.796 22.843 16.542 23.153 ;
     RECT  5.115 23.035 12.006 23.279 ;
     RECT  12.816 22.739 13.698 23.279 ;
     RECT  7.2 23.279 10.854 23.36 ;
     RECT  10.188 23.36 10.854 23.423 ;
     RECT  13.068 23.279 13.698 23.431 ;
     RECT  13.068 23.431 13.806 23.521 ;
     RECT  2.304 23.009 4.302 23.549 ;
     RECT  11.988 23.279 12.006 23.729 ;
     RECT  4.104 23.549 4.302 23.899 ;
     RECT  5.115 23.279 6.426 23.899 ;
     RECT  13.068 23.521 14.058 23.899 ;
     RECT  14.832 23.153 16.542 23.899 ;
     RECT  0.216 22.924 0.306 24.029 ;
     RECT  10.296 23.423 10.854 24.061 ;
     RECT  4.104 23.899 6.426 24.097 ;
     RECT  7.2 23.36 9.414 24.097 ;
     RECT  10.296 24.061 11.43 24.125 ;
     RECT  13.068 23.899 16.542 24.133 ;
     RECT  4.104 24.097 9.414 24.187 ;
     RECT  4.104 24.187 9.486 24.205 ;
     RECT  10.296 24.125 10.797 24.205 ;
     RECT  12.528 24.133 16.542 24.221 ;
     RECT  0.252 24.029 0.306 24.331 ;
     RECT  12.528 24.221 15.462 24.359 ;
     RECT  12.528 24.359 15.426 24.365 ;
     RECT  0.252 24.331 0.414 24.461 ;
     RECT  4.104 24.205 10.797 24.475 ;
     RECT  2.304 23.549 3.222 24.637 ;
     RECT  4.068 24.475 10.797 24.637 ;
     RECT  11.952 24.475 11.97 24.701 ;
     RECT  16.488 24.221 16.542 24.899 ;
     RECT  2.304 24.637 10.797 24.955 ;
     RECT  2.196 24.955 10.797 25.007 ;
     RECT  12.888 24.365 15.426 25.079 ;
     RECT  13.215 25.079 15.426 25.241 ;
     RECT  0.252 24.461 0.27 25.291 ;
     RECT  0.252 25.291 0.306 25.339 ;
     RECT  14.688 25.241 15.426 25.411 ;
     RECT  13.215 25.241 13.914 25.475 ;
     RECT  12.24 25.141 12.402 25.511 ;
     RECT  2.304 25.007 10.797 25.517 ;
     RECT  13.215 25.475 13.842 25.547 ;
     RECT  14.688 25.411 15.462 25.565 ;
     RECT  0.216 25.339 0.306 25.676 ;
     RECT  16.524 24.899 16.542 25.708 ;
     RECT  2.304 25.517 9.774 25.963 ;
     RECT  16.488 25.708 16.542 25.963 ;
     RECT  2.268 25.963 9.774 26.015 ;
     RECT  10.515 25.517 10.797 26.059 ;
     RECT  13.215 25.547 13.497 26.059 ;
     RECT  16.452 25.963 16.542 26.155 ;
     RECT  14.688 25.565 15.426 26.221 ;
     RECT  0.252 25.676 0.306 26.251 ;
     RECT  2.304 26.015 9.774 26.257 ;
     RECT  10.515 26.059 10.854 26.257 ;
     RECT  16.452 26.155 16.614 26.393 ;
     RECT  11.88 25.861 11.898 26.395 ;
     RECT  13.212 26.059 13.497 26.395 ;
     RECT  14.256 26.221 15.426 26.428 ;
     RECT  2.304 26.257 10.854 26.491 ;
     RECT  11.88 26.395 13.497 26.491 ;
     RECT  0.252 26.251 0.342 26.525 ;
     RECT  2.304 26.491 13.497 26.527 ;
     RECT  14.256 26.428 15.462 26.527 ;
     RECT  0.252 26.525 0.27 26.587 ;
     RECT  16.452 26.393 16.578 26.699 ;
     RECT  2.304 26.527 15.462 26.717 ;
     RECT  15.372 26.717 15.462 26.761 ;
     RECT  16.452 26.699 16.542 26.761 ;
     RECT  0.216 26.587 0.27 27.403 ;
     RECT  15.372 26.761 16.542 27.437 ;
     RECT  2.304 26.717 14.382 27.481 ;
     RECT  0.216 27.403 0.306 27.485 ;
     RECT  2.304 27.481 14.562 27.509 ;
     RECT  2.304 27.509 11.466 27.635 ;
     RECT  15.372 27.437 16.506 27.635 ;
     RECT  12.6 27.509 14.562 27.679 ;
     RECT  15.372 27.635 16.002 27.679 ;
     RECT  2.415 27.635 11.466 27.779 ;
     RECT  0.252 27.485 0.306 27.877 ;
     RECT  0.252 27.877 0.558 27.965 ;
     RECT  2.415 27.779 11.43 28.013 ;
     RECT  0.252 27.965 0.27 28.109 ;
     RECT  12.6 27.679 16.002 28.291 ;
     RECT  2.415 28.013 10.854 28.363 ;
     RECT  2.304 28.363 10.854 28.451 ;
     RECT  12.168 28.291 16.002 28.645 ;
     RECT  12.168 28.645 16.542 28.679 ;
     RECT  12.564 28.679 16.542 28.715 ;
     RECT  16.488 28.715 16.542 28.949 ;
     RECT  2.304 28.451 5.562 29.021 ;
     RECT  12.564 28.715 15.462 29.309 ;
     RECT  4.032 29.021 5.562 29.323 ;
     RECT  6.372 28.451 10.854 29.323 ;
     RECT  4.032 29.323 10.854 29.399 ;
     RECT  5.112 29.399 10.854 29.731 ;
     RECT  2.304 29.021 3.222 29.755 ;
     RECT  4.032 29.399 4.338 29.755 ;
     RECT  16.524 28.949 16.542 29.755 ;
     RECT  2.304 29.755 4.338 29.795 ;
     RECT  5.112 29.731 11.43 29.795 ;
     RECT  5.115 29.795 11.43 29.875 ;
     RECT  0.252 29.419 0.27 29.947 ;
     RECT  0.252 29.947 0.414 30.077 ;
     RECT  16.524 29.755 16.578 30.125 ;
     RECT  12.924 29.309 15.426 30.139 ;
     RECT  12.564 30.139 15.426 30.283 ;
     RECT  5.115 29.875 11.538 30.343 ;
     RECT  12.528 30.283 15.426 30.343 ;
     RECT  1.368 30.331 1.386 30.379 ;
     RECT  5.115 30.343 11.646 30.415 ;
     RECT  12.528 30.343 15.462 30.415 ;
     RECT  1.296 30.379 1.386 30.427 ;
     RECT  1.152 30.427 1.386 30.461 ;
     RECT  2.415 29.795 4.338 30.523 ;
     RECT  5.115 30.415 15.462 30.541 ;
     RECT  16.524 30.125 16.542 30.541 ;
     RECT  1.152 30.461 1.314 30.557 ;
     RECT  2.304 30.523 4.338 30.569 ;
     RECT  4.032 30.569 4.338 30.577 ;
     RECT  5.115 30.541 16.542 30.577 ;
     RECT  4.032 30.577 16.542 30.605 ;
     RECT  4.032 30.605 13.914 30.653 ;
     RECT  14.796 30.605 16.542 30.677 ;
     RECT  0.252 30.077 0.342 30.701 ;
     RECT  1.296 30.557 1.314 30.701 ;
     RECT  14.832 30.677 16.542 30.845 ;
     RECT  4.032 30.653 10.926 30.893 ;
     RECT  0.252 30.701 0.27 30.941 ;
     RECT  14.832 30.845 15.462 31.109 ;
     RECT  2.304 30.569 3.222 31.339 ;
     RECT  4.032 30.893 4.122 31.339 ;
     RECT  11.7 30.653 13.914 31.621 ;
     RECT  14.832 31.109 15.426 31.621 ;
     RECT  5.076 30.893 10.926 31.649 ;
     RECT  6.228 31.649 10.926 31.657 ;
     RECT  11.7 31.621 15.426 31.657 ;
     RECT  0.396 31.579 0.414 31.675 ;
     RECT  16.488 30.845 16.542 31.729 ;
     RECT  6.228 31.657 15.426 31.757 ;
     RECT  2.304 31.339 4.122 31.801 ;
     RECT  5.076 31.649 5.49 31.801 ;
     RECT  0.288 31.675 0.414 31.805 ;
     RECT  6.228 31.757 14.85 31.829 ;
     RECT  6.228 31.829 13.698 31.919 ;
     RECT  1.152 31.999 1.17 32.011 ;
     RECT  0.324 31.805 0.414 32.071 ;
     RECT  1.152 32.011 1.278 32.071 ;
     RECT  16.488 31.729 16.578 32.071 ;
     RECT  2.304 31.801 5.49 32.189 ;
     RECT  11.808 31.919 13.698 32.189 ;
     RECT  14.832 31.829 14.85 32.195 ;
     RECT  12.384 32.189 13.698 32.261 ;
     RECT  12.492 32.261 13.698 32.369 ;
     RECT  5.115 32.189 5.49 32.467 ;
     RECT  6.228 31.919 10.854 32.467 ;
     RECT  13.032 32.369 13.698 32.587 ;
     RECT  0.324 32.071 1.278 32.635 ;
     RECT  0.252 32.635 1.278 32.813 ;
     RECT  15.984 32.071 16.578 32.845 ;
     RECT  0.54 32.813 1.278 32.861 ;
     RECT  5.115 32.467 10.854 32.881 ;
     RECT  15.408 32.845 16.578 32.909 ;
     RECT  13.032 32.587 14.49 32.999 ;
     RECT  2.304 32.189 4.122 33.007 ;
     RECT  5.115 32.881 11.178 33.007 ;
     RECT  13.215 32.999 14.49 33.043 ;
     RECT  16.488 32.909 16.578 33.043 ;
     RECT  2.304 33.007 11.178 33.079 ;
     RECT  16.488 33.043 17.082 33.101 ;
     RECT  2.304 33.079 11.358 33.151 ;
     RECT  0.54 32.861 0.558 33.197 ;
     RECT  2.304 33.151 11.43 33.269 ;
     RECT  3.96 33.269 10.926 33.449 ;
     RECT  3.96 33.449 10.854 33.539 ;
     RECT  0.288 33.595 0.306 33.643 ;
     RECT  3.96 33.539 10.797 33.683 ;
     RECT  13.215 33.043 14.85 33.781 ;
     RECT  0.216 33.643 0.306 33.809 ;
     RECT  12.564 33.781 14.85 33.809 ;
     RECT  14.688 33.809 14.85 33.835 ;
     RECT  12.564 33.809 13.878 33.917 ;
     RECT  11.988 33.931 12.006 34.079 ;
     RECT  2.304 33.269 3.222 34.195 ;
     RECT  3.96 33.683 9.774 34.195 ;
     RECT  12.816 33.917 13.878 34.349 ;
     RECT  16.488 33.101 16.542 34.349 ;
     RECT  10.515 33.683 10.797 34.393 ;
     RECT  10.515 34.393 10.854 34.501 ;
     RECT  0.252 33.809 0.27 34.54 ;
     RECT  13.215 34.349 13.878 34.591 ;
     RECT  14.688 33.835 15.426 34.591 ;
     RECT  2.304 34.195 9.774 34.603 ;
     RECT  10.515 34.501 10.926 34.651 ;
     RECT  10.515 34.651 11.43 34.691 ;
     RECT  10.515 34.691 10.926 34.727 ;
     RECT  10.515 34.727 10.854 34.733 ;
     RECT  2.268 34.603 9.774 34.861 ;
     RECT  10.515 34.733 10.797 34.861 ;
     RECT  13.215 34.591 15.426 35.131 ;
     RECT  13.104 35.131 15.426 35.159 ;
     RECT  11.988 35.167 12.006 35.213 ;
     RECT  2.268 34.861 10.797 35.231 ;
     RECT  2.268 35.231 3.258 35.303 ;
     RECT  0.216 34.54 0.306 35.323 ;
     RECT  15.408 35.159 15.426 35.371 ;
     RECT  13.104 35.159 14.346 35.401 ;
     RECT  16.524 34.349 16.542 35.437 ;
     RECT  4.068 35.231 10.797 35.473 ;
     RECT  15.408 35.371 15.462 35.563 ;
     RECT  0.216 35.323 0.378 35.837 ;
     RECT  4.068 35.473 10.926 35.885 ;
     RECT  2.304 35.303 3.258 35.977 ;
     RECT  4.068 35.885 5.49 35.977 ;
     RECT  12.384 35.401 14.346 35.977 ;
     RECT  15.408 35.563 15.498 35.977 ;
     RECT  16.488 35.437 16.542 35.977 ;
     RECT  0.216 35.837 0.342 35.981 ;
     RECT  6.336 35.885 10.926 36.049 ;
     RECT  6.336 36.049 11.07 36.085 ;
     RECT  2.304 35.977 5.49 36.125 ;
     RECT  12.384 35.977 16.542 36.383 ;
     RECT  2.304 36.125 4.194 36.461 ;
     RECT  16.488 36.383 16.542 36.509 ;
     RECT  12.384 36.383 15.462 36.571 ;
     RECT  11.988 36.571 15.462 36.589 ;
     RECT  6.336 36.085 11.142 36.625 ;
     RECT  11.952 36.589 15.462 36.625 ;
     RECT  0.252 35.981 0.342 36.653 ;
     RECT  6.336 36.625 15.462 36.751 ;
     RECT  2.304 36.461 2.697 36.763 ;
     RECT  6.264 36.751 15.462 36.851 ;
     RECT  3.636 36.461 4.194 36.859 ;
     RECT  4.968 36.125 5.49 36.859 ;
     RECT  2.268 36.763 2.697 36.887 ;
     RECT  6.264 36.851 10.818 36.893 ;
     RECT  3.636 36.859 5.49 36.895 ;
     RECT  6.264 36.893 10.797 36.895 ;
     RECT  11.952 36.851 15.462 36.941 ;
     RECT  12.276 36.941 15.426 37.049 ;
     RECT  16.488 36.509 16.506 37.049 ;
     RECT  1.44 37.195 1.458 37.291 ;
     RECT  2.304 36.887 2.697 37.363 ;
     RECT  3.636 36.895 10.797 37.363 ;
     RECT  1.368 37.291 1.458 37.373 ;
     RECT  1.368 37.373 1.386 37.387 ;
     RECT  1.152 37.387 1.386 37.421 ;
     RECT  0.324 36.653 0.342 37.471 ;
     RECT  1.152 37.421 1.17 37.471 ;
     RECT  2.304 37.363 10.797 37.589 ;
     RECT  13.032 37.049 15.426 37.589 ;
     RECT  13.032 37.589 14.85 37.625 ;
     RECT  0.324 37.471 1.17 37.661 ;
     RECT  11.916 37.669 12.186 37.705 ;
     RECT  2.304 37.589 9.666 37.769 ;
     RECT  11.592 37.705 12.186 37.831 ;
     RECT  13.032 37.625 13.806 37.831 ;
     RECT  0.252 37.675 0.306 37.852 ;
     RECT  11.592 37.831 13.806 37.859 ;
     RECT  11.592 37.859 12.366 37.931 ;
     RECT  10.404 37.589 10.797 37.963 ;
     RECT  11.592 37.931 12.186 37.963 ;
     RECT  0.216 37.852 0.306 37.997 ;
     RECT  10.404 37.963 12.186 38.003 ;
     RECT  16.524 37.363 16.542 38.011 ;
     RECT  15.984 38.011 16.542 38.093 ;
     RECT  14.832 37.625 14.85 38.129 ;
     RECT  13.104 37.859 13.806 38.201 ;
     RECT  0.216 37.997 0.27 38.237 ;
     RECT  16.488 38.093 16.542 38.281 ;
     RECT  1.152 37.661 1.17 38.429 ;
     RECT  11.844 38.003 12.186 38.435 ;
     RECT  7.308 37.769 9.666 38.515 ;
     RECT  10.404 38.003 10.797 38.515 ;
     RECT  16.488 38.281 16.578 38.525 ;
     RECT  14.616 38.371 14.634 38.551 ;
     RECT  14.544 38.551 14.634 38.641 ;
     RECT  0.216 38.237 0.234 38.669 ;
     RECT  13.104 38.201 13.497 38.669 ;
     RECT  15.408 38.551 15.462 38.717 ;
     RECT  14.4 38.641 14.634 38.741 ;
     RECT  14.544 38.741 14.634 38.875 ;
     RECT  15.408 38.717 15.426 38.875 ;
     RECT  2.304 37.769 6.57 38.911 ;
     RECT  7.308 38.515 10.797 38.911 ;
     RECT  2.304 38.911 10.797 38.939 ;
     RECT  2.304 38.939 3.222 38.975 ;
     RECT  4.032 38.939 10.797 39.019 ;
     RECT  12.456 38.821 12.474 39.209 ;
     RECT  16.488 38.525 16.542 39.209 ;
     RECT  4.032 39.019 10.854 39.245 ;
     RECT  13.215 38.669 13.497 39.361 ;
     RECT  14.544 38.875 15.426 39.533 ;
     RECT  4.068 39.245 10.854 39.547 ;
     RECT  12.132 39.499 12.15 39.551 ;
     RECT  15.408 39.533 15.426 39.586 ;
     RECT  4.068 39.547 11.394 39.595 ;
     RECT  1.152 39.355 1.17 39.691 ;
     RECT  14.544 39.533 14.598 39.721 ;
     RECT  14.508 39.721 14.598 39.773 ;
     RECT  1.152 39.691 1.278 39.821 ;
     RECT  4.068 39.595 11.466 39.821 ;
     RECT  2.412 38.975 3.222 39.865 ;
     RECT  1.152 39.821 1.17 39.917 ;
     RECT  13.215 39.361 13.518 39.991 ;
     RECT  13.032 39.991 13.518 40.027 ;
     RECT  15.408 39.586 15.462 40.027 ;
     RECT  16.524 39.209 16.542 40.027 ;
     RECT  2.304 39.865 3.222 40.055 ;
     RECT  13.032 40.027 13.806 40.199 ;
     RECT  15.408 40.027 16.542 40.199 ;
     RECT  0.216 39.883 0.234 40.219 ;
     RECT  4.068 39.821 11.034 40.261 ;
     RECT  15.408 40.199 15.426 40.289 ;
     RECT  0.216 40.219 0.27 40.396 ;
     RECT  3.996 40.261 11.034 40.405 ;
     RECT  11.952 40.315 11.97 40.433 ;
     RECT  14.58 39.773 14.598 40.459 ;
     RECT  13.176 40.199 13.806 40.531 ;
     RECT  14.58 40.459 14.886 40.531 ;
     RECT  0.216 40.396 0.306 40.541 ;
     RECT  0.288 40.541 0.306 40.589 ;
     RECT  3.96 40.405 11.034 40.589 ;
     RECT  3.96 40.589 10.926 40.595 ;
     RECT  2.415 40.055 3.222 40.675 ;
     RECT  3.96 40.595 10.854 40.675 ;
     RECT  2.415 40.675 10.854 40.739 ;
     RECT  2.415 40.739 10.797 40.877 ;
     RECT  16.488 40.199 16.542 40.945 ;
     RECT  13.176 40.531 14.886 41.009 ;
     RECT  1.26 41.035 1.278 41.131 ;
     RECT  3.96 40.877 10.797 41.135 ;
     RECT  13.176 41.009 14.85 41.135 ;
     RECT  1.152 41.131 1.278 41.165 ;
     RECT  14.796 41.135 14.85 41.171 ;
     RECT  3.996 41.135 10.797 41.207 ;
     RECT  2.415 40.877 3.222 41.215 ;
     RECT  1.152 41.165 1.17 41.309 ;
     RECT  13.176 41.135 13.59 41.371 ;
     RECT  12.564 41.371 13.59 41.611 ;
     RECT  11.556 41.611 13.59 41.711 ;
     RECT  15.984 40.945 16.542 41.791 ;
     RECT  14.832 41.171 14.85 41.881 ;
     RECT  15.984 41.791 16.578 41.881 ;
     RECT  10.515 41.207 10.797 41.947 ;
     RECT  14.832 41.881 16.578 41.981 ;
     RECT  2.304 41.215 3.222 42.025 ;
     RECT  3.996 41.207 9.738 42.025 ;
     RECT  10.515 41.947 10.818 42.061 ;
     RECT  11.988 41.711 13.59 42.089 ;
     RECT  12.708 42.089 13.59 42.151 ;
     RECT  10.515 42.061 10.854 42.179 ;
     RECT  2.304 42.025 9.738 42.223 ;
     RECT  10.515 42.179 10.797 42.223 ;
     RECT  12.708 42.151 13.662 42.251 ;
     RECT  2.304 42.223 10.797 42.323 ;
     RECT  15.408 41.981 16.578 42.365 ;
     RECT  1.152 42.427 1.17 42.523 ;
     RECT  0.252 41.707 0.27 42.701 ;
     RECT  1.152 42.523 1.278 42.749 ;
     RECT  13.068 42.251 13.662 42.763 ;
     RECT  15.408 42.365 15.426 42.763 ;
     RECT  0.324 42.715 0.342 42.811 ;
     RECT  1.152 42.749 1.17 42.811 ;
     RECT  14.868 42.763 15.426 42.907 ;
     RECT  11.736 42.871 11.754 42.989 ;
     RECT  3.96 42.323 10.797 43.003 ;
     RECT  13.068 42.763 13.698 43.051 ;
     RECT  0.324 42.811 1.17 43.085 ;
     RECT  3.96 43.003 11.43 43.085 ;
     RECT  13.068 43.051 14.094 43.099 ;
     RECT  14.832 42.907 15.426 43.099 ;
     RECT  13.068 43.099 15.426 43.169 ;
     RECT  0.324 43.085 0.45 43.229 ;
     RECT  6.192 43.085 11.43 43.259 ;
     RECT  2.304 42.323 3.222 43.339 ;
     RECT  3.96 43.085 5.454 43.339 ;
     RECT  16.524 42.365 16.578 43.565 ;
     RECT  13.068 43.169 13.497 43.645 ;
     RECT  0.216 43.435 0.27 43.673 ;
     RECT  14.364 43.169 15.426 43.675 ;
     RECT  16.524 43.565 16.542 43.675 ;
     RECT  12.708 43.645 13.497 43.799 ;
     RECT  14.364 43.675 16.542 43.835 ;
     RECT  2.304 43.339 5.454 43.901 ;
     RECT  13.068 43.799 13.497 43.951 ;
     RECT  14.364 43.835 15.498 43.951 ;
     RECT  5.004 43.901 5.454 44.041 ;
     RECT  6.192 43.259 10.89 44.041 ;
     RECT  5.004 44.041 10.89 44.104 ;
     RECT  5.004 44.104 11.322 44.105 ;
     RECT  0.252 43.673 0.27 44.107 ;
     RECT  10.332 44.105 11.322 44.141 ;
     RECT  13.068 43.951 15.498 44.189 ;
     RECT  0.252 44.107 0.306 44.285 ;
     RECT  5.004 44.105 9.594 44.285 ;
     RECT  10.332 44.141 10.854 44.339 ;
     RECT  12.276 43.915 12.294 44.339 ;
     RECT  0.252 44.285 0.27 44.429 ;
     RECT  13.068 44.189 15.426 44.609 ;
     RECT  5.115 44.285 9.594 44.851 ;
     RECT  10.332 44.339 10.797 44.851 ;
     RECT  16.524 43.835 16.542 44.875 ;
     RECT  5.115 44.851 10.797 45.023 ;
     RECT  16.488 44.875 16.542 45.059 ;
     RECT  12.384 45.031 12.402 45.149 ;
     RECT  2.304 43.901 4.158 45.157 ;
     RECT  2.304 45.157 4.23 45.211 ;
     RECT  5.115 45.023 5.49 45.211 ;
     RECT  13.215 44.609 15.426 45.329 ;
     RECT  2.304 45.211 5.49 45.403 ;
     RECT  6.264 45.023 10.797 45.403 ;
     RECT  2.16 45.403 5.49 45.455 ;
     RECT  14.616 45.329 15.426 45.533 ;
     RECT  0.252 45.595 0.27 45.769 ;
     RECT  0.216 45.769 0.306 45.787 ;
     RECT  0.216 45.787 0.342 45.917 ;
     RECT  13.215 45.329 13.59 45.931 ;
     RECT  13.104 45.931 13.59 45.959 ;
     RECT  0.216 45.917 0.306 45.965 ;
     RECT  11.808 45.229 11.826 46.067 ;
     RECT  2.304 45.455 5.49 46.069 ;
     RECT  6.264 45.403 10.854 46.069 ;
     RECT  2.304 46.069 10.854 46.111 ;
     RECT  16.488 45.059 16.506 46.123 ;
     RECT  13.104 45.959 13.497 46.219 ;
     RECT  12.672 46.219 13.497 46.381 ;
     RECT  2.304 46.111 10.926 46.397 ;
     RECT  10.515 46.397 10.926 46.409 ;
     RECT  14.832 45.533 15.426 46.459 ;
     RECT  16.488 46.123 16.542 46.459 ;
     RECT  11.952 46.381 13.497 46.589 ;
     RECT  14.832 46.459 16.542 46.615 ;
     RECT  11.988 46.589 13.497 46.741 ;
     RECT  14.328 46.615 16.542 46.741 ;
     RECT  0.288 45.965 0.306 46.849 ;
     RECT  0.216 46.849 0.306 46.925 ;
     RECT  0.216 46.925 0.27 46.973 ;
     RECT  11.988 46.741 16.542 47.12 ;
     RECT  2.304 46.397 9.702 47.131 ;
     RECT  2.304 47.131 9.774 47.309 ;
     RECT  3.96 47.309 9.774 47.425 ;
     RECT  10.515 46.409 10.818 47.425 ;
     RECT  3.96 47.425 10.818 47.551 ;
     RECT  2.304 47.309 3.222 47.563 ;
     RECT  12.24 47.12 16.542 47.579 ;
     RECT  12.672 47.579 16.542 47.645 ;
     RECT  3.96 47.551 10.89 47.759 ;
     RECT  12.672 47.645 16.506 47.849 ;
     RECT  0.252 46.973 0.27 47.857 ;
     RECT  0.252 47.857 0.558 47.933 ;
     RECT  2.268 47.563 3.222 48.128 ;
     RECT  2.304 48.128 3.222 48.413 ;
     RECT  2.34 48.413 3.222 48.425 ;
     RECT  12.672 47.849 14.562 48.433 ;
     RECT  15.408 47.849 16.002 48.569 ;
     RECT  3.96 47.759 10.797 48.619 ;
     RECT  12.6 48.433 14.562 48.619 ;
     RECT  3.96 48.619 10.818 48.631 ;
     RECT  12.24 48.619 14.562 48.631 ;
     RECT  0.252 47.933 0.342 48.653 ;
     RECT  15.408 48.569 15.426 48.659 ;
     RECT  3.96 48.631 11.07 48.701 ;
     RECT  4.032 48.701 11.07 48.715 ;
     RECT  12.168 48.631 14.562 48.715 ;
     RECT  12.168 48.715 14.886 48.731 ;
     RECT  12.78 48.731 14.886 48.929 ;
     RECT  2.415 48.425 3.222 49.147 ;
     RECT  16.488 48.955 16.542 49.199 ;
     RECT  12.78 48.929 14.85 49.277 ;
     RECT  13.068 49.277 14.85 49.343 ;
     RECT  16.524 49.199 16.542 49.435 ;
     RECT  2.304 49.147 3.222 49.441 ;
     RECT  4.032 48.715 11.43 49.441 ;
     RECT  16.524 49.435 16.578 49.649 ;
     RECT  13.215 49.343 14.85 49.675 ;
     RECT  2.304 49.441 11.43 49.739 ;
     RECT  0.252 48.653 0.27 49.867 ;
     RECT  13.215 49.675 15.426 50.059 ;
     RECT  16.524 49.649 16.542 50.059 ;
     RECT  4.032 49.739 11.43 50.093 ;
     RECT  13.215 50.059 16.542 50.093 ;
     RECT  0.252 49.867 0.342 50.141 ;
     RECT  0.252 50.141 0.306 50.521 ;
     RECT  0.216 50.521 0.306 50.621 ;
     RECT  0.288 50.621 0.306 50.669 ;
     RECT  14.436 50.093 16.542 50.683 ;
     RECT  14.436 50.683 16.614 50.729 ;
     RECT  14.436 50.729 16.578 50.819 ;
     RECT  11.952 50.299 11.97 50.899 ;
     RECT  4.032 50.093 10.854 50.963 ;
     RECT  2.304 49.739 3.222 50.971 ;
     RECT  4.032 50.963 9.738 50.971 ;
     RECT  2.304 50.971 9.738 51.089 ;
     RECT  10.515 50.963 10.854 51.089 ;
     RECT  11.916 50.899 12.15 51.089 ;
     RECT  2.304 51.089 9.666 51.125 ;
     RECT  11.916 51.089 11.97 51.149 ;
     RECT  16.488 50.819 16.578 51.161 ;
     RECT  13.215 50.093 13.698 51.163 ;
     RECT  14.436 50.819 15.426 51.163 ;
     RECT  13.215 51.163 15.426 51.233 ;
     RECT  13.215 51.233 14.634 51.241 ;
     RECT  11.916 51.149 11.934 51.245 ;
     RECT  16.524 51.161 16.578 51.341 ;
     RECT  0.396 51.307 0.414 51.403 ;
     RECT  0.216 51.403 0.414 51.437 ;
     RECT  0.216 51.437 0.342 51.467 ;
     RECT  12.888 51.241 14.634 51.467 ;
     RECT  0.252 51.467 0.342 51.485 ;
     RECT  15.408 51.233 15.426 51.628 ;
     RECT  13.215 51.467 14.634 51.677 ;
     RECT  10.515 51.089 10.797 51.835 ;
     RECT  2.304 51.125 9.45 51.907 ;
     RECT  10.26 51.835 10.797 51.907 ;
     RECT  16.524 51.341 16.542 51.931 ;
     RECT  12.06 51.871 12.078 51.979 ;
     RECT  14.616 51.677 14.634 51.979 ;
     RECT  15.408 51.628 15.462 51.979 ;
     RECT  12.06 51.979 12.402 52.051 ;
     RECT  16.488 51.931 16.542 52.079 ;
     RECT  2.304 51.907 10.797 52.205 ;
     RECT  5.115 52.205 10.797 52.219 ;
     RECT  11.952 52.051 12.402 52.249 ;
     RECT  5.115 52.219 10.818 52.321 ;
     RECT  11.952 52.249 12.474 52.321 ;
     RECT  13.215 51.677 13.77 52.411 ;
     RECT  14.616 51.979 15.462 52.411 ;
     RECT  5.115 52.321 12.474 52.439 ;
     RECT  13.215 52.411 15.462 52.439 ;
     RECT  11.988 52.439 12.474 52.591 ;
     RECT  13.215 52.439 15.426 52.591 ;
     RECT  11.988 52.591 15.426 52.853 ;
     RECT  16.488 52.079 16.506 52.891 ;
     RECT  16.488 52.891 16.542 52.981 ;
     RECT  0.252 51.485 0.27 52.987 ;
     RECT  2.304 52.205 4.194 52.987 ;
     RECT  5.115 52.439 10.797 52.987 ;
     RECT  12.528 52.853 15.426 53.015 ;
     RECT  12.528 53.015 14.634 53.021 ;
     RECT  16.488 52.981 16.578 53.021 ;
     RECT  2.304 52.987 10.797 53.123 ;
     RECT  0.216 52.987 0.27 53.213 ;
     RECT  12.528 53.021 14.598 53.249 ;
     RECT  15.408 53.015 15.426 53.275 ;
     RECT  16.488 53.021 16.542 53.275 ;
     RECT  12.78 53.249 14.598 53.519 ;
     RECT  0.252 53.213 0.27 53.557 ;
     RECT  0.252 53.557 0.558 53.597 ;
     RECT  12.78 53.519 13.554 53.885 ;
     RECT  14.58 53.519 14.598 53.941 ;
     RECT  15.408 53.275 16.542 54.059 ;
     RECT  1.368 53.899 1.386 54.067 ;
     RECT  14.58 53.941 14.67 54.095 ;
     RECT  4.104 53.123 10.797 54.175 ;
     RECT  3.996 54.175 10.797 54.187 ;
     RECT  11.7 53.941 11.718 54.187 ;
     RECT  3.996 54.187 11.718 54.301 ;
     RECT  13.032 53.885 13.554 54.301 ;
     RECT  1.224 54.067 1.386 54.379 ;
     RECT  1.116 54.379 1.386 54.667 ;
     RECT  13.032 54.301 14.094 54.667 ;
     RECT  1.116 54.667 1.458 54.707 ;
     RECT  3.996 54.301 12.006 54.715 ;
     RECT  12.852 54.667 14.094 54.715 ;
     RECT  1.116 54.707 1.17 54.749 ;
     RECT  3.996 54.715 14.094 54.941 ;
     RECT  11.808 54.941 14.094 54.985 ;
     RECT  14.832 54.235 14.85 54.985 ;
     RECT  0.252 53.597 0.27 55.051 ;
     RECT  11.808 54.985 14.85 55.139 ;
     RECT  0.252 55.051 0.414 55.181 ;
     RECT  3.996 54.941 10.797 55.211 ;
     RECT  5.076 55.211 10.797 55.229 ;
     RECT  15.984 54.059 16.542 55.243 ;
     RECT  2.304 53.123 3.15 55.255 ;
     RECT  3.996 55.211 4.194 55.255 ;
     RECT  5.112 55.229 10.797 55.325 ;
     RECT  15.408 55.243 16.542 55.523 ;
     RECT  12.348 55.139 14.634 55.589 ;
     RECT  1.152 54.749 1.17 55.675 ;
     RECT  0.288 55.181 0.414 55.795 ;
     RECT  1.152 55.675 1.278 55.795 ;
     RECT  0.288 55.795 1.278 55.805 ;
     RECT  16.488 55.523 16.542 55.805 ;
     RECT  2.304 55.255 4.194 55.853 ;
     RECT  12.564 55.589 14.634 55.867 ;
     RECT  15.408 55.523 15.426 55.867 ;
     RECT  0.288 55.805 0.558 55.901 ;
     RECT  4.068 55.853 4.194 55.993 ;
     RECT  5.112 55.325 9.702 55.993 ;
     RECT  12.564 55.867 15.426 56.021 ;
     RECT  14.292 56.021 15.426 56.129 ;
     RECT  16.488 55.805 16.506 56.219 ;
     RECT  0.288 55.901 0.486 56.251 ;
     RECT  10.515 55.325 10.797 56.335 ;
     RECT  12.564 56.021 13.497 56.336 ;
     RECT  0.252 56.251 0.486 56.381 ;
     RECT  14.796 56.129 15.426 56.587 ;
     RECT  10.515 56.335 10.854 56.605 ;
     RECT  4.068 55.993 9.702 56.767 ;
     RECT  10.515 56.605 10.89 56.767 ;
     RECT  2.304 55.853 3.222 56.911 ;
     RECT  4.068 56.767 10.89 56.911 ;
     RECT  0.252 56.381 0.342 56.923 ;
     RECT  14.796 56.587 16.002 56.939 ;
     RECT  2.304 56.911 10.89 57.064 ;
     RECT  2.304 57.064 11.43 57.065 ;
     RECT  13.032 56.336 13.497 57.109 ;
     RECT  0.216 56.923 0.342 57.209 ;
     RECT  12.6 57.109 13.497 57.271 ;
     RECT  14.796 56.939 15.462 57.371 ;
     RECT  12.6 57.271 13.662 57.451 ;
     RECT  2.415 57.065 11.43 57.479 ;
     RECT  12.6 57.451 13.77 57.541 ;
     RECT  14.796 57.371 15.426 57.541 ;
     RECT  12.528 57.541 15.426 57.721 ;
     RECT  16.524 57.019 16.542 57.721 ;
     RECT  12.456 57.721 15.426 57.835 ;
     RECT  11.988 57.835 15.426 57.839 ;
     RECT  0.216 57.209 0.306 57.884 ;
     RECT  2.415 57.479 10.797 57.931 ;
     RECT  16.524 57.721 16.578 58.117 ;
     RECT  16.524 58.117 17.082 58.205 ;
     RECT  0.252 57.884 0.306 58.363 ;
     RECT  2.304 57.931 10.797 58.415 ;
     RECT  16.524 58.205 16.542 58.415 ;
     RECT  0.252 58.363 0.45 58.493 ;
     RECT  11.988 57.839 12.042 58.531 ;
     RECT  1.152 58.507 1.17 58.555 ;
     RECT  13.032 57.839 15.426 58.555 ;
     RECT  1.152 58.555 1.278 58.685 ;
     RECT  13.032 58.555 15.462 58.891 ;
     RECT  0.252 58.493 0.378 58.925 ;
     RECT  11.628 58.531 12.042 58.927 ;
     RECT  13.032 58.891 16.002 58.963 ;
     RECT  0.252 58.925 0.342 59.021 ;
     RECT  2.415 58.415 10.797 59.071 ;
     RECT  11.628 58.927 12.114 59.071 ;
     RECT  12.996 58.963 16.002 59.161 ;
     RECT  12.996 59.161 16.506 59.261 ;
     RECT  0.252 59.021 0.306 59.305 ;
     RECT  2.415 59.071 12.114 59.341 ;
     RECT  0.216 59.305 0.306 59.453 ;
     RECT  0.288 59.453 0.306 59.501 ;
     RECT  2.415 59.341 12.258 59.515 ;
     RECT  15.408 59.261 16.506 59.515 ;
     RECT  2.304 59.515 12.258 59.563 ;
     RECT  12.996 59.261 14.382 59.563 ;
     RECT  1.152 58.685 1.17 59.707 ;
     RECT  1.152 59.707 1.278 59.837 ;
     RECT  15.408 59.515 16.542 59.933 ;
     RECT  2.304 59.563 14.382 60.035 ;
     RECT  10.515 60.035 14.382 60.043 ;
     RECT  15.408 59.933 15.426 60.043 ;
     RECT  2.415 60.035 9.666 60.077 ;
     RECT  3.96 60.077 9.666 60.125 ;
     RECT  10.515 60.043 15.426 60.143 ;
     RECT  16.524 59.933 16.542 60.173 ;
     RECT  11.808 60.143 15.426 60.179 ;
     RECT  3.96 60.125 5.994 60.227 ;
     RECT  10.515 60.143 10.797 60.227 ;
     RECT  3.96 60.227 5.205 60.269 ;
     RECT  5.976 60.227 5.994 60.269 ;
     RECT  11.808 60.179 13.914 60.269 ;
     RECT  2.415 60.077 3.222 60.305 ;
     RECT  3.96 60.269 4.194 60.305 ;
     RECT  6.732 60.125 9.666 60.305 ;
     RECT  14.76 60.179 15.426 60.305 ;
     RECT  11.808 60.269 13.374 60.317 ;
     RECT  4.176 60.305 4.194 60.341 ;
     RECT  14.832 60.305 15.426 60.365 ;
     RECT  11.808 60.317 13.305 60.377 ;
     RECT  14.832 60.365 14.994 60.377 ;
     RECT  0.252 60.235 0.27 60.413 ;
     RECT  2.415 60.305 2.754 60.413 ;
     RECT  7.815 60.305 9.666 60.413 ;
     RECT  11.808 60.377 11.826 60.413 ;
     RECT  7.815 60.413 9.486 60.461 ;
     RECT  14.976 60.377 14.994 60.461 ;
     RECT  2.415 60.413 2.505 60.497 ;
     RECT  4.932 60.269 5.205 60.497 ;
     RECT  7.815 60.461 7.905 60.497 ;
     RECT  10.515 60.227 10.605 60.497 ;
     RECT  13.215 60.377 13.305 60.497 ;
     RECT  6.732 60.305 7.038 60.539 ;
     RECT  8.784 60.461 8.874 60.539 ;
     RECT  7.02 60.539 7.038 60.575 ;
     RECT  8.784 60.539 8.802 60.575 ;
     RECT  4.932 60.497 4.95 60.605 ;
     RECT  5.4 61.579 5.418 62.508 ;
    LAYER M4 ;
     RECT  0.156 2.208 2.293 60.456 ;
     RECT  2.293 2.208 2.408 60.6 ;
     RECT  2.408 2.148 2.512 60.6 ;
     RECT  2.512 2.418 2.704 60.6 ;
     RECT  2.704 2.496 4.961 60.6 ;
     RECT  4.961 2.496 5.108 60.492 ;
     RECT  5.108 2.148 5.212 60.492 ;
     RECT  5.212 2.418 5.404 60.408 ;
     RECT  5.389 61.584 6.035 61.608 ;
     RECT  5.404 2.496 6.901 60.408 ;
     RECT  6.901 2.256 7.808 60.408 ;
     RECT  7.808 2.148 7.912 60.492 ;
     RECT  7.912 2.256 8.881 60.456 ;
     RECT  8.881 2.208 9.317 60.456 ;
     RECT  9.317 2.832 9.497 60.456 ;
     RECT  9.497 2.832 10.508 60.408 ;
     RECT  10.508 2.148 10.612 60.492 ;
     RECT  10.612 2.418 10.804 60.36 ;
     RECT  10.804 2.736 11.621 60.36 ;
     RECT  11.621 6 11.797 60.36 ;
     RECT  11.797 6 11.891 60.408 ;
     RECT  11.891 6 11.981 60.36 ;
     RECT  11.981 6 12.017 20.088 ;
     RECT  11.981 21.408 12.017 60.36 ;
     RECT  12.017 17.424 12.233 20.088 ;
     RECT  11.621 2.736 13.208 4.68 ;
     RECT  12.017 6 13.208 16.392 ;
     RECT  12.233 18 13.208 20.088 ;
     RECT  12.017 21.408 13.208 22.776 ;
     RECT  12.017 23.904 13.208 60.36 ;
     RECT  13.208 2.148 13.312 60.492 ;
     RECT  13.312 2.418 13.385 60.312 ;
     RECT  13.385 2.418 13.504 60.264 ;
     RECT  13.504 3.024 13.565 3.624 ;
     RECT  13.504 19.824 13.601 19.848 ;
     RECT  13.504 46.8 13.673 53.4 ;
     RECT  13.504 57.408 13.673 58.296 ;
     RECT  13.504 14.688 13.709 16.392 ;
     RECT  13.504 22.032 13.709 22.776 ;
     RECT  13.504 31.44 13.709 31.464 ;
     RECT  13.504 34.704 13.709 36.12 ;
     RECT  13.504 59.28 13.709 60.264 ;
     RECT  13.709 22.032 13.817 22.056 ;
     RECT  13.504 28.752 13.817 29.88 ;
     RECT  13.673 46.8 13.817 48.168 ;
     RECT  13.504 10.656 13.889 11.448 ;
     RECT  13.709 36 13.889 36.12 ;
     RECT  13.889 10.944 14.249 11.448 ;
     RECT  13.504 32.592 14.249 33.672 ;
     RECT  13.673 49.2 14.249 53.4 ;
     RECT  13.817 46.8 14.429 47.448 ;
     RECT  13.504 37.44 14.605 40.92 ;
     RECT  13.504 4.656 14.821 4.68 ;
     RECT  13.504 6 14.821 6.696 ;
     RECT  13.504 9.312 14.821 9.336 ;
     RECT  14.249 11.328 14.821 11.448 ;
     RECT  13.504 12.768 14.821 13.704 ;
     RECT  13.709 14.688 14.821 14.712 ;
     RECT  13.709 15.984 14.821 16.392 ;
     RECT  13.504 18 14.821 18.6 ;
     RECT  13.504 23.904 14.821 23.928 ;
     RECT  13.504 25.008 14.821 25.032 ;
     RECT  13.504 26.256 14.821 27.624 ;
     RECT  13.817 28.752 14.821 29.256 ;
     RECT  14.249 33.216 14.821 33.672 ;
     RECT  13.709 34.704 14.821 34.728 ;
     RECT  13.889 36.096 14.821 36.12 ;
     RECT  14.605 37.248 14.821 40.92 ;
     RECT  13.504 43.056 14.821 45.528 ;
     RECT  14.429 46.8 14.821 47.112 ;
     RECT  14.249 49.2 14.821 53.112 ;
     RECT  13.504 55.152 14.821 56.04 ;
     RECT  13.673 57.504 14.821 58.296 ;
     RECT  13.709 59.52 14.821 60.264 ;
     RECT  14.821 7.728 14.857 9.336 ;
     RECT  14.821 54.24 14.965 60.264 ;
     RECT  14.821 2.736 15.397 6.696 ;
     RECT  14.857 7.728 15.397 10.344 ;
     RECT  14.821 11.328 15.397 32.184 ;
     RECT  14.821 33.216 15.397 35.064 ;
     RECT  14.821 36.096 15.397 41.832 ;
     RECT  14.821 42.912 15.397 47.112 ;
     RECT  14.821 48.72 15.397 53.112 ;
     RECT  14.965 54.24 15.397 60.456 ;
     RECT  15.397 2.544 15.973 60.456 ;
     RECT  15.973 2.448 16.477 60.456 ;
     RECT  16.477 2.208 17.1 60.456 ;
    LAYER M5 ;
     RECT  2.4 2.137 2.52 2.151 ;
     RECT  5.1 2.137 5.22 2.151 ;
     RECT  7.8 2.137 7.92 2.151 ;
     RECT  10.5 2.137 10.62 2.151 ;
     RECT  13.2 2.137 13.32 2.151 ;
     RECT  7.8 2.151 8.112 2.581 ;
     RECT  5.1 2.151 5.412 2.773 ;
     RECT  7.8 2.581 8.376 2.773 ;
     RECT  7.44 2.773 8.376 3.107 ;
     RECT  5.1 2.773 6.264 3.443 ;
     RECT  2.4 2.151 2.712 3.637 ;
     RECT  2.304 3.637 2.712 3.827 ;
     RECT  7.8 3.107 8.376 4.547 ;
     RECT  7.8 4.547 8.28 4.885 ;
     RECT  6.864 4.885 8.28 5.075 ;
     RECT  2.4 3.827 2.712 6.229 ;
     RECT  2.4 6.229 3.432 6.757 ;
     RECT  5.1 3.443 5.412 6.805 ;
     RECT  2.4 6.757 3.96 6.899 ;
     RECT  5.1 6.805 6.312 7.715 ;
     RECT  2.4 6.899 3.432 7.859 ;
     RECT  5.1 7.715 6.168 7.957 ;
     RECT  7.8 5.075 8.28 8.389 ;
     RECT  4.56 7.957 6.168 9.061 ;
     RECT  4.56 9.061 6.264 9.539 ;
     RECT  1.152 9.445 1.176 9.635 ;
     RECT  5.1 9.539 6.264 10.259 ;
     RECT  2.4 7.859 3.24 10.307 ;
     RECT  2.4 10.307 2.712 10.357 ;
     RECT  2.304 10.357 2.712 10.787 ;
     RECT  7.8 8.389 8.808 11.509 ;
     RECT  7.68 11.509 8.808 11.843 ;
     RECT  5.1 10.259 6.024 16.067 ;
     RECT  7.8 11.843 8.808 16.549 ;
     RECT  7.584 16.549 8.808 16.691 ;
     RECT  7.8 16.691 8.808 16.885 ;
     RECT  7.8 16.885 9 17.173 ;
     RECT  7.8 17.173 9.144 17.411 ;
     RECT  7.8 17.411 8.808 18.085 ;
     RECT  7.152 18.085 8.808 18.851 ;
     RECT  5.1 16.067 5.412 18.949 ;
     RECT  5.1 18.949 5.688 19.333 ;
     RECT  7.296 18.851 8.808 19.861 ;
     RECT  7.296 19.861 9.096 19.907 ;
     RECT  2.4 10.787 2.712 20.149 ;
     RECT  7.8 19.907 9.096 20.531 ;
     RECT  7.8 20.531 8.808 20.867 ;
     RECT  2.4 20.149 2.904 21.155 ;
     RECT  2.4 21.155 2.808 21.251 ;
     RECT  5.1 19.333 6.072 21.397 ;
     RECT  1.248 21.205 1.272 21.443 ;
     RECT  5.1 21.397 6.12 22.307 ;
     RECT  5.1 22.307 6.072 24.469 ;
     RECT  5.1 24.469 6.6 24.611 ;
     RECT  2.4 21.251 2.712 24.853 ;
     RECT  2.304 24.853 2.712 24.995 ;
     RECT  5.1 24.611 6.072 25.091 ;
     RECT  7.8 20.867 8.232 25.237 ;
     RECT  7.8 25.237 8.76 25.523 ;
     RECT  7.8 25.523 8.232 26.773 ;
     RECT  7.8 26.773 8.328 26.915 ;
     RECT  2.4 24.995 2.712 27.541 ;
     RECT  2.4 27.541 3.192 27.683 ;
     RECT  7.8 26.915 8.232 28.499 ;
     RECT  2.4 27.683 2.712 28.885 ;
     RECT  2.4 28.885 3.336 28.981 ;
     RECT  2.4 28.981 3.432 29.077 ;
     RECT  5.1 25.091 5.976 29.173 ;
     RECT  2.304 29.077 3.432 29.315 ;
     RECT  5.1 29.173 6.312 29.363 ;
     RECT  7.8 28.499 8.112 29.893 ;
     RECT  0.192 29.989 0.216 30.179 ;
     RECT  7.8 29.893 8.232 30.325 ;
     RECT  2.4 29.315 3.432 30.371 ;
     RECT  7.68 30.325 8.232 30.755 ;
     RECT  3.84 31.333 3.864 31.475 ;
     RECT  0.192 31.621 0.216 31.811 ;
     RECT  5.1 29.363 5.976 32.003 ;
     RECT  7.8 30.755 8.232 32.245 ;
     RECT  5.1 32.003 5.688 33.013 ;
     RECT  7.68 32.245 8.232 33.109 ;
     RECT  7.68 33.109 8.52 33.347 ;
     RECT  3.84 34.453 3.864 34.645 ;
     RECT  3.84 34.645 3.96 34.691 ;
     RECT  3.936 34.691 3.96 34.835 ;
     RECT  2.4 30.371 2.712 36.421 ;
     RECT  7.68 33.347 8.328 37.045 ;
     RECT  2.4 36.421 3.432 37.091 ;
     RECT  7.68 37.045 9.096 37.235 ;
     RECT  5.1 33.013 6.024 38.101 ;
     RECT  7.68 37.235 8.328 38.147 ;
     RECT  2.4 37.091 2.712 39.445 ;
     RECT  2.304 39.445 2.712 39.587 ;
     RECT  5.1 38.101 6.168 40.789 ;
     RECT  5.1 40.789 6.216 42.709 ;
     RECT  2.4 39.587 2.712 45.253 ;
     RECT  5.1 42.709 6.312 45.301 ;
     RECT  2.304 45.253 2.712 45.443 ;
     RECT  5.1 45.301 6.552 45.781 ;
     RECT  7.8 38.147 8.328 45.781 ;
     RECT  5.1 45.781 8.328 46.211 ;
     RECT  5.1 46.211 8.28 46.693 ;
     RECT  0.288 46.597 0.312 46.835 ;
     RECT  4.896 46.693 8.28 48.229 ;
     RECT  4.896 48.229 8.376 48.371 ;
     RECT  5.1 48.371 8.376 48.803 ;
     RECT  2.4 45.443 2.712 50.917 ;
     RECT  2.304 50.917 2.712 51.107 ;
     RECT  5.1 48.803 6.552 51.635 ;
     RECT  2.4 51.107 2.712 51.733 ;
     RECT  10.5 2.151 10.812 52.021 ;
     RECT  10.176 52.021 10.812 52.211 ;
     RECT  2.4 51.733 3.24 52.451 ;
     RECT  7.8 48.803 8.376 53.123 ;
     RECT  7.8 53.123 8.232 53.219 ;
     RECT  7.8 53.219 8.112 53.557 ;
     RECT  10.5 52.211 10.812 53.797 ;
     RECT  5.1 51.635 6.312 54.085 ;
     RECT  7.68 53.557 8.112 54.085 ;
     RECT  5.1 54.085 8.112 54.755 ;
     RECT  5.1 54.755 6.744 55.093 ;
     RECT  0.192 55.621 0.216 55.811 ;
     RECT  4.8 55.093 6.744 56.533 ;
     RECT  4.656 56.533 6.744 56.867 ;
     RECT  2.4 52.451 2.712 56.917 ;
     RECT  2.4 56.917 3.384 57.587 ;
     RECT  4.8 56.867 6.744 57.971 ;
     RECT  5.1 57.971 6.744 58.163 ;
     RECT  7.8 54.755 8.112 59.797 ;
     RECT  7.8 59.797 9.048 59.987 ;
     RECT  10.5 53.797 11.112 60.083 ;
     RECT  2.4 57.587 2.712 60.421 ;
     RECT  2.304 60.421 2.712 60.489 ;
     RECT  7.8 59.987 8.112 60.489 ;
     RECT  10.5 60.083 10.812 60.489 ;
     RECT  13.2 2.151 13.512 60.489 ;
     RECT  2.304 60.489 2.52 60.503 ;
     RECT  5.1 58.163 6.024 60.503 ;
     RECT  7.8 60.489 7.92 60.503 ;
     RECT  10.5 60.489 10.62 60.503 ;
     RECT  13.2 60.489 13.32 60.503 ;
     RECT  2.304 60.503 2.328 60.611 ;
     RECT  6 60.503 6.024 61.619 ;
     RECT  11.856 60.373 11.88 62.48 ;
  END
END dsfd_dvrly_562_WE
END LIBRARY
